VERSION 5.8 ;
BUSBITCHARS "[]" ;
DIVIDERCHAR "/" ;
UNITS
    DATABASE MICRONS 1000 ;
END UNITS

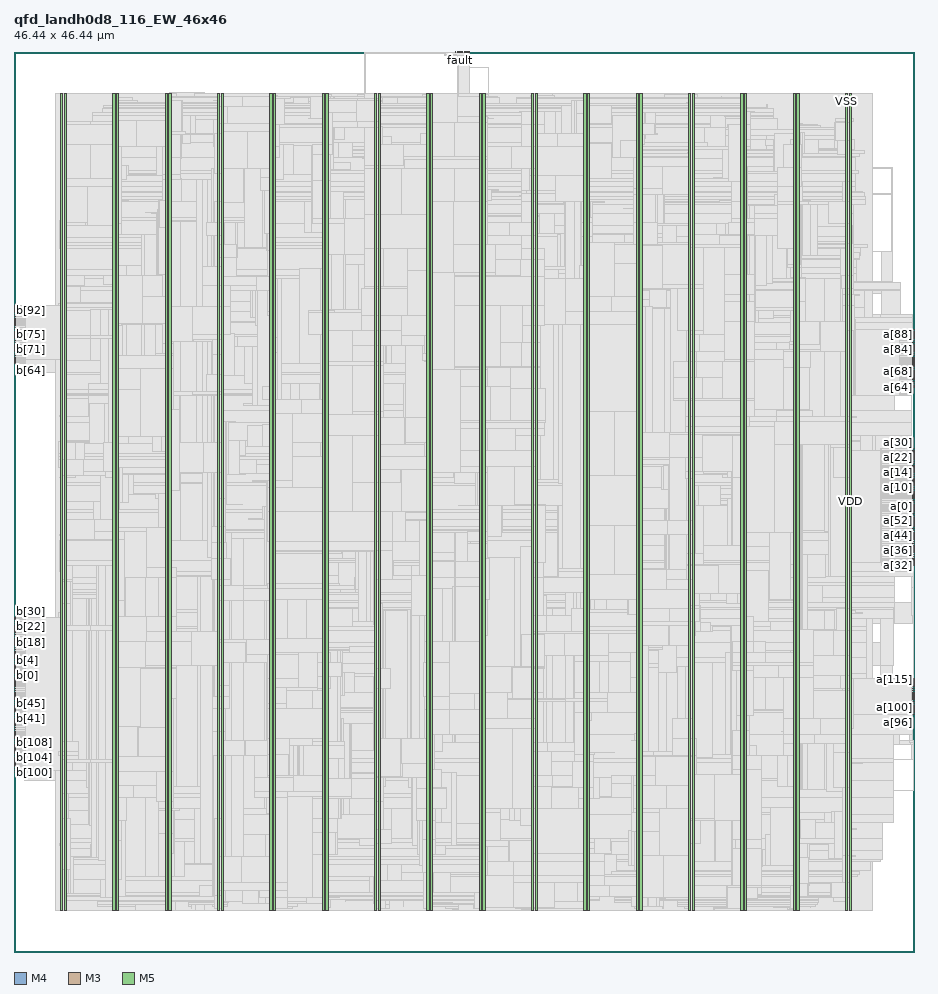
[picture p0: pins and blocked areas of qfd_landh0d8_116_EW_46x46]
MACRO qfd_landh0d8_116_EW_46x46
  FOREIGN qfd_landh0d8_116_EW_46x46 0 0 ;
  CLASS BLOCK ;
  SIZE 46.44 BY 46.44 ;
  PIN a[0]
    DIRECTION INPUT ;
    USE SIGNAL ;
    PORT
      LAYER M4 ;
        RECT  46.356 22.992 46.44 23.016 ;
    END
  END a[0]
  PIN a[100]
    DIRECTION INPUT ;
    USE SIGNAL ;
    PORT
      LAYER M4 ;
        RECT  46.356 12.624 46.44 12.648 ;
    END
  END a[100]
  PIN a[101]
    DIRECTION INPUT ;
    USE SIGNAL ;
    PORT
      LAYER M4 ;
        RECT  46.356 12.72 46.44 12.744 ;
    END
  END a[101]
  PIN a[102]
    DIRECTION INPUT ;
    USE SIGNAL ;
    PORT
      LAYER M4 ;
        RECT  46.356 12.816 46.44 12.84 ;
    END
  END a[102]
  PIN a[103]
    DIRECTION INPUT ;
    USE SIGNAL ;
    PORT
      LAYER M4 ;
        RECT  46.356 12.912 46.44 12.936 ;
    END
  END a[103]
  PIN a[104]
    DIRECTION INPUT ;
    USE SIGNAL ;
    PORT
      LAYER M4 ;
        RECT  46.356 13.008 46.44 13.032 ;
    END
  END a[104]
  PIN a[105]
    DIRECTION INPUT ;
    USE SIGNAL ;
    PORT
      LAYER M4 ;
        RECT  46.356 13.104 46.44 13.128 ;
    END
  END a[105]
  PIN a[106]
    DIRECTION INPUT ;
    USE SIGNAL ;
    PORT
      LAYER M4 ;
        RECT  46.356 13.2 46.44 13.224 ;
    END
  END a[106]
  PIN a[107]
    DIRECTION INPUT ;
    USE SIGNAL ;
    PORT
      LAYER M4 ;
        RECT  46.356 13.296 46.44 13.32 ;
    END
  END a[107]
  PIN a[108]
    DIRECTION INPUT ;
    USE SIGNAL ;
    PORT
      LAYER M4 ;
        RECT  46.356 13.392 46.44 13.416 ;
    END
  END a[108]
  PIN a[109]
    DIRECTION INPUT ;
    USE SIGNAL ;
    PORT
      LAYER M4 ;
        RECT  46.356 13.488 46.44 13.512 ;
    END
  END a[109]
  PIN a[10]
    DIRECTION INPUT ;
    USE SIGNAL ;
    PORT
      LAYER M4 ;
        RECT  46.356 23.952 46.44 23.976 ;
    END
  END a[10]
  PIN a[110]
    DIRECTION INPUT ;
    USE SIGNAL ;
    PORT
      LAYER M4 ;
        RECT  46.356 13.584 46.44 13.608 ;
    END
  END a[110]
  PIN a[111]
    DIRECTION INPUT ;
    USE SIGNAL ;
    PORT
      LAYER M4 ;
        RECT  46.356 13.68 46.44 13.704 ;
    END
  END a[111]
  PIN a[112]
    DIRECTION INPUT ;
    USE SIGNAL ;
    PORT
      LAYER M4 ;
        RECT  46.356 13.776 46.44 13.8 ;
    END
  END a[112]
  PIN a[113]
    DIRECTION INPUT ;
    USE SIGNAL ;
    PORT
      LAYER M4 ;
        RECT  46.356 13.872 46.44 13.896 ;
    END
  END a[113]
  PIN a[114]
    DIRECTION INPUT ;
    USE SIGNAL ;
    PORT
      LAYER M4 ;
        RECT  46.356 13.968 46.44 13.992 ;
    END
  END a[114]
  PIN a[115]
    DIRECTION INPUT ;
    USE SIGNAL ;
    PORT
      LAYER M4 ;
        RECT  46.356 14.064 46.44 14.088 ;
    END
  END a[115]
  PIN a[11]
    DIRECTION INPUT ;
    USE SIGNAL ;
    PORT
      LAYER M4 ;
        RECT  46.356 24.048 46.44 24.072 ;
    END
  END a[11]
  PIN a[12]
    DIRECTION INPUT ;
    USE SIGNAL ;
    PORT
      LAYER M4 ;
        RECT  46.356 24.144 46.44 24.168 ;
    END
  END a[12]
  PIN a[13]
    DIRECTION INPUT ;
    USE SIGNAL ;
    PORT
      LAYER M4 ;
        RECT  46.356 24.24 46.44 24.264 ;
    END
  END a[13]
  PIN a[14]
    DIRECTION INPUT ;
    USE SIGNAL ;
    PORT
      LAYER M4 ;
        RECT  46.356 24.336 46.44 24.36 ;
    END
  END a[14]
  PIN a[15]
    DIRECTION INPUT ;
    USE SIGNAL ;
    PORT
      LAYER M4 ;
        RECT  46.356 24.432 46.44 24.456 ;
    END
  END a[15]
  PIN a[16]
    DIRECTION INPUT ;
    USE SIGNAL ;
    PORT
      LAYER M4 ;
        RECT  46.356 24.528 46.44 24.552 ;
    END
  END a[16]
  PIN a[17]
    DIRECTION INPUT ;
    USE SIGNAL ;
    PORT
      LAYER M4 ;
        RECT  46.356 24.624 46.44 24.648 ;
    END
  END a[17]
  PIN a[18]
    DIRECTION INPUT ;
    USE SIGNAL ;
    PORT
      LAYER M4 ;
        RECT  46.356 24.72 46.44 24.744 ;
    END
  END a[18]
  PIN a[19]
    DIRECTION INPUT ;
    USE SIGNAL ;
    PORT
      LAYER M4 ;
        RECT  46.356 24.816 46.44 24.84 ;
    END
  END a[19]
  PIN a[1]
    DIRECTION INPUT ;
    USE SIGNAL ;
    PORT
      LAYER M4 ;
        RECT  46.356 23.088 46.44 23.112 ;
    END
  END a[1]
  PIN a[20]
    DIRECTION INPUT ;
    USE SIGNAL ;
    PORT
      LAYER M4 ;
        RECT  46.356 24.912 46.44 24.936 ;
    END
  END a[20]
  PIN a[21]
    DIRECTION INPUT ;
    USE SIGNAL ;
    PORT
      LAYER M4 ;
        RECT  46.356 25.008 46.44 25.032 ;
    END
  END a[21]
  PIN a[22]
    DIRECTION INPUT ;
    USE SIGNAL ;
    PORT
      LAYER M4 ;
        RECT  46.356 25.104 46.44 25.128 ;
    END
  END a[22]
  PIN a[23]
    DIRECTION INPUT ;
    USE SIGNAL ;
    PORT
      LAYER M4 ;
        RECT  46.356 25.2 46.44 25.224 ;
    END
  END a[23]
  PIN a[24]
    DIRECTION INPUT ;
    USE SIGNAL ;
    PORT
      LAYER M4 ;
        RECT  46.356 25.296 46.44 25.32 ;
    END
  END a[24]
  PIN a[25]
    DIRECTION INPUT ;
    USE SIGNAL ;
    PORT
      LAYER M4 ;
        RECT  46.356 25.392 46.44 25.416 ;
    END
  END a[25]
  PIN a[26]
    DIRECTION INPUT ;
    USE SIGNAL ;
    PORT
      LAYER M4 ;
        RECT  46.356 25.488 46.44 25.512 ;
    END
  END a[26]
  PIN a[27]
    DIRECTION INPUT ;
    USE SIGNAL ;
    PORT
      LAYER M4 ;
        RECT  46.356 25.584 46.44 25.608 ;
    END
  END a[27]
  PIN a[28]
    DIRECTION INPUT ;
    USE SIGNAL ;
    PORT
      LAYER M4 ;
        RECT  46.356 25.68 46.44 25.704 ;
    END
  END a[28]
  PIN a[29]
    DIRECTION INPUT ;
    USE SIGNAL ;
    PORT
      LAYER M4 ;
        RECT  46.356 25.776 46.44 25.8 ;
    END
  END a[29]
  PIN a[2]
    DIRECTION INPUT ;
    USE SIGNAL ;
    PORT
      LAYER M4 ;
        RECT  46.356 23.184 46.44 23.208 ;
    END
  END a[2]
  PIN a[30]
    DIRECTION INPUT ;
    USE SIGNAL ;
    PORT
      LAYER M4 ;
        RECT  46.356 25.872 46.44 25.896 ;
    END
  END a[30]
  PIN a[31]
    DIRECTION INPUT ;
    USE SIGNAL ;
    PORT
      LAYER M4 ;
        RECT  46.356 25.968 46.44 25.992 ;
    END
  END a[31]
  PIN a[32]
    DIRECTION INPUT ;
    USE SIGNAL ;
    PORT
      LAYER M4 ;
        RECT  46.356 19.92 46.44 19.944 ;
    END
  END a[32]
  PIN a[33]
    DIRECTION INPUT ;
    USE SIGNAL ;
    PORT
      LAYER M4 ;
        RECT  46.356 20.016 46.44 20.04 ;
    END
  END a[33]
  PIN a[34]
    DIRECTION INPUT ;
    USE SIGNAL ;
    PORT
      LAYER M4 ;
        RECT  46.356 20.112 46.44 20.136 ;
    END
  END a[34]
  PIN a[35]
    DIRECTION INPUT ;
    USE SIGNAL ;
    PORT
      LAYER M4 ;
        RECT  46.356 20.208 46.44 20.232 ;
    END
  END a[35]
  PIN a[36]
    DIRECTION INPUT ;
    USE SIGNAL ;
    PORT
      LAYER M4 ;
        RECT  46.356 20.304 46.44 20.328 ;
    END
  END a[36]
  PIN a[37]
    DIRECTION INPUT ;
    USE SIGNAL ;
    PORT
      LAYER M4 ;
        RECT  46.356 20.4 46.44 20.424 ;
    END
  END a[37]
  PIN a[38]
    DIRECTION INPUT ;
    USE SIGNAL ;
    PORT
      LAYER M4 ;
        RECT  46.356 20.496 46.44 20.52 ;
    END
  END a[38]
  PIN a[39]
    DIRECTION INPUT ;
    USE SIGNAL ;
    PORT
      LAYER M4 ;
        RECT  46.356 20.592 46.44 20.616 ;
    END
  END a[39]
  PIN a[3]
    DIRECTION INPUT ;
    USE SIGNAL ;
    PORT
      LAYER M4 ;
        RECT  46.356 23.28 46.44 23.304 ;
    END
  END a[3]
  PIN a[40]
    DIRECTION INPUT ;
    USE SIGNAL ;
    PORT
      LAYER M4 ;
        RECT  46.356 20.688 46.44 20.712 ;
    END
  END a[40]
  PIN a[41]
    DIRECTION INPUT ;
    USE SIGNAL ;
    PORT
      LAYER M4 ;
        RECT  46.356 20.784 46.44 20.808 ;
    END
  END a[41]
  PIN a[42]
    DIRECTION INPUT ;
    USE SIGNAL ;
    PORT
      LAYER M4 ;
        RECT  46.356 20.88 46.44 20.904 ;
    END
  END a[42]
  PIN a[43]
    DIRECTION INPUT ;
    USE SIGNAL ;
    PORT
      LAYER M4 ;
        RECT  46.356 20.976 46.44 21 ;
    END
  END a[43]
  PIN a[44]
    DIRECTION INPUT ;
    USE SIGNAL ;
    PORT
      LAYER M4 ;
        RECT  46.356 21.072 46.44 21.096 ;
    END
  END a[44]
  PIN a[45]
    DIRECTION INPUT ;
    USE SIGNAL ;
    PORT
      LAYER M4 ;
        RECT  46.356 21.168 46.44 21.192 ;
    END
  END a[45]
  PIN a[46]
    DIRECTION INPUT ;
    USE SIGNAL ;
    PORT
      LAYER M4 ;
        RECT  46.356 21.264 46.44 21.288 ;
    END
  END a[46]
  PIN a[47]
    DIRECTION INPUT ;
    USE SIGNAL ;
    PORT
      LAYER M4 ;
        RECT  46.356 21.36 46.44 21.384 ;
    END
  END a[47]
  PIN a[48]
    DIRECTION INPUT ;
    USE SIGNAL ;
    PORT
      LAYER M4 ;
        RECT  46.356 21.456 46.44 21.48 ;
    END
  END a[48]
  PIN a[49]
    DIRECTION INPUT ;
    USE SIGNAL ;
    PORT
      LAYER M4 ;
        RECT  46.356 21.552 46.44 21.576 ;
    END
  END a[49]
  PIN a[4]
    DIRECTION INPUT ;
    USE SIGNAL ;
    PORT
      LAYER M4 ;
        RECT  46.356 23.376 46.44 23.4 ;
    END
  END a[4]
  PIN a[50]
    DIRECTION INPUT ;
    USE SIGNAL ;
    PORT
      LAYER M4 ;
        RECT  46.356 21.648 46.44 21.672 ;
    END
  END a[50]
  PIN a[51]
    DIRECTION INPUT ;
    USE SIGNAL ;
    PORT
      LAYER M4 ;
        RECT  46.356 21.744 46.44 21.768 ;
    END
  END a[51]
  PIN a[52]
    DIRECTION INPUT ;
    USE SIGNAL ;
    PORT
      LAYER M4 ;
        RECT  46.356 21.84 46.44 21.864 ;
    END
  END a[52]
  PIN a[53]
    DIRECTION INPUT ;
    USE SIGNAL ;
    PORT
      LAYER M4 ;
        RECT  46.356 21.936 46.44 21.96 ;
    END
  END a[53]
  PIN a[54]
    DIRECTION INPUT ;
    USE SIGNAL ;
    PORT
      LAYER M4 ;
        RECT  46.356 22.032 46.44 22.056 ;
    END
  END a[54]
  PIN a[55]
    DIRECTION INPUT ;
    USE SIGNAL ;
    PORT
      LAYER M4 ;
        RECT  46.356 22.128 46.44 22.152 ;
    END
  END a[55]
  PIN a[56]
    DIRECTION INPUT ;
    USE SIGNAL ;
    PORT
      LAYER M4 ;
        RECT  46.356 22.224 46.44 22.248 ;
    END
  END a[56]
  PIN a[57]
    DIRECTION INPUT ;
    USE SIGNAL ;
    PORT
      LAYER M4 ;
        RECT  46.356 22.32 46.44 22.344 ;
    END
  END a[57]
  PIN a[58]
    DIRECTION INPUT ;
    USE SIGNAL ;
    PORT
      LAYER M4 ;
        RECT  46.356 22.416 46.44 22.44 ;
    END
  END a[58]
  PIN a[59]
    DIRECTION INPUT ;
    USE SIGNAL ;
    PORT
      LAYER M4 ;
        RECT  46.356 22.512 46.44 22.536 ;
    END
  END a[59]
  PIN a[5]
    DIRECTION INPUT ;
    USE SIGNAL ;
    PORT
      LAYER M4 ;
        RECT  46.356 23.472 46.44 23.496 ;
    END
  END a[5]
  PIN a[60]
    DIRECTION INPUT ;
    USE SIGNAL ;
    PORT
      LAYER M4 ;
        RECT  46.356 22.608 46.44 22.632 ;
    END
  END a[60]
  PIN a[61]
    DIRECTION INPUT ;
    USE SIGNAL ;
    PORT
      LAYER M4 ;
        RECT  46.356 22.704 46.44 22.728 ;
    END
  END a[61]
  PIN a[62]
    DIRECTION INPUT ;
    USE SIGNAL ;
    PORT
      LAYER M4 ;
        RECT  46.356 22.8 46.44 22.824 ;
    END
  END a[62]
  PIN a[63]
    DIRECTION INPUT ;
    USE SIGNAL ;
    PORT
      LAYER M4 ;
        RECT  46.356 22.896 46.44 22.92 ;
    END
  END a[63]
  PIN a[64]
    DIRECTION INPUT ;
    USE SIGNAL ;
    PORT
      LAYER M4 ;
        RECT  46.356 29.136 46.44 29.16 ;
    END
  END a[64]
  PIN a[65]
    DIRECTION INPUT ;
    USE SIGNAL ;
    PORT
      LAYER M4 ;
        RECT  46.356 29.232 46.44 29.256 ;
    END
  END a[65]
  PIN a[66]
    DIRECTION INPUT ;
    USE SIGNAL ;
    PORT
      LAYER M4 ;
        RECT  46.356 29.328 46.44 29.352 ;
    END
  END a[66]
  PIN a[67]
    DIRECTION INPUT ;
    USE SIGNAL ;
    PORT
      LAYER M4 ;
        RECT  46.356 29.424 46.44 29.448 ;
    END
  END a[67]
  PIN a[68]
    DIRECTION INPUT ;
    USE SIGNAL ;
    PORT
      LAYER M4 ;
        RECT  46.356 29.52 46.44 29.544 ;
    END
  END a[68]
  PIN a[69]
    DIRECTION INPUT ;
    USE SIGNAL ;
    PORT
      LAYER M4 ;
        RECT  46.356 29.616 46.44 29.64 ;
    END
  END a[69]
  PIN a[6]
    DIRECTION INPUT ;
    USE SIGNAL ;
    PORT
      LAYER M4 ;
        RECT  46.356 23.568 46.44 23.592 ;
    END
  END a[6]
  PIN a[70]
    DIRECTION INPUT ;
    USE SIGNAL ;
    PORT
      LAYER M4 ;
        RECT  46.356 29.712 46.44 29.736 ;
    END
  END a[70]
  PIN a[71]
    DIRECTION INPUT ;
    USE SIGNAL ;
    PORT
      LAYER M4 ;
        RECT  46.356 29.808 46.44 29.832 ;
    END
  END a[71]
  PIN a[72]
    DIRECTION INPUT ;
    USE SIGNAL ;
    PORT
      LAYER M4 ;
        RECT  46.356 29.904 46.44 29.928 ;
    END
  END a[72]
  PIN a[73]
    DIRECTION INPUT ;
    USE SIGNAL ;
    PORT
      LAYER M4 ;
        RECT  46.356 30 46.44 30.024 ;
    END
  END a[73]
  PIN a[74]
    DIRECTION INPUT ;
    USE SIGNAL ;
    PORT
      LAYER M4 ;
        RECT  46.356 30.096 46.44 30.12 ;
    END
  END a[74]
  PIN a[75]
    DIRECTION INPUT ;
    USE SIGNAL ;
    PORT
      LAYER M4 ;
        RECT  46.356 30.192 46.44 30.216 ;
    END
  END a[75]
  PIN a[76]
    DIRECTION INPUT ;
    USE SIGNAL ;
    PORT
      LAYER M4 ;
        RECT  46.356 30.288 46.44 30.312 ;
    END
  END a[76]
  PIN a[77]
    DIRECTION INPUT ;
    USE SIGNAL ;
    PORT
      LAYER M4 ;
        RECT  46.356 30.384 46.44 30.408 ;
    END
  END a[77]
  PIN a[78]
    DIRECTION INPUT ;
    USE SIGNAL ;
    PORT
      LAYER M4 ;
        RECT  46.356 30.48 46.44 30.504 ;
    END
  END a[78]
  PIN a[79]
    DIRECTION INPUT ;
    USE SIGNAL ;
    PORT
      LAYER M4 ;
        RECT  46.356 30.576 46.44 30.6 ;
    END
  END a[79]
  PIN a[7]
    DIRECTION INPUT ;
    USE SIGNAL ;
    PORT
      LAYER M4 ;
        RECT  46.356 23.664 46.44 23.688 ;
    END
  END a[7]
  PIN a[80]
    DIRECTION INPUT ;
    USE SIGNAL ;
    PORT
      LAYER M4 ;
        RECT  46.356 30.672 46.44 30.696 ;
    END
  END a[80]
  PIN a[81]
    DIRECTION INPUT ;
    USE SIGNAL ;
    PORT
      LAYER M4 ;
        RECT  46.356 30.768 46.44 30.792 ;
    END
  END a[81]
  PIN a[82]
    DIRECTION INPUT ;
    USE SIGNAL ;
    PORT
      LAYER M4 ;
        RECT  46.356 30.864 46.44 30.888 ;
    END
  END a[82]
  PIN a[83]
    DIRECTION INPUT ;
    USE SIGNAL ;
    PORT
      LAYER M4 ;
        RECT  46.356 30.96 46.44 30.984 ;
    END
  END a[83]
  PIN a[84]
    DIRECTION INPUT ;
    USE SIGNAL ;
    PORT
      LAYER M4 ;
        RECT  46.356 31.056 46.44 31.08 ;
    END
  END a[84]
  PIN a[85]
    DIRECTION INPUT ;
    USE SIGNAL ;
    PORT
      LAYER M4 ;
        RECT  46.356 31.152 46.44 31.176 ;
    END
  END a[85]
  PIN a[86]
    DIRECTION INPUT ;
    USE SIGNAL ;
    PORT
      LAYER M4 ;
        RECT  46.356 31.248 46.44 31.272 ;
    END
  END a[86]
  PIN a[87]
    DIRECTION INPUT ;
    USE SIGNAL ;
    PORT
      LAYER M4 ;
        RECT  46.356 31.344 46.44 31.368 ;
    END
  END a[87]
  PIN a[88]
    DIRECTION INPUT ;
    USE SIGNAL ;
    PORT
      LAYER M4 ;
        RECT  46.356 31.44 46.44 31.464 ;
    END
  END a[88]
  PIN a[89]
    DIRECTION INPUT ;
    USE SIGNAL ;
    PORT
      LAYER M4 ;
        RECT  46.356 31.536 46.44 31.56 ;
    END
  END a[89]
  PIN a[8]
    DIRECTION INPUT ;
    USE SIGNAL ;
    PORT
      LAYER M4 ;
        RECT  46.356 23.76 46.44 23.784 ;
    END
  END a[8]
  PIN a[90]
    DIRECTION INPUT ;
    USE SIGNAL ;
    PORT
      LAYER M4 ;
        RECT  46.356 31.632 46.44 31.656 ;
    END
  END a[90]
  PIN a[91]
    DIRECTION INPUT ;
    USE SIGNAL ;
    PORT
      LAYER M4 ;
        RECT  46.356 31.728 46.44 31.752 ;
    END
  END a[91]
  PIN a[92]
    DIRECTION INPUT ;
    USE SIGNAL ;
    PORT
      LAYER M4 ;
        RECT  46.356 31.824 46.44 31.848 ;
    END
  END a[92]
  PIN a[93]
    DIRECTION INPUT ;
    USE SIGNAL ;
    PORT
      LAYER M4 ;
        RECT  46.356 31.92 46.44 31.944 ;
    END
  END a[93]
  PIN a[94]
    DIRECTION INPUT ;
    USE SIGNAL ;
    PORT
      LAYER M4 ;
        RECT  46.356 32.016 46.44 32.04 ;
    END
  END a[94]
  PIN a[95]
    DIRECTION INPUT ;
    USE SIGNAL ;
    PORT
      LAYER M4 ;
        RECT  46.356 32.112 46.44 32.136 ;
    END
  END a[95]
  PIN a[96]
    DIRECTION INPUT ;
    USE SIGNAL ;
    PORT
      LAYER M4 ;
        RECT  46.356 12.24 46.44 12.264 ;
    END
  END a[96]
  PIN a[97]
    DIRECTION INPUT ;
    USE SIGNAL ;
    PORT
      LAYER M4 ;
        RECT  46.356 12.336 46.44 12.36 ;
    END
  END a[97]
  PIN a[98]
    DIRECTION INPUT ;
    USE SIGNAL ;
    PORT
      LAYER M4 ;
        RECT  46.356 12.432 46.44 12.456 ;
    END
  END a[98]
  PIN a[99]
    DIRECTION INPUT ;
    USE SIGNAL ;
    PORT
      LAYER M4 ;
        RECT  46.356 12.528 46.44 12.552 ;
    END
  END a[99]
  PIN a[9]
    DIRECTION INPUT ;
    USE SIGNAL ;
    PORT
      LAYER M4 ;
        RECT  46.356 23.856 46.44 23.88 ;
    END
  END a[9]
  PIN b[0]
    DIRECTION OUTPUT ;
    USE SIGNAL ;
    PORT
      LAYER M4 ;
        RECT  0 14.256 0.084 14.28 ;
    END
  END b[0]
  PIN b[100]
    DIRECTION OUTPUT ;
    USE SIGNAL ;
    PORT
      LAYER M4 ;
        RECT  0 9.648 0.084 9.672 ;
    END
  END b[100]
  PIN b[101]
    DIRECTION OUTPUT ;
    USE SIGNAL ;
    PORT
      LAYER M4 ;
        RECT  0 9.744 0.084 9.768 ;
    END
  END b[101]
  PIN b[102]
    DIRECTION OUTPUT ;
    USE SIGNAL ;
    PORT
      LAYER M4 ;
        RECT  0 9.84 0.084 9.864 ;
    END
  END b[102]
  PIN b[103]
    DIRECTION OUTPUT ;
    USE SIGNAL ;
    PORT
      LAYER M4 ;
        RECT  0 9.936 0.084 9.96 ;
    END
  END b[103]
  PIN b[104]
    DIRECTION OUTPUT ;
    USE SIGNAL ;
    PORT
      LAYER M4 ;
        RECT  0 10.032 0.084 10.056 ;
    END
  END b[104]
  PIN b[105]
    DIRECTION OUTPUT ;
    USE SIGNAL ;
    PORT
      LAYER M4 ;
        RECT  0 10.128 0.084 10.152 ;
    END
  END b[105]
  PIN b[106]
    DIRECTION OUTPUT ;
    USE SIGNAL ;
    PORT
      LAYER M4 ;
        RECT  0 10.224 0.084 10.248 ;
    END
  END b[106]
  PIN b[107]
    DIRECTION OUTPUT ;
    USE SIGNAL ;
    PORT
      LAYER M4 ;
        RECT  0 10.32 0.084 10.344 ;
    END
  END b[107]
  PIN b[108]
    DIRECTION OUTPUT ;
    USE SIGNAL ;
    PORT
      LAYER M4 ;
        RECT  0 10.416 0.084 10.44 ;
    END
  END b[108]
  PIN b[109]
    DIRECTION OUTPUT ;
    USE SIGNAL ;
    PORT
      LAYER M4 ;
        RECT  0 10.512 0.084 10.536 ;
    END
  END b[109]
  PIN b[10]
    DIRECTION OUTPUT ;
    USE SIGNAL ;
    PORT
      LAYER M4 ;
        RECT  0 15.216 0.084 15.24 ;
    END
  END b[10]
  PIN b[110]
    DIRECTION OUTPUT ;
    USE SIGNAL ;
    PORT
      LAYER M4 ;
        RECT  0 10.608 0.084 10.632 ;
    END
  END b[110]
  PIN b[111]
    DIRECTION OUTPUT ;
    USE SIGNAL ;
    PORT
      LAYER M4 ;
        RECT  0 10.704 0.084 10.728 ;
    END
  END b[111]
  PIN b[112]
    DIRECTION OUTPUT ;
    USE SIGNAL ;
    PORT
      LAYER M4 ;
        RECT  0 10.8 0.084 10.824 ;
    END
  END b[112]
  PIN b[113]
    DIRECTION OUTPUT ;
    USE SIGNAL ;
    PORT
      LAYER M4 ;
        RECT  0 10.896 0.084 10.92 ;
    END
  END b[113]
  PIN b[114]
    DIRECTION OUTPUT ;
    USE SIGNAL ;
    PORT
      LAYER M4 ;
        RECT  0 10.992 0.084 11.016 ;
    END
  END b[114]
  PIN b[115]
    DIRECTION OUTPUT ;
    USE SIGNAL ;
    PORT
      LAYER M4 ;
        RECT  0 11.088 0.084 11.112 ;
    END
  END b[115]
  PIN b[11]
    DIRECTION OUTPUT ;
    USE SIGNAL ;
    PORT
      LAYER M4 ;
        RECT  0 15.312 0.084 15.336 ;
    END
  END b[11]
  PIN b[12]
    DIRECTION OUTPUT ;
    USE SIGNAL ;
    PORT
      LAYER M4 ;
        RECT  0 15.408 0.084 15.432 ;
    END
  END b[12]
  PIN b[13]
    DIRECTION OUTPUT ;
    USE SIGNAL ;
    PORT
      LAYER M4 ;
        RECT  0 15.504 0.084 15.528 ;
    END
  END b[13]
  PIN b[14]
    DIRECTION OUTPUT ;
    USE SIGNAL ;
    PORT
      LAYER M4 ;
        RECT  0 15.6 0.084 15.624 ;
    END
  END b[14]
  PIN b[15]
    DIRECTION OUTPUT ;
    USE SIGNAL ;
    PORT
      LAYER M4 ;
        RECT  0 15.696 0.084 15.72 ;
    END
  END b[15]
  PIN b[16]
    DIRECTION OUTPUT ;
    USE SIGNAL ;
    PORT
      LAYER M4 ;
        RECT  0 15.792 0.084 15.816 ;
    END
  END b[16]
  PIN b[17]
    DIRECTION OUTPUT ;
    USE SIGNAL ;
    PORT
      LAYER M4 ;
        RECT  0 15.888 0.084 15.912 ;
    END
  END b[17]
  PIN b[18]
    DIRECTION OUTPUT ;
    USE SIGNAL ;
    PORT
      LAYER M4 ;
        RECT  0 15.984 0.084 16.008 ;
    END
  END b[18]
  PIN b[19]
    DIRECTION OUTPUT ;
    USE SIGNAL ;
    PORT
      LAYER M4 ;
        RECT  0 16.08 0.084 16.104 ;
    END
  END b[19]
  PIN b[1]
    DIRECTION OUTPUT ;
    USE SIGNAL ;
    PORT
      LAYER M4 ;
        RECT  0 14.352 0.084 14.376 ;
    END
  END b[1]
  PIN b[20]
    DIRECTION OUTPUT ;
    USE SIGNAL ;
    PORT
      LAYER M4 ;
        RECT  0 16.176 0.084 16.2 ;
    END
  END b[20]
  PIN b[21]
    DIRECTION OUTPUT ;
    USE SIGNAL ;
    PORT
      LAYER M4 ;
        RECT  0 16.272 0.084 16.296 ;
    END
  END b[21]
  PIN b[22]
    DIRECTION OUTPUT ;
    USE SIGNAL ;
    PORT
      LAYER M4 ;
        RECT  0 16.368 0.084 16.392 ;
    END
  END b[22]
  PIN b[23]
    DIRECTION OUTPUT ;
    USE SIGNAL ;
    PORT
      LAYER M4 ;
        RECT  0 16.464 0.084 16.488 ;
    END
  END b[23]
  PIN b[24]
    DIRECTION OUTPUT ;
    USE SIGNAL ;
    PORT
      LAYER M4 ;
        RECT  0 16.56 0.084 16.584 ;
    END
  END b[24]
  PIN b[25]
    DIRECTION OUTPUT ;
    USE SIGNAL ;
    PORT
      LAYER M4 ;
        RECT  0 16.656 0.084 16.68 ;
    END
  END b[25]
  PIN b[26]
    DIRECTION OUTPUT ;
    USE SIGNAL ;
    PORT
      LAYER M4 ;
        RECT  0 16.752 0.084 16.776 ;
    END
  END b[26]
  PIN b[27]
    DIRECTION OUTPUT ;
    USE SIGNAL ;
    PORT
      LAYER M4 ;
        RECT  0 16.848 0.084 16.872 ;
    END
  END b[27]
  PIN b[28]
    DIRECTION OUTPUT ;
    USE SIGNAL ;
    PORT
      LAYER M4 ;
        RECT  0 16.944 0.084 16.968 ;
    END
  END b[28]
  PIN b[29]
    DIRECTION OUTPUT ;
    USE SIGNAL ;
    PORT
      LAYER M4 ;
        RECT  0 17.04 0.084 17.064 ;
    END
  END b[29]
  PIN b[2]
    DIRECTION OUTPUT ;
    USE SIGNAL ;
    PORT
      LAYER M4 ;
        RECT  0 14.448 0.084 14.472 ;
    END
  END b[2]
  PIN b[30]
    DIRECTION OUTPUT ;
    USE SIGNAL ;
    PORT
      LAYER M4 ;
        RECT  0 17.136 0.084 17.16 ;
    END
  END b[30]
  PIN b[31]
    DIRECTION OUTPUT ;
    USE SIGNAL ;
    PORT
      LAYER M4 ;
        RECT  0 17.232 0.084 17.256 ;
    END
  END b[31]
  PIN b[32]
    DIRECTION OUTPUT ;
    USE SIGNAL ;
    PORT
      LAYER M4 ;
        RECT  0 11.184 0.084 11.208 ;
    END
  END b[32]
  PIN b[33]
    DIRECTION OUTPUT ;
    USE SIGNAL ;
    PORT
      LAYER M4 ;
        RECT  0 11.28 0.084 11.304 ;
    END
  END b[33]
  PIN b[34]
    DIRECTION OUTPUT ;
    USE SIGNAL ;
    PORT
      LAYER M4 ;
        RECT  0 11.376 0.084 11.4 ;
    END
  END b[34]
  PIN b[35]
    DIRECTION OUTPUT ;
    USE SIGNAL ;
    PORT
      LAYER M4 ;
        RECT  0 11.472 0.084 11.496 ;
    END
  END b[35]
  PIN b[36]
    DIRECTION OUTPUT ;
    USE SIGNAL ;
    PORT
      LAYER M4 ;
        RECT  0 11.568 0.084 11.592 ;
    END
  END b[36]
  PIN b[37]
    DIRECTION OUTPUT ;
    USE SIGNAL ;
    PORT
      LAYER M4 ;
        RECT  0 11.664 0.084 11.688 ;
    END
  END b[37]
  PIN b[38]
    DIRECTION OUTPUT ;
    USE SIGNAL ;
    PORT
      LAYER M4 ;
        RECT  0 11.76 0.084 11.784 ;
    END
  END b[38]
  PIN b[39]
    DIRECTION OUTPUT ;
    USE SIGNAL ;
    PORT
      LAYER M4 ;
        RECT  0 11.856 0.084 11.88 ;
    END
  END b[39]
  PIN b[3]
    DIRECTION OUTPUT ;
    USE SIGNAL ;
    PORT
      LAYER M4 ;
        RECT  0 14.544 0.084 14.568 ;
    END
  END b[3]
  PIN b[40]
    DIRECTION OUTPUT ;
    USE SIGNAL ;
    PORT
      LAYER M4 ;
        RECT  0 11.952 0.084 11.976 ;
    END
  END b[40]
  PIN b[41]
    DIRECTION OUTPUT ;
    USE SIGNAL ;
    PORT
      LAYER M4 ;
        RECT  0 12.048 0.084 12.072 ;
    END
  END b[41]
  PIN b[42]
    DIRECTION OUTPUT ;
    USE SIGNAL ;
    PORT
      LAYER M4 ;
        RECT  0 12.144 0.084 12.168 ;
    END
  END b[42]
  PIN b[43]
    DIRECTION OUTPUT ;
    USE SIGNAL ;
    PORT
      LAYER M4 ;
        RECT  0 12.24 0.084 12.264 ;
    END
  END b[43]
  PIN b[44]
    DIRECTION OUTPUT ;
    USE SIGNAL ;
    PORT
      LAYER M4 ;
        RECT  0 12.336 0.084 12.36 ;
    END
  END b[44]
  PIN b[45]
    DIRECTION OUTPUT ;
    USE SIGNAL ;
    PORT
      LAYER M4 ;
        RECT  0 12.432 0.084 12.456 ;
    END
  END b[45]
  PIN b[46]
    DIRECTION OUTPUT ;
    USE SIGNAL ;
    PORT
      LAYER M4 ;
        RECT  0 12.528 0.084 12.552 ;
    END
  END b[46]
  PIN b[47]
    DIRECTION OUTPUT ;
    USE SIGNAL ;
    PORT
      LAYER M4 ;
        RECT  0 12.624 0.084 12.648 ;
    END
  END b[47]
  PIN b[48]
    DIRECTION OUTPUT ;
    USE SIGNAL ;
    PORT
      LAYER M4 ;
        RECT  0 12.72 0.084 12.744 ;
    END
  END b[48]
  PIN b[49]
    DIRECTION OUTPUT ;
    USE SIGNAL ;
    PORT
      LAYER M4 ;
        RECT  0 12.816 0.084 12.84 ;
    END
  END b[49]
  PIN b[4]
    DIRECTION OUTPUT ;
    USE SIGNAL ;
    PORT
      LAYER M4 ;
        RECT  0 14.64 0.084 14.664 ;
    END
  END b[4]
  PIN b[50]
    DIRECTION OUTPUT ;
    USE SIGNAL ;
    PORT
      LAYER M4 ;
        RECT  0 12.912 0.084 12.936 ;
    END
  END b[50]
  PIN b[51]
    DIRECTION OUTPUT ;
    USE SIGNAL ;
    PORT
      LAYER M4 ;
        RECT  0 13.008 0.084 13.032 ;
    END
  END b[51]
  PIN b[52]
    DIRECTION OUTPUT ;
    USE SIGNAL ;
    PORT
      LAYER M4 ;
        RECT  0 13.104 0.084 13.128 ;
    END
  END b[52]
  PIN b[53]
    DIRECTION OUTPUT ;
    USE SIGNAL ;
    PORT
      LAYER M4 ;
        RECT  0 13.2 0.084 13.224 ;
    END
  END b[53]
  PIN b[54]
    DIRECTION OUTPUT ;
    USE SIGNAL ;
    PORT
      LAYER M4 ;
        RECT  0 13.296 0.084 13.32 ;
    END
  END b[54]
  PIN b[55]
    DIRECTION OUTPUT ;
    USE SIGNAL ;
    PORT
      LAYER M4 ;
        RECT  0 13.392 0.084 13.416 ;
    END
  END b[55]
  PIN b[56]
    DIRECTION OUTPUT ;
    USE SIGNAL ;
    PORT
      LAYER M4 ;
        RECT  0 13.488 0.084 13.512 ;
    END
  END b[56]
  PIN b[57]
    DIRECTION OUTPUT ;
    USE SIGNAL ;
    PORT
      LAYER M4 ;
        RECT  0 13.584 0.084 13.608 ;
    END
  END b[57]
  PIN b[58]
    DIRECTION OUTPUT ;
    USE SIGNAL ;
    PORT
      LAYER M4 ;
        RECT  0 13.68 0.084 13.704 ;
    END
  END b[58]
  PIN b[59]
    DIRECTION OUTPUT ;
    USE SIGNAL ;
    PORT
      LAYER M4 ;
        RECT  0 13.776 0.084 13.8 ;
    END
  END b[59]
  PIN b[5]
    DIRECTION OUTPUT ;
    USE SIGNAL ;
    PORT
      LAYER M4 ;
        RECT  0 14.736 0.084 14.76 ;
    END
  END b[5]
  PIN b[60]
    DIRECTION OUTPUT ;
    USE SIGNAL ;
    PORT
      LAYER M4 ;
        RECT  0 13.872 0.084 13.896 ;
    END
  END b[60]
  PIN b[61]
    DIRECTION OUTPUT ;
    USE SIGNAL ;
    PORT
      LAYER M4 ;
        RECT  0 13.968 0.084 13.992 ;
    END
  END b[61]
  PIN b[62]
    DIRECTION OUTPUT ;
    USE SIGNAL ;
    PORT
      LAYER M4 ;
        RECT  0 14.064 0.084 14.088 ;
    END
  END b[62]
  PIN b[63]
    DIRECTION OUTPUT ;
    USE SIGNAL ;
    PORT
      LAYER M4 ;
        RECT  0 14.16 0.084 14.184 ;
    END
  END b[63]
  PIN b[64]
    DIRECTION OUTPUT ;
    USE SIGNAL ;
    PORT
      LAYER M4 ;
        RECT  0 30.384 0.084 30.408 ;
    END
  END b[64]
  PIN b[65]
    DIRECTION OUTPUT ;
    USE SIGNAL ;
    PORT
      LAYER M4 ;
        RECT  0 30.48 0.084 30.504 ;
    END
  END b[65]
  PIN b[66]
    DIRECTION OUTPUT ;
    USE SIGNAL ;
    PORT
      LAYER M4 ;
        RECT  0 30.576 0.084 30.6 ;
    END
  END b[66]
  PIN b[67]
    DIRECTION OUTPUT ;
    USE SIGNAL ;
    PORT
      LAYER M4 ;
        RECT  0 30.672 0.084 30.696 ;
    END
  END b[67]
  PIN b[68]
    DIRECTION OUTPUT ;
    USE SIGNAL ;
    PORT
      LAYER M4 ;
        RECT  0 30.768 0.084 30.792 ;
    END
  END b[68]
  PIN b[69]
    DIRECTION OUTPUT ;
    USE SIGNAL ;
    PORT
      LAYER M4 ;
        RECT  0 30.864 0.084 30.888 ;
    END
  END b[69]
  PIN b[6]
    DIRECTION OUTPUT ;
    USE SIGNAL ;
    PORT
      LAYER M4 ;
        RECT  0 14.832 0.084 14.856 ;
    END
  END b[6]
  PIN b[70]
    DIRECTION OUTPUT ;
    USE SIGNAL ;
    PORT
      LAYER M4 ;
        RECT  0 30.96 0.084 30.984 ;
    END
  END b[70]
  PIN b[71]
    DIRECTION OUTPUT ;
    USE SIGNAL ;
    PORT
      LAYER M4 ;
        RECT  0 31.056 0.084 31.08 ;
    END
  END b[71]
  PIN b[72]
    DIRECTION OUTPUT ;
    USE SIGNAL ;
    PORT
      LAYER M4 ;
        RECT  0 31.152 0.084 31.176 ;
    END
  END b[72]
  PIN b[73]
    DIRECTION OUTPUT ;
    USE SIGNAL ;
    PORT
      LAYER M4 ;
        RECT  0 31.248 0.084 31.272 ;
    END
  END b[73]
  PIN b[74]
    DIRECTION OUTPUT ;
    USE SIGNAL ;
    PORT
      LAYER M4 ;
        RECT  0 31.344 0.084 31.368 ;
    END
  END b[74]
  PIN b[75]
    DIRECTION OUTPUT ;
    USE SIGNAL ;
    PORT
      LAYER M4 ;
        RECT  0 31.44 0.084 31.464 ;
    END
  END b[75]
  PIN b[76]
    DIRECTION OUTPUT ;
    USE SIGNAL ;
    PORT
      LAYER M4 ;
        RECT  0 31.536 0.084 31.56 ;
    END
  END b[76]
  PIN b[77]
    DIRECTION OUTPUT ;
    USE SIGNAL ;
    PORT
      LAYER M4 ;
        RECT  0 31.632 0.084 31.656 ;
    END
  END b[77]
  PIN b[78]
    DIRECTION OUTPUT ;
    USE SIGNAL ;
    PORT
      LAYER M4 ;
        RECT  0 31.728 0.084 31.752 ;
    END
  END b[78]
  PIN b[79]
    DIRECTION OUTPUT ;
    USE SIGNAL ;
    PORT
      LAYER M4 ;
        RECT  0 31.824 0.084 31.848 ;
    END
  END b[79]
  PIN b[7]
    DIRECTION OUTPUT ;
    USE SIGNAL ;
    PORT
      LAYER M4 ;
        RECT  0 14.928 0.084 14.952 ;
    END
  END b[7]
  PIN b[80]
    DIRECTION OUTPUT ;
    USE SIGNAL ;
    PORT
      LAYER M4 ;
        RECT  0 31.92 0.084 31.944 ;
    END
  END b[80]
  PIN b[81]
    DIRECTION OUTPUT ;
    USE SIGNAL ;
    PORT
      LAYER M4 ;
        RECT  0 32.016 0.084 32.04 ;
    END
  END b[81]
  PIN b[82]
    DIRECTION OUTPUT ;
    USE SIGNAL ;
    PORT
      LAYER M4 ;
        RECT  0 32.112 0.084 32.136 ;
    END
  END b[82]
  PIN b[83]
    DIRECTION OUTPUT ;
    USE SIGNAL ;
    PORT
      LAYER M4 ;
        RECT  0 32.208 0.084 32.232 ;
    END
  END b[83]
  PIN b[84]
    DIRECTION OUTPUT ;
    USE SIGNAL ;
    PORT
      LAYER M4 ;
        RECT  0 32.304 0.084 32.328 ;
    END
  END b[84]
  PIN b[85]
    DIRECTION OUTPUT ;
    USE SIGNAL ;
    PORT
      LAYER M4 ;
        RECT  0 32.4 0.084 32.424 ;
    END
  END b[85]
  PIN b[86]
    DIRECTION OUTPUT ;
    USE SIGNAL ;
    PORT
      LAYER M4 ;
        RECT  0 32.496 0.084 32.52 ;
    END
  END b[86]
  PIN b[87]
    DIRECTION OUTPUT ;
    USE SIGNAL ;
    PORT
      LAYER M4 ;
        RECT  0 32.592 0.084 32.616 ;
    END
  END b[87]
  PIN b[88]
    DIRECTION OUTPUT ;
    USE SIGNAL ;
    PORT
      LAYER M4 ;
        RECT  0 32.688 0.084 32.712 ;
    END
  END b[88]
  PIN b[89]
    DIRECTION OUTPUT ;
    USE SIGNAL ;
    PORT
      LAYER M4 ;
        RECT  0 32.784 0.084 32.808 ;
    END
  END b[89]
  PIN b[8]
    DIRECTION OUTPUT ;
    USE SIGNAL ;
    PORT
      LAYER M4 ;
        RECT  0 15.024 0.084 15.048 ;
    END
  END b[8]
  PIN b[90]
    DIRECTION OUTPUT ;
    USE SIGNAL ;
    PORT
      LAYER M4 ;
        RECT  0 32.88 0.084 32.904 ;
    END
  END b[90]
  PIN b[91]
    DIRECTION OUTPUT ;
    USE SIGNAL ;
    PORT
      LAYER M4 ;
        RECT  0 32.976 0.084 33 ;
    END
  END b[91]
  PIN b[92]
    DIRECTION OUTPUT ;
    USE SIGNAL ;
    PORT
      LAYER M4 ;
        RECT  0 33.072 0.084 33.096 ;
    END
  END b[92]
  PIN b[93]
    DIRECTION OUTPUT ;
    USE SIGNAL ;
    PORT
      LAYER M4 ;
        RECT  0 33.168 0.084 33.192 ;
    END
  END b[93]
  PIN b[94]
    DIRECTION OUTPUT ;
    USE SIGNAL ;
    PORT
      LAYER M4 ;
        RECT  0 33.264 0.084 33.288 ;
    END
  END b[94]
  PIN b[95]
    DIRECTION OUTPUT ;
    USE SIGNAL ;
    PORT
      LAYER M4 ;
        RECT  0 33.36 0.084 33.384 ;
    END
  END b[95]
  PIN b[96]
    DIRECTION OUTPUT ;
    USE SIGNAL ;
    PORT
      LAYER M4 ;
        RECT  0 9.264 0.084 9.288 ;
    END
  END b[96]
  PIN b[97]
    DIRECTION OUTPUT ;
    USE SIGNAL ;
    PORT
      LAYER M4 ;
        RECT  0 9.36 0.084 9.384 ;
    END
  END b[97]
  PIN b[98]
    DIRECTION OUTPUT ;
    USE SIGNAL ;
    PORT
      LAYER M4 ;
        RECT  0 9.456 0.084 9.48 ;
    END
  END b[98]
  PIN b[99]
    DIRECTION OUTPUT ;
    USE SIGNAL ;
    PORT
      LAYER M4 ;
        RECT  0 9.552 0.084 9.576 ;
    END
  END b[99]
  PIN b[9]
    DIRECTION OUTPUT ;
    USE SIGNAL ;
    PORT
      LAYER M4 ;
        RECT  0 15.12 0.084 15.144 ;
    END
  END b[9]
  PIN ck
    DIRECTION INPUT ;
    USE SIGNAL ;
    PORT
      LAYER M3 ;
        RECT  22.788 46.403 22.806 46.44 ;
    END
  END ck
  PIN ck_s
    DIRECTION INPUT ;
    USE SIGNAL ;
    PORT
      LAYER M3 ;
        RECT  22.86 46.403 22.878 46.44 ;
    END
  END ck_s
  PIN en
    DIRECTION INPUT ;
    USE SIGNAL ;
    PORT
      LAYER M3 ;
        RECT  22.932 46.403 22.95 46.44 ;
    END
  END en
  PIN fault
    DIRECTION OUTPUT ;
    USE SIGNAL ;
    PORT
      LAYER M3 ;
        RECT  23.004 46.403 23.022 46.44 ;
    END
  END fault
  PIN k0
    DIRECTION INPUT ;
    USE SIGNAL ;
    PORT
      LAYER M3 ;
        RECT  23.076 46.403 23.094 46.44 ;
    END
  END k0
  PIN k1
    DIRECTION INPUT ;
    USE SIGNAL ;
    PORT
      LAYER M3 ;
        RECT  23.148 46.403 23.166 46.44 ;
    END
  END k1
  PIN k2
    DIRECTION INPUT ;
    USE SIGNAL ;
    PORT
      LAYER M3 ;
        RECT  23.22 46.403 23.238 46.44 ;
    END
  END k2
  PIN k3
    DIRECTION INPUT ;
    USE SIGNAL ;
    PORT
      LAYER M3 ;
        RECT  23.292 46.403 23.31 46.44 ;
    END
  END k3
  PIN rs
    DIRECTION INPUT ;
    USE SIGNAL ;
    PORT
      LAYER M3 ;
        RECT  23.364 46.403 23.382 46.44 ;
    END
  END rs
  PIN tie_hi
    DIRECTION OUTPUT ;
    USE SIGNAL ;
    PORT
      LAYER M3 ;
        RECT  23.436 46.403 23.454 46.44 ;
    END
  END tie_hi
  PIN tie_lo
    DIRECTION OUTPUT ;
    USE SIGNAL ;
    PORT
      LAYER M3 ;
        RECT  23.508 46.403 23.526 46.44 ;
    END
  END tie_lo
  PIN VSS
    DIRECTION INOUT ;
    USE GROUND ;
    PORT
      LAYER M5 ;
        RECT  42.9 2.137 43.02 44.303 ;
        RECT  40.2 2.137 40.32 44.303 ;
        RECT  37.5 2.137 37.62 44.303 ;
        RECT  34.8 2.137 34.92 44.303 ;
        RECT  32.1 2.137 32.22 44.303 ;
        RECT  29.4 2.137 29.52 44.303 ;
        RECT  26.7 2.137 26.82 44.303 ;
        RECT  24 2.137 24.12 44.303 ;
        RECT  21.3 2.137 21.42 44.303 ;
        RECT  18.6 2.137 18.72 44.303 ;
        RECT  15.9 2.137 16.02 44.303 ;
        RECT  13.2 2.137 13.32 44.303 ;
        RECT  10.5 2.137 10.62 44.303 ;
        RECT  7.8 2.137 7.92 44.303 ;
        RECT  5.1 2.137 5.22 44.303 ;
        RECT  2.4 2.137 2.52 44.303 ;
    END
  END VSS
  PIN VDD
    DIRECTION INOUT ;
    USE POWER ;
    PORT
      LAYER M5 ;
        RECT  43.092 2.151 43.212 44.289 ;
        RECT  40.392 2.151 40.512 44.289 ;
        RECT  37.692 2.151 37.812 44.289 ;
        RECT  34.992 2.151 35.112 44.289 ;
        RECT  32.292 2.151 32.412 44.289 ;
        RECT  29.592 2.151 29.712 44.289 ;
        RECT  26.892 2.151 27.012 44.289 ;
        RECT  24.192 2.151 24.312 44.289 ;
        RECT  21.492 2.151 21.612 44.289 ;
        RECT  18.792 2.151 18.912 44.289 ;
        RECT  16.092 2.151 16.212 44.289 ;
        RECT  13.392 2.151 13.512 44.289 ;
        RECT  10.692 2.151 10.812 44.289 ;
        RECT  7.992 2.151 8.112 44.289 ;
        RECT  5.292 2.151 5.412 44.289 ;
        RECT  2.592 2.151 2.712 44.289 ;
    END
  END VDD
  # OT_OBS_CLOSED layer=M5 d_um=1.536 added=271
  OBS
    LAYER RVTN ;
     RECT  2.16 2.16 44.28 2.295 ;
     RECT  2.16 2.565 44.28 2.835 ;
     RECT  2.16 3.105 44.28 3.375 ;
     RECT  2.16 3.645 44.28 3.915 ;
     RECT  2.16 4.185 44.28 4.455 ;
     RECT  2.16 4.725 44.28 4.995 ;
     RECT  2.16 5.265 44.28 5.535 ;
     RECT  2.16 5.805 44.28 6.075 ;
     RECT  2.16 6.345 44.28 6.615 ;
     RECT  2.16 6.885 44.28 7.155 ;
     RECT  2.16 7.425 44.28 7.695 ;
     RECT  2.16 7.965 44.28 8.235 ;
     RECT  2.16 8.505 44.28 8.775 ;
     RECT  2.16 9.045 44.28 9.315 ;
     RECT  2.16 9.585 44.28 9.855 ;
     RECT  2.16 10.125 44.28 10.395 ;
     RECT  2.16 10.665 44.28 10.935 ;
     RECT  2.16 11.205 44.28 11.475 ;
     RECT  2.16 11.745 44.28 12.015 ;
     RECT  2.16 12.285 44.28 12.555 ;
     RECT  2.16 12.825 44.28 13.095 ;
     RECT  2.16 13.365 44.28 13.635 ;
     RECT  2.16 13.905 44.28 14.175 ;
     RECT  2.16 14.445 44.28 14.715 ;
     RECT  2.16 14.985 44.28 15.255 ;
     RECT  2.16 15.525 44.28 15.795 ;
     RECT  2.16 16.065 44.28 16.335 ;
     RECT  2.16 16.605 44.28 16.875 ;
     RECT  2.16 17.145 44.28 17.415 ;
     RECT  2.16 17.685 44.28 17.955 ;
     RECT  2.16 18.225 44.28 18.495 ;
     RECT  2.16 18.765 44.28 19.035 ;
     RECT  2.16 19.305 44.28 19.575 ;
     RECT  2.16 19.845 44.28 20.115 ;
     RECT  2.16 20.385 44.28 20.655 ;
     RECT  2.16 20.925 44.28 21.195 ;
     RECT  2.16 21.465 44.28 21.735 ;
     RECT  2.16 22.005 44.28 22.275 ;
     RECT  2.16 22.545 44.28 22.815 ;
     RECT  2.16 23.085 44.28 23.355 ;
     RECT  2.16 23.625 44.28 23.895 ;
     RECT  2.16 24.165 44.28 24.435 ;
     RECT  2.16 24.705 44.28 24.975 ;
     RECT  2.16 25.245 44.28 25.515 ;
     RECT  2.16 25.785 44.28 26.055 ;
     RECT  2.16 26.325 44.28 26.595 ;
     RECT  2.16 26.865 44.28 27.135 ;
     RECT  2.16 27.405 44.28 27.675 ;
     RECT  2.16 27.945 44.28 28.215 ;
     RECT  2.16 28.485 44.28 28.755 ;
     RECT  2.16 29.025 44.28 29.295 ;
     RECT  2.16 29.565 44.28 29.835 ;
     RECT  2.16 30.105 44.28 30.375 ;
     RECT  2.16 30.645 44.28 30.915 ;
     RECT  2.16 31.185 44.28 31.455 ;
     RECT  2.16 31.725 44.28 31.995 ;
     RECT  2.16 32.265 44.28 32.535 ;
     RECT  2.16 32.805 44.28 33.075 ;
     RECT  2.16 33.345 44.28 33.615 ;
     RECT  2.16 33.885 44.28 34.155 ;
     RECT  2.16 34.425 44.28 34.695 ;
     RECT  2.16 34.965 44.28 35.235 ;
     RECT  2.16 35.505 44.28 35.775 ;
     RECT  2.16 36.045 44.28 36.315 ;
     RECT  2.16 36.585 44.28 36.855 ;
     RECT  2.16 37.125 44.28 37.395 ;
     RECT  2.16 37.665 44.28 37.935 ;
     RECT  2.16 38.205 44.28 38.475 ;
     RECT  2.16 38.745 44.28 39.015 ;
     RECT  2.16 39.285 44.28 39.555 ;
     RECT  2.16 39.825 44.28 40.095 ;
     RECT  2.16 40.365 44.28 40.635 ;
     RECT  2.16 40.905 44.28 41.175 ;
     RECT  2.16 41.445 44.28 41.715 ;
     RECT  2.16 41.985 44.28 42.255 ;
     RECT  2.16 42.525 44.28 42.795 ;
     RECT  2.16 43.065 44.28 43.335 ;
     RECT  2.16 43.605 44.28 43.875 ;
     RECT  2.16 44.145 44.28 44.28 ;
    LAYER RVTP ;
     RECT  2.16 2.295 44.28 2.565 ;
     RECT  2.16 2.835 44.28 3.105 ;
     RECT  2.16 3.375 44.28 3.645 ;
     RECT  2.16 3.915 44.28 4.185 ;
     RECT  2.16 4.455 44.28 4.725 ;
     RECT  2.16 4.995 44.28 5.265 ;
     RECT  2.16 5.535 44.28 5.805 ;
     RECT  2.16 6.075 44.28 6.345 ;
     RECT  2.16 6.615 44.28 6.885 ;
     RECT  2.16 7.155 44.28 7.425 ;
     RECT  2.16 7.695 44.28 7.965 ;
     RECT  2.16 8.235 44.28 8.505 ;
     RECT  2.16 8.775 44.28 9.045 ;
     RECT  2.16 9.315 44.28 9.585 ;
     RECT  2.16 9.855 44.28 10.125 ;
     RECT  2.16 10.395 44.28 10.665 ;
     RECT  2.16 10.935 44.28 11.205 ;
     RECT  2.16 11.475 44.28 11.745 ;
     RECT  2.16 12.015 44.28 12.285 ;
     RECT  2.16 12.555 44.28 12.825 ;
     RECT  2.16 13.095 44.28 13.365 ;
     RECT  2.16 13.635 44.28 13.905 ;
     RECT  2.16 14.175 44.28 14.445 ;
     RECT  2.16 14.715 44.28 14.985 ;
     RECT  2.16 15.255 44.28 15.525 ;
     RECT  2.16 15.795 44.28 16.065 ;
     RECT  2.16 16.335 44.28 16.605 ;
     RECT  2.16 16.875 44.28 17.145 ;
     RECT  2.16 17.415 44.28 17.685 ;
     RECT  2.16 17.955 44.28 18.225 ;
     RECT  2.16 18.495 44.28 18.765 ;
     RECT  2.16 19.035 44.28 19.305 ;
     RECT  2.16 19.575 44.28 19.845 ;
     RECT  2.16 20.115 44.28 20.385 ;
     RECT  2.16 20.655 44.28 20.925 ;
     RECT  2.16 21.195 44.28 21.465 ;
     RECT  2.16 21.735 44.28 22.005 ;
     RECT  2.16 22.275 44.28 22.545 ;
     RECT  2.16 22.815 44.28 23.085 ;
     RECT  2.16 23.355 44.28 23.625 ;
     RECT  2.16 23.895 44.28 24.165 ;
     RECT  2.16 24.435 44.28 24.705 ;
     RECT  2.16 24.975 44.28 25.245 ;
     RECT  2.16 25.515 44.28 25.785 ;
     RECT  2.16 26.055 44.28 26.325 ;
     RECT  2.16 26.595 44.28 26.865 ;
     RECT  2.16 27.135 44.28 27.405 ;
     RECT  2.16 27.675 44.28 27.945 ;
     RECT  2.16 28.215 44.28 28.485 ;
     RECT  2.16 28.755 44.28 29.025 ;
     RECT  2.16 29.295 44.28 29.565 ;
     RECT  2.16 29.835 44.28 30.105 ;
     RECT  2.16 30.375 44.28 30.645 ;
     RECT  2.16 30.915 44.28 31.185 ;
     RECT  2.16 31.455 44.28 31.725 ;
     RECT  2.16 31.995 44.28 32.265 ;
     RECT  2.16 32.535 44.28 32.805 ;
     RECT  2.16 33.075 44.28 33.345 ;
     RECT  2.16 33.615 44.28 33.885 ;
     RECT  2.16 34.155 44.28 34.425 ;
     RECT  2.16 34.695 44.28 34.965 ;
     RECT  2.16 35.235 44.28 35.505 ;
     RECT  2.16 35.775 44.28 36.045 ;
     RECT  2.16 36.315 44.28 36.585 ;
     RECT  2.16 36.855 44.28 37.125 ;
     RECT  2.16 37.395 44.28 37.665 ;
     RECT  2.16 37.935 44.28 38.205 ;
     RECT  2.16 38.475 44.28 38.745 ;
     RECT  2.16 39.015 44.28 39.285 ;
     RECT  2.16 39.555 44.28 39.825 ;
     RECT  2.16 40.095 44.28 40.365 ;
     RECT  2.16 40.635 44.28 40.905 ;
     RECT  2.16 41.175 44.28 41.445 ;
     RECT  2.16 41.715 44.28 41.985 ;
     RECT  2.16 42.255 44.28 42.525 ;
     RECT  2.16 42.795 44.28 43.065 ;
     RECT  2.16 43.335 44.28 43.605 ;
     RECT  2.16 43.875 44.28 44.145 ;
    LAYER M1 ;
     RECT  2.16 2.151 44.28 44.289 ;
    LAYER M2 ;
     RECT  0.103 13.95 0.203 13.968 ;
     RECT  0.103 14.796 0.203 14.814 ;
     RECT  0.103 15.804 0.203 15.822 ;
     RECT  0.103 30.726 0.463 30.744 ;
     RECT  0.463 30.726 0.499 31.212 ;
     RECT  0.103 9.09 0.535 9.108 ;
     RECT  0.103 12.906 0.535 12.924 ;
     RECT  0.499 30.186 0.535 31.212 ;
     RECT  0.535 12.456 0.635 13.194 ;
     RECT  0.571 15.228 0.671 15.624 ;
     RECT  0.535 14.148 1.723 14.166 ;
     RECT  0.535 8.856 2.16 9.684 ;
     RECT  0.535 11.376 2.16 11.394 ;
     RECT  0.635 12.456 2.16 13.086 ;
     RECT  1.723 14.148 2.16 14.472 ;
     RECT  0.671 15.606 2.16 15.624 ;
     RECT  0.103 17.19 2.16 17.208 ;
     RECT  0.535 29.916 2.16 31.212 ;
     RECT  0.535 32.346 2.16 32.364 ;
     RECT  0.103 33.156 2.16 33.174 ;
     RECT  2.16 2.151 8.023 44.289 ;
     RECT  8.023 2.151 8.347 44.334 ;
     RECT  8.347 2.151 9.347 44.37 ;
     RECT  9.347 2.151 9.851 44.334 ;
     RECT  22.855 45.891 22.999 45.909 ;
     RECT  22.999 45.891 23.071 46.332 ;
     RECT  23.071 45.891 23.099 46.404 ;
     RECT  23.099 46.386 23.207 46.404 ;
     RECT  23.215 45.621 24.503 45.639 ;
     RECT  9.851 2.151 44.28 44.289 ;
     RECT  44.28 4.698 44.735 4.788 ;
     RECT  44.28 36.126 44.771 36.144 ;
     RECT  44.735 4.77 44.807 4.788 ;
     RECT  44.28 8.316 44.843 8.874 ;
     RECT  44.28 14.796 44.879 15.984 ;
     RECT  44.879 14.796 45.059 15.354 ;
     RECT  44.28 22.626 45.059 27.126 ;
     RECT  45.059 23.436 45.095 25.074 ;
     RECT  44.28 6.696 45.311 7.218 ;
     RECT  44.28 40.446 45.311 40.464 ;
     RECT  44.28 9.936 45.347 11.304 ;
     RECT  44.28 39.096 45.347 39.114 ;
     RECT  45.311 6.696 45.383 6.714 ;
     RECT  45.059 14.796 45.383 14.814 ;
     RECT  44.28 32.346 45.383 32.904 ;
     RECT  44.28 27.918 45.419 29.394 ;
     RECT  44.28 16.956 45.455 18.324 ;
     RECT  45.059 25.83 45.563 27.126 ;
     RECT  45.095 25.02 45.599 25.074 ;
     RECT  45.563 25.83 45.599 26.586 ;
     RECT  44.28 12.906 45.635 13.428 ;
     RECT  45.319 19.386 45.635 19.404 ;
     RECT  44.28 21.816 45.635 21.834 ;
     RECT  45.059 22.626 45.635 22.644 ;
     RECT  45.095 23.436 45.635 24.228 ;
     RECT  45.599 25.83 45.635 25.848 ;
     RECT  45.419 28.8 45.635 29.394 ;
     RECT  44.28 30.456 45.635 30.744 ;
     RECT  44.28 20.196 45.671 20.214 ;
     RECT  45.635 23.436 45.671 23.454 ;
     RECT  45.635 24.21 45.671 24.228 ;
     RECT  45.419 27.918 45.671 27.936 ;
     RECT  45.635 30.456 45.671 30.708 ;
     RECT  44.28 33.966 45.671 34.524 ;
     RECT  45.347 10.71 45.707 11.304 ;
     RECT  45.599 25.02 45.707 25.038 ;
     RECT  45.635 28.8 45.707 29.124 ;
     RECT  45.671 30.69 45.707 30.708 ;
     RECT  45.383 32.508 45.707 32.904 ;
     RECT  45.707 28.8 45.743 28.944 ;
     RECT  45.671 34.506 45.743 34.524 ;
     RECT  45.707 10.71 46.283 10.926 ;
     RECT  45.743 28.8 46.319 28.818 ;
     RECT  45.707 32.85 46.319 32.904 ;
     RECT  45.347 9.936 46.355 9.954 ;
     RECT  46.283 10.836 46.355 10.926 ;
     RECT  45.455 16.956 46.355 18.018 ;
     RECT  46.319 32.85 46.355 32.868 ;
     RECT  46.291 13.914 46.391 13.932 ;
     RECT  46.355 18 46.391 18.018 ;
     RECT  46.291 18.81 46.391 18.828 ;
     RECT  44.843 8.316 46.427 8.334 ;
     RECT  46.355 10.908 46.427 10.926 ;
     RECT  46.355 16.956 46.427 17.244 ;
     RECT  46.327 21.744 46.427 21.762 ;
    LAYER M3 ;
     RECT  21.315 2.143 21.405 2.191 ;
     RECT  26.715 2.143 26.805 2.191 ;
     RECT  40.215 2.143 40.305 2.191 ;
     RECT  5.115 2.143 5.205 2.227 ;
     RECT  10.515 2.143 10.605 2.227 ;
     RECT  13.215 2.143 13.305 2.227 ;
     RECT  18.615 2.143 18.705 2.227 ;
     RECT  34.815 2.143 34.905 2.227 ;
     RECT  21.276 2.191 21.405 2.251 ;
     RECT  24.015 2.143 24.105 2.251 ;
     RECT  36.108 2.191 36.126 2.251 ;
     RECT  37.515 2.143 37.605 2.251 ;
     RECT  18.615 2.227 19.17 2.263 ;
     RECT  22.608 2.191 22.914 2.263 ;
     RECT  26.172 2.191 26.805 2.263 ;
     RECT  32.115 2.143 32.205 2.263 ;
     RECT  15.915 2.143 16.005 2.299 ;
     RECT  23.724 2.251 24.105 2.299 ;
     RECT  36.108 2.251 37.605 2.299 ;
     RECT  39.924 2.191 40.305 2.299 ;
     RECT  9.144 2.263 9.162 2.335 ;
     RECT  10.404 2.227 10.605 2.335 ;
     RECT  33.48 2.263 33.498 2.335 ;
     RECT  36.108 2.299 37.674 2.335 ;
     RECT  39.204 2.299 40.305 2.335 ;
     RECT  41.076 2.299 41.094 2.335 ;
     RECT  32.04 2.263 32.205 2.347 ;
     RECT  4.284 2.335 4.302 2.371 ;
     RECT  5.115 2.227 5.274 2.371 ;
     RECT  6.264 2.191 6.282 2.371 ;
     RECT  10.26 2.335 10.605 2.371 ;
     RECT  13.215 2.227 14.382 2.371 ;
     RECT  21.132 2.251 21.405 2.371 ;
     RECT  22.284 2.263 22.914 2.371 ;
     RECT  23.724 2.299 24.678 2.371 ;
     RECT  27.9 2.227 27.918 2.371 ;
     RECT  29.415 2.143 29.505 2.371 ;
     RECT  34.596 2.227 34.905 2.371 ;
     RECT  36.108 2.335 38.214 2.371 ;
     RECT  39.06 2.335 41.094 2.371 ;
     RECT  2.415 2.143 2.505 2.413 ;
     RECT  7.815 2.143 7.905 2.413 ;
     RECT  27.9 2.371 29.505 2.413 ;
     RECT  31.86 2.347 32.205 2.413 ;
     RECT  42.915 2.143 43.005 2.413 ;
     RECT  4.284 2.371 6.282 2.461 ;
     RECT  7.815 2.413 8.097 2.461 ;
     RECT  9 2.335 9.162 2.461 ;
     RECT  10.26 2.371 10.998 2.461 ;
     RECT  18.615 2.263 19.35 2.461 ;
     RECT  21.132 2.371 22.914 2.461 ;
     RECT  23.724 2.371 24.714 2.461 ;
     RECT  34.236 2.371 41.346 2.461 ;
     RECT  13.215 2.371 14.634 2.491 ;
     RECT  13.215 2.491 15.102 2.497 ;
     RECT  31.86 2.413 32.397 2.533 ;
     RECT  34.236 2.461 41.454 2.533 ;
     RECT  25.884 2.263 27.054 2.539 ;
     RECT  27.9 2.413 29.697 2.539 ;
     RECT  9 2.461 10.998 2.569 ;
     RECT  31.428 2.533 32.397 2.569 ;
     RECT  9 2.569 11.07 2.587 ;
     RECT  11.808 2.488 11.826 2.587 ;
     RECT  4.284 2.461 8.097 2.605 ;
     RECT  9 2.587 11.826 2.605 ;
     RECT  12.564 2.497 15.102 2.605 ;
     RECT  42.915 2.413 43.197 2.605 ;
     RECT  18.576 2.461 19.35 2.635 ;
     RECT  20.088 2.371 20.106 2.635 ;
     RECT  2.415 2.413 2.697 2.641 ;
     RECT  4.284 2.605 11.826 2.641 ;
     RECT  17.1 2.605 17.118 2.641 ;
     RECT  18.576 2.635 20.106 2.641 ;
     RECT  21.132 2.461 24.714 2.641 ;
     RECT  25.884 2.539 29.697 2.641 ;
     RECT  30.996 2.569 32.397 2.641 ;
     RECT  33.3 2.335 33.498 2.641 ;
     RECT  34.236 2.533 41.49 2.641 ;
     RECT  15.915 2.299 16.326 2.731 ;
     RECT  17.1 2.641 30.222 2.731 ;
     RECT  30.96 2.641 32.454 2.731 ;
     RECT  33.3 2.641 41.49 2.731 ;
     RECT  30.96 2.731 41.49 2.803 ;
     RECT  42.3 2.605 43.197 2.803 ;
     RECT  2.415 2.641 11.826 2.839 ;
     RECT  12.564 2.605 15.138 2.839 ;
     RECT  15.915 2.731 30.222 2.875 ;
     RECT  30.96 2.803 43.197 2.875 ;
     RECT  2.415 2.839 15.138 2.911 ;
     RECT  15.915 2.875 43.197 2.911 ;
     RECT  2.415 2.911 43.197 3.065 ;
     RECT  2.415 3.065 21.654 3.677 ;
     RECT  22.5 3.065 43.197 3.919 ;
     RECT  22.5 3.919 43.542 3.983 ;
     RECT  30.816 3.983 43.542 3.991 ;
     RECT  20.016 3.677 21.654 4.081 ;
     RECT  22.5 3.983 29.826 4.081 ;
     RECT  30.816 3.991 43.614 4.145 ;
     RECT  31.068 4.145 43.614 4.225 ;
     RECT  2.415 3.677 19.278 4.495 ;
     RECT  20.016 4.081 29.826 4.495 ;
     RECT  31.068 4.225 44.19 4.693 ;
     RECT  2.415 4.495 29.826 4.765 ;
     RECT  31.068 4.693 44.73 4.765 ;
     RECT  2.415 4.765 29.97 4.919 ;
     RECT  31.068 4.765 44.802 5.233 ;
     RECT  2.415 4.919 29.934 5.341 ;
     RECT  2.376 5.341 29.934 5.639 ;
     RECT  30.78 5.233 44.802 5.873 ;
     RECT  2.415 5.639 29.934 5.881 ;
     RECT  30.78 5.873 40.59 5.881 ;
     RECT  41.364 5.873 44.802 6.691 ;
     RECT  2.415 5.881 40.59 7.087 ;
     RECT  41.364 6.691 45.378 7.087 ;
     RECT  2.415 7.087 45.378 7.997 ;
     RECT  2.415 7.997 27.09 8.155 ;
     RECT  2.412 8.155 27.09 8.195 ;
     RECT  2.415 8.195 27.09 8.851 ;
     RECT  27.828 7.997 45.378 8.851 ;
     RECT  0.54 8.851 0.558 9.085 ;
     RECT  0.108 9.085 0.558 9.389 ;
     RECT  0.324 9.389 0.558 9.485 ;
     RECT  0.54 9.485 0.558 9.773 ;
     RECT  2.415 8.851 45.378 9.787 ;
     RECT  46.404 8.311 46.422 9.931 ;
     RECT  1.98 9.787 45.378 9.965 ;
     RECT  0.324 10.315 0.342 10.637 ;
     RECT  46.332 9.931 46.422 10.705 ;
     RECT  46.26 10.705 46.422 10.831 ;
     RECT  46.224 10.831 46.422 10.931 ;
     RECT  0.144 10.939 0.162 11.117 ;
     RECT  2.304 9.965 45.378 11.245 ;
     RECT  46.224 10.931 46.35 11.245 ;
     RECT  0.54 11.371 0.558 11.597 ;
     RECT  0.144 11.995 0.162 12.173 ;
     RECT  2.304 11.245 46.35 12.361 ;
     RECT  2.268 12.361 46.35 12.461 ;
     RECT  2.304 12.461 43.974 12.551 ;
     RECT  2.34 12.551 43.974 12.623 ;
     RECT  44.712 12.461 46.35 12.749 ;
     RECT  0.18 12.451 0.558 12.901 ;
     RECT  0.108 12.901 0.558 12.941 ;
     RECT  44.712 12.749 46.278 12.941 ;
     RECT  0.18 12.941 0.558 13.037 ;
     RECT  0.54 13.037 0.558 13.147 ;
     RECT  0.54 13.147 0.63 13.199 ;
     RECT  0.54 13.199 0.558 13.229 ;
     RECT  2.415 12.623 43.974 13.441 ;
     RECT  2.34 13.441 43.974 13.483 ;
     RECT  44.712 12.941 45.702 13.517 ;
     RECT  2.304 13.483 43.974 13.675 ;
     RECT  46.296 13.771 46.35 13.909 ;
     RECT  46.296 13.909 46.386 13.937 ;
     RECT  0.144 13.771 0.198 13.945 ;
     RECT  1.728 13.675 43.974 14.135 ;
     RECT  0.108 13.945 0.198 14.143 ;
     RECT  46.332 13.937 46.386 14.203 ;
     RECT  46.332 14.203 46.422 14.237 ;
     RECT  0.108 14.143 0.558 14.285 ;
     RECT  15.3 14.135 43.974 14.369 ;
     RECT  1.728 14.135 14.562 14.477 ;
     RECT  44.712 13.517 45.342 14.791 ;
     RECT  0.108 14.285 0.198 14.828 ;
     RECT  2.304 14.477 14.562 14.875 ;
     RECT  15.3 14.369 33.246 14.875 ;
     RECT  0.144 14.828 0.198 15.005 ;
     RECT  34.164 14.369 43.974 15.215 ;
     RECT  0.576 15.211 0.594 15.223 ;
     RECT  0.576 15.223 0.666 15.293 ;
     RECT  2.304 14.875 33.246 15.547 ;
     RECT  1.98 15.547 33.246 15.601 ;
     RECT  0.576 15.293 0.594 15.629 ;
     RECT  1.98 15.601 33.462 15.725 ;
     RECT  2.304 15.725 33.462 15.979 ;
     RECT  34.2 15.215 43.974 15.979 ;
     RECT  0.108 15.799 0.198 16.363 ;
     RECT  0.108 16.363 0.342 16.493 ;
     RECT  2.304 15.979 43.974 16.603 ;
     RECT  1.98 16.603 43.974 16.781 ;
     RECT  2.304 16.781 43.974 16.799 ;
     RECT  0.108 16.493 0.162 17.069 ;
     RECT  1.116 16.939 1.134 17.117 ;
     RECT  34.74 16.799 43.974 17.185 ;
     RECT  44.712 14.791 45.378 17.185 ;
     RECT  0.108 17.069 0.126 17.213 ;
     RECT  46.404 14.237 46.422 17.383 ;
     RECT  2.304 16.799 33.966 17.519 ;
     RECT  2.415 17.519 33.966 17.659 ;
     RECT  34.74 17.185 45.378 17.659 ;
     RECT  2.415 17.659 45.378 17.761 ;
     RECT  2.415 17.761 45.414 18.023 ;
     RECT  2.415 18.023 40.95 18.149 ;
     RECT  41.724 18.023 45.414 18.301 ;
     RECT  2.415 18.149 35.19 18.455 ;
     RECT  2.415 18.455 32.634 18.563 ;
     RECT  2.415 18.563 16.83 18.725 ;
     RECT  46.332 17.383 46.422 18.805 ;
     RECT  35.928 18.149 40.95 18.931 ;
     RECT  41.724 18.301 45.45 18.931 ;
     RECT  2.415 18.725 16.794 19.031 ;
     RECT  33.372 18.455 35.19 19.075 ;
     RECT  35.928 18.931 45.45 19.075 ;
     RECT  17.604 18.563 32.634 19.325 ;
     RECT  33.372 19.075 45.45 19.381 ;
     RECT  46.296 18.805 46.422 19.381 ;
     RECT  2.415 19.031 16.758 19.409 ;
     RECT  2.415 19.409 12.474 19.651 ;
     RECT  17.676 19.325 32.634 19.651 ;
     RECT  33.372 19.381 46.422 19.651 ;
     RECT  13.215 19.409 16.758 20.083 ;
     RECT  17.676 19.651 46.422 20.083 ;
     RECT  2.34 19.651 12.474 20.191 ;
     RECT  13.215 20.083 46.422 20.191 ;
     RECT  2.34 20.191 46.422 21.227 ;
     RECT  2.376 21.227 46.422 21.659 ;
     RECT  2.415 21.659 46.422 21.767 ;
     RECT  2.415 21.767 46.35 21.773 ;
     RECT  2.415 21.773 44.838 21.803 ;
     RECT  17.136 21.803 44.838 21.965 ;
     RECT  17.136 21.965 44.19 22.307 ;
     RECT  45.612 21.773 46.35 22.349 ;
     RECT  45.612 22.349 45.666 22.445 ;
     RECT  2.415 21.803 16.362 22.699 ;
     RECT  17.136 22.307 35.37 22.699 ;
     RECT  2.415 22.699 35.37 22.829 ;
     RECT  36.432 22.307 44.19 22.987 ;
     RECT  36.432 22.987 44.37 23.053 ;
     RECT  45.612 22.445 45.63 23.053 ;
     RECT  36.432 23.053 45.63 23.069 ;
     RECT  36.468 23.069 45.63 23.309 ;
     RECT  36.468 23.309 44.514 23.405 ;
     RECT  45.612 23.309 45.63 23.431 ;
     RECT  36.468 23.405 43.902 23.597 ;
     RECT  36.468 23.597 43.866 23.927 ;
     RECT  2.415 22.829 35.334 24.061 ;
     RECT  36.468 23.927 43.47 24.061 ;
     RECT  45.612 23.431 45.666 24.235 ;
     RECT  2.415 24.061 43.47 24.241 ;
     RECT  45.396 24.235 45.666 24.241 ;
     RECT  45.036 24.241 45.666 24.619 ;
     RECT  2.376 24.241 43.47 24.665 ;
     RECT  44.892 24.619 45.666 24.701 ;
     RECT  12.528 24.665 43.47 24.715 ;
     RECT  45.036 24.701 45.666 24.907 ;
     RECT  2.376 24.665 11.61 24.979 ;
     RECT  12.528 24.715 43.902 25.141 ;
     RECT  45.036 24.907 45.702 25.195 ;
     RECT  2.304 24.979 11.61 25.411 ;
     RECT  12.528 25.141 44.01 25.411 ;
     RECT  2.304 25.411 44.01 25.579 ;
     RECT  45.036 25.195 46.314 25.579 ;
     RECT  2.304 25.579 46.314 25.709 ;
     RECT  2.304 25.709 43.686 26.357 ;
     RECT  2.376 26.357 43.686 26.393 ;
     RECT  36.108 26.393 43.686 26.671 ;
     RECT  44.46 25.709 46.314 26.671 ;
     RECT  2.376 26.393 35.298 27.301 ;
     RECT  36.108 26.671 46.314 27.301 ;
     RECT  2.376 27.301 46.314 27.941 ;
     RECT  2.376 27.941 45.414 28.699 ;
     RECT  46.296 27.941 46.314 28.699 ;
     RECT  2.376 28.699 46.314 28.751 ;
     RECT  2.415 28.751 46.314 28.823 ;
     RECT  2.415 28.823 45.738 29.021 ;
     RECT  28.152 29.021 45.738 29.093 ;
     RECT  2.415 29.021 27.342 29.803 ;
     RECT  28.224 29.093 45.738 29.803 ;
     RECT  2.415 29.803 27.378 29.911 ;
     RECT  28.224 29.803 46.35 29.911 ;
     RECT  0.54 29.911 0.558 30.181 ;
     RECT  2.415 29.911 46.35 30.557 ;
     RECT  0.504 30.181 0.558 30.721 ;
     RECT  3.42 30.557 46.35 30.839 ;
     RECT  0.108 30.721 0.558 30.893 ;
     RECT  0.468 30.893 0.558 30.955 ;
     RECT  0.468 30.955 0.666 31.085 ;
     RECT  2.415 30.557 2.697 31.147 ;
     RECT  0.468 31.085 0.558 31.373 ;
     RECT  0.468 31.373 0.486 31.469 ;
     RECT  2.304 31.147 2.697 31.579 ;
     RECT  3.42 30.839 10.818 31.579 ;
     RECT  2.304 31.579 10.818 31.675 ;
     RECT  1.98 31.675 10.818 31.765 ;
     RECT  11.556 30.839 46.35 31.765 ;
     RECT  1.98 31.765 46.35 31.853 ;
     RECT  2.304 31.853 46.35 32.459 ;
     RECT  2.304 32.459 27.234 32.531 ;
     RECT  0.54 32.341 0.558 32.539 ;
     RECT  28.152 32.459 46.35 32.729 ;
     RECT  44.712 32.729 46.35 32.873 ;
     RECT  0.144 32.539 0.558 32.909 ;
     RECT  44.712 32.873 46.314 32.909 ;
     RECT  0.144 32.909 0.162 33.005 ;
     RECT  0.108 33.151 0.126 33.197 ;
     RECT  2.376 32.531 27.234 33.259 ;
     RECT  28.152 32.729 43.866 33.269 ;
     RECT  28.152 33.269 32.922 33.305 ;
     RECT  2.304 33.259 27.234 33.449 ;
     RECT  2.415 33.449 27.234 33.539 ;
     RECT  28.152 33.305 32.814 33.691 ;
     RECT  3.42 33.539 27.234 34.117 ;
     RECT  28.008 33.691 32.814 34.117 ;
     RECT  3.42 34.117 32.814 34.157 ;
     RECT  33.66 33.269 43.866 34.159 ;
     RECT  44.748 32.909 45.738 34.159 ;
     RECT  28.08 34.157 32.814 34.195 ;
     RECT  33.66 34.159 45.738 34.195 ;
     RECT  2.415 33.539 2.697 34.321 ;
     RECT  3.42 34.157 27.234 34.321 ;
     RECT  28.08 34.195 45.738 34.529 ;
     RECT  28.08 34.529 45.342 34.619 ;
     RECT  2.415 34.321 27.234 34.771 ;
     RECT  2.376 34.771 27.234 34.889 ;
     RECT  28.08 34.619 43.47 35.033 ;
     RECT  2.415 34.889 27.234 35.239 ;
     RECT  28.08 35.033 35.154 35.239 ;
     RECT  36 35.033 43.47 35.339 ;
     RECT  36.144 35.339 43.47 35.743 ;
     RECT  36.144 35.743 43.614 35.807 ;
     RECT  36.216 35.807 43.614 35.941 ;
     RECT  44.748 34.619 45.342 36.149 ;
     RECT  2.415 35.239 35.154 36.283 ;
     RECT  36.216 35.941 43.686 36.355 ;
     RECT  2.34 36.283 35.154 36.481 ;
     RECT  36.216 36.355 44.046 36.509 ;
     RECT  36.216 36.509 43.326 36.553 ;
     RECT  2.34 36.481 35.19 36.617 ;
     RECT  36.072 36.553 43.326 36.661 ;
     RECT  2.34 36.617 33.462 36.887 ;
     RECT  34.2 36.617 35.19 36.895 ;
     RECT  35.928 36.661 43.326 36.895 ;
     RECT  23.472 36.887 33.462 37.049 ;
     RECT  23.472 37.049 27.09 37.085 ;
     RECT  27.864 37.049 33.462 37.471 ;
     RECT  34.2 36.895 43.326 37.471 ;
     RECT  2.34 36.887 22.482 37.733 ;
     RECT  2.415 37.733 22.482 37.741 ;
     RECT  2.415 37.741 22.554 37.895 ;
     RECT  23.976 37.085 27.09 37.975 ;
     RECT  23.94 37.975 27.09 38.011 ;
     RECT  23.76 38.011 27.09 38.101 ;
     RECT  27.864 37.471 43.326 38.101 ;
     RECT  23.76 38.101 43.326 38.551 ;
     RECT  2.415 37.895 22.518 38.713 ;
     RECT  2.415 38.713 22.806 38.821 ;
     RECT  23.616 38.551 43.938 38.821 ;
     RECT  2.415 38.821 43.938 38.975 ;
     RECT  45.288 36.149 45.342 39.119 ;
     RECT  2.415 38.975 43.866 39.209 ;
     RECT  2.415 39.209 43.794 39.245 ;
     RECT  2.415 39.245 43.434 39.487 ;
     RECT  2.376 39.487 43.434 39.749 ;
     RECT  2.415 39.749 43.434 40.171 ;
     RECT  2.415 40.171 43.578 40.325 ;
     RECT  45.288 39.119 45.306 40.469 ;
     RECT  2.415 40.325 43.434 41.009 ;
     RECT  17.46 41.009 43.434 41.071 ;
     RECT  17.46 41.071 43.614 41.215 ;
     RECT  17.46 41.215 43.902 41.369 ;
     RECT  17.46 41.369 43.362 41.405 ;
     RECT  17.46 41.405 37.998 41.549 ;
     RECT  2.415 41.009 16.722 41.755 ;
     RECT  17.46 41.549 35.802 41.755 ;
     RECT  2.415 41.755 35.802 41.783 ;
     RECT  38.808 41.405 43.362 41.909 ;
     RECT  36.72 41.549 37.998 42.151 ;
     RECT  38.808 41.909 43.197 42.151 ;
     RECT  36.72 42.151 43.197 42.449 ;
     RECT  2.415 41.783 35.622 42.523 ;
     RECT  40.215 42.449 43.197 42.557 ;
     RECT  40.215 42.557 41.634 42.629 ;
     RECT  2.415 42.523 35.946 42.719 ;
     RECT  40.215 42.629 41.454 42.719 ;
     RECT  3.6 42.719 35.946 42.755 ;
     RECT  40.215 42.719 40.698 42.755 ;
     RECT  42.372 42.557 43.197 42.835 ;
     RECT  36.72 42.449 39.402 42.989 ;
     RECT  42.372 42.835 43.326 42.989 ;
     RECT  42.372 42.989 43.197 43.025 ;
     RECT  36.72 42.989 39.186 43.105 ;
     RECT  4.068 42.755 35.946 43.141 ;
     RECT  36.684 43.105 39.186 43.141 ;
     RECT  4.068 43.141 39.186 43.295 ;
     RECT  4.572 43.295 39.186 43.529 ;
     RECT  4.608 43.529 38.862 43.565 ;
     RECT  4.608 43.565 37.797 43.673 ;
     RECT  38.844 43.565 38.862 43.709 ;
     RECT  5.115 43.673 37.797 43.799 ;
     RECT  5.115 43.799 14.418 43.835 ;
     RECT  15.192 43.799 18.99 43.871 ;
     RECT  5.115 43.835 6.354 43.949 ;
     RECT  17.208 43.871 18.99 43.949 ;
     RECT  2.415 42.719 2.697 44.027 ;
     RECT  25.92 43.799 37.797 44.027 ;
     RECT  40.215 42.755 40.497 44.027 ;
     RECT  42.915 43.025 43.197 44.027 ;
     RECT  5.115 43.949 6.138 44.069 ;
     RECT  7.815 43.835 14.418 44.069 ;
     RECT  15.192 43.871 16.398 44.069 ;
     RECT  17.676 43.949 18.99 44.069 ;
     RECT  19.8 43.799 25.074 44.069 ;
     RECT  25.92 44.027 37.605 44.069 ;
     RECT  7.815 44.069 11.034 44.105 ;
     RECT  17.676 44.069 18.705 44.105 ;
     RECT  22.212 44.069 25.074 44.105 ;
     RECT  26.1 44.069 27.882 44.105 ;
     RECT  28.764 44.069 29.79 44.105 ;
     RECT  31.212 44.069 35.262 44.105 ;
     RECT  36.504 44.069 37.605 44.105 ;
     RECT  7.815 44.105 10.605 44.141 ;
     RECT  12.024 44.069 13.59 44.141 ;
     RECT  19.8 44.069 21.474 44.141 ;
     RECT  22.428 44.105 24.966 44.141 ;
     RECT  36.504 44.105 36.522 44.141 ;
     RECT  21.096 44.141 21.474 44.147 ;
     RECT  13.215 44.141 13.59 44.177 ;
     RECT  26.64 44.105 27.882 44.177 ;
     RECT  27.792 44.177 27.882 44.213 ;
     RECT  15.915 44.069 16.398 44.249 ;
     RECT  17.748 44.105 18.705 44.249 ;
     RECT  21.096 44.147 21.405 44.249 ;
     RECT  22.716 44.141 24.498 44.249 ;
     RECT  27.792 44.213 27.81 44.249 ;
     RECT  33.588 44.105 35.262 44.249 ;
     RECT  2.415 44.027 2.505 44.297 ;
     RECT  5.115 44.069 5.205 44.297 ;
     RECT  7.815 44.141 8.37 44.297 ;
     RECT  9.324 44.141 10.605 44.297 ;
     RECT  13.215 44.177 13.305 44.297 ;
     RECT  15.915 44.249 16.005 44.297 ;
     RECT  18.615 44.249 18.705 44.297 ;
     RECT  21.315 44.249 21.405 44.297 ;
     RECT  22.932 44.249 24.498 44.297 ;
     RECT  26.715 44.177 26.805 44.297 ;
     RECT  29.415 44.105 29.505 44.297 ;
     RECT  32.115 44.105 32.205 44.297 ;
     RECT  34.815 44.249 34.905 44.297 ;
     RECT  37.515 44.105 37.605 44.297 ;
     RECT  40.215 44.027 40.305 44.297 ;
     RECT  42.915 44.027 43.005 44.297 ;
     RECT  8.028 44.297 8.37 44.339 ;
     RECT  9.324 44.297 9.846 44.339 ;
     RECT  8.352 44.339 8.37 44.375 ;
     RECT  9.324 44.339 9.342 44.375 ;
     RECT  24.48 44.297 24.498 45.644 ;
     RECT  22.932 44.297 23.526 45.886 ;
     RECT  22.86 45.886 23.526 46.267 ;
     RECT  22.248 46.267 23.526 46.397 ;
     RECT  22.788 46.397 23.526 46.403 ;
     RECT  22.806 46.403 22.86 46.428 ;
     RECT  22.878 46.403 22.932 46.428 ;
     RECT  22.95 46.403 23.004 46.428 ;
     RECT  23.022 46.403 23.076 46.428 ;
     RECT  23.094 46.403 23.148 46.428 ;
     RECT  23.166 46.403 23.22 46.428 ;
     RECT  23.238 46.403 23.292 46.428 ;
     RECT  23.31 46.403 23.364 46.428 ;
     RECT  23.382 46.403 23.436 46.428 ;
     RECT  23.454 46.403 23.508 46.428 ;
    LAYER M4 ;
     RECT  0.084 9.264 0.569 9.288 ;
     RECT  0.06 9.288 0.569 9.36 ;
     RECT  0.084 9.36 0.569 9.384 ;
     RECT  0.06 9.384 0.569 9.456 ;
     RECT  0.084 9.456 0.569 9.48 ;
     RECT  0.06 9.48 0.569 9.552 ;
     RECT  0.084 9.552 0.569 9.576 ;
     RECT  0.06 9.576 0.569 9.648 ;
     RECT  0.084 9.648 0.569 9.672 ;
     RECT  0.06 9.672 0.569 9.744 ;
     RECT  0.084 9.744 0.569 9.768 ;
     RECT  0.06 9.768 0.569 9.84 ;
     RECT  0.084 9.84 0.569 9.864 ;
     RECT  0.06 9.864 0.569 9.936 ;
     RECT  0.084 9.936 0.569 9.96 ;
     RECT  0.06 9.96 0.569 10.032 ;
     RECT  0.084 10.032 0.569 10.056 ;
     RECT  0.06 10.056 0.569 10.128 ;
     RECT  0.084 10.128 0.569 10.152 ;
     RECT  0.06 10.152 0.569 10.224 ;
     RECT  0.084 10.224 0.569 10.248 ;
     RECT  0.06 10.248 0.569 10.32 ;
     RECT  0.084 10.32 0.569 10.344 ;
     RECT  0.06 10.344 0.569 10.416 ;
     RECT  0.084 10.416 0.569 10.44 ;
     RECT  0.06 10.44 0.569 10.512 ;
     RECT  0.084 10.512 0.569 10.536 ;
     RECT  0.06 10.536 0.569 10.608 ;
     RECT  0.084 10.608 0.569 10.632 ;
     RECT  0.06 10.632 0.569 10.704 ;
     RECT  0.084 10.704 0.569 10.728 ;
     RECT  0.06 10.728 0.569 10.8 ;
     RECT  0.084 10.8 0.569 10.824 ;
     RECT  0.06 10.824 0.569 10.896 ;
     RECT  0.084 10.896 0.569 10.92 ;
     RECT  0.06 10.92 0.569 10.992 ;
     RECT  0.084 10.992 0.569 11.016 ;
     RECT  0.06 11.016 0.569 11.088 ;
     RECT  0.084 11.088 0.569 11.112 ;
     RECT  0.06 11.112 0.569 11.184 ;
     RECT  0.084 11.184 0.569 11.208 ;
     RECT  0.06 11.208 0.569 11.28 ;
     RECT  0.084 11.28 0.569 11.304 ;
     RECT  0.06 11.304 0.569 11.376 ;
     RECT  0.084 11.376 0.569 11.4 ;
     RECT  0.06 11.4 0.569 11.472 ;
     RECT  0.084 11.472 0.569 11.496 ;
     RECT  0.06 11.496 0.569 11.568 ;
     RECT  0.084 11.568 0.569 11.592 ;
     RECT  0.06 11.592 0.569 11.664 ;
     RECT  0.084 11.664 0.569 11.688 ;
     RECT  0.06 11.688 0.569 11.76 ;
     RECT  0.084 11.76 0.569 11.784 ;
     RECT  0.06 11.784 0.569 11.856 ;
     RECT  0.084 11.856 0.569 11.88 ;
     RECT  0.06 11.88 0.569 11.952 ;
     RECT  0.084 11.952 0.569 11.976 ;
     RECT  0.06 11.976 0.569 12.048 ;
     RECT  0.084 12.048 0.569 12.072 ;
     RECT  0.06 12.072 0.569 12.144 ;
     RECT  0.084 12.144 0.569 12.168 ;
     RECT  0.06 12.168 0.569 12.24 ;
     RECT  0.084 12.24 0.569 12.264 ;
     RECT  0.06 12.264 0.569 12.336 ;
     RECT  0.084 12.336 0.569 12.36 ;
     RECT  0.06 12.36 0.569 12.432 ;
     RECT  0.084 12.432 0.569 12.456 ;
     RECT  0.06 12.456 0.569 12.528 ;
     RECT  0.084 12.528 0.569 12.552 ;
     RECT  0.06 12.552 0.569 12.624 ;
     RECT  0.084 12.624 0.569 12.648 ;
     RECT  0.06 12.648 0.569 12.72 ;
     RECT  0.084 12.72 0.569 12.744 ;
     RECT  0.06 12.744 0.569 12.816 ;
     RECT  0.084 12.816 0.569 12.84 ;
     RECT  0.06 12.84 0.569 12.912 ;
     RECT  0.084 12.912 0.569 12.936 ;
     RECT  0.06 12.936 0.569 13.008 ;
     RECT  0.084 13.008 0.569 13.032 ;
     RECT  0.06 13.032 0.569 13.104 ;
     RECT  0.084 13.104 0.569 13.128 ;
     RECT  0.06 13.128 0.569 13.2 ;
     RECT  0.084 13.2 0.569 13.224 ;
     RECT  0.06 13.224 0.569 13.296 ;
     RECT  0.084 13.296 0.569 13.32 ;
     RECT  0.06 13.32 0.569 13.392 ;
     RECT  0.084 13.392 0.569 13.416 ;
     RECT  0.06 13.416 0.569 13.488 ;
     RECT  0.084 13.488 0.569 13.512 ;
     RECT  0.06 13.512 0.569 13.584 ;
     RECT  0.084 13.584 0.569 13.608 ;
     RECT  0.06 13.608 0.569 13.68 ;
     RECT  0.084 13.68 0.569 13.704 ;
     RECT  0.06 13.704 0.569 13.776 ;
     RECT  0.084 13.776 0.569 13.8 ;
     RECT  0.06 13.8 0.569 13.872 ;
     RECT  0.084 13.872 0.569 13.896 ;
     RECT  0.06 13.896 0.569 13.968 ;
     RECT  0.084 13.968 0.569 13.992 ;
     RECT  0.06 13.992 0.569 14.064 ;
     RECT  0.084 14.064 0.569 14.088 ;
     RECT  0.06 14.088 0.569 14.16 ;
     RECT  0.084 14.16 0.569 14.184 ;
     RECT  0.06 14.184 0.569 14.256 ;
     RECT  0.084 14.256 0.569 14.28 ;
     RECT  0.06 14.28 0.569 14.352 ;
     RECT  0.084 14.352 0.569 14.376 ;
     RECT  0.06 14.376 0.569 14.448 ;
     RECT  0.084 14.448 0.569 14.472 ;
     RECT  0.06 14.472 0.569 14.544 ;
     RECT  0.084 14.544 0.569 14.568 ;
     RECT  0.06 14.568 0.569 14.64 ;
     RECT  0.084 14.64 0.569 14.664 ;
     RECT  0.06 14.664 0.569 14.736 ;
     RECT  0.084 14.736 0.569 14.76 ;
     RECT  0.06 14.76 0.569 14.832 ;
     RECT  0.084 14.832 0.569 14.856 ;
     RECT  0.06 14.856 0.569 14.928 ;
     RECT  0.084 14.928 0.569 14.952 ;
     RECT  0.06 14.952 0.569 15.024 ;
     RECT  0.084 15.024 0.569 15.048 ;
     RECT  0.06 15.048 0.569 15.12 ;
     RECT  0.084 15.12 0.569 15.144 ;
     RECT  0.06 15.144 0.569 15.216 ;
     RECT  0.084 15.216 0.569 15.24 ;
     RECT  0.06 15.24 0.569 15.312 ;
     RECT  0.084 15.312 0.569 15.336 ;
     RECT  0.06 15.336 0.569 15.408 ;
     RECT  0.084 15.408 0.569 15.432 ;
     RECT  0.06 15.432 0.569 15.504 ;
     RECT  0.084 15.504 0.569 15.528 ;
     RECT  0.06 15.528 0.569 15.6 ;
     RECT  0.084 15.6 0.569 15.624 ;
     RECT  0.06 15.624 0.569 15.696 ;
     RECT  0.084 15.696 0.569 15.72 ;
     RECT  0.06 15.72 0.569 15.792 ;
     RECT  0.084 15.792 0.569 15.816 ;
     RECT  0.06 15.816 0.569 15.888 ;
     RECT  0.084 15.888 0.569 15.912 ;
     RECT  0.06 15.912 0.569 15.984 ;
     RECT  0.084 15.984 0.569 16.008 ;
     RECT  0.06 16.008 0.569 16.08 ;
     RECT  0.084 16.08 0.569 16.104 ;
     RECT  0.06 16.104 0.569 16.176 ;
     RECT  0.084 16.176 0.569 16.2 ;
     RECT  0.06 16.2 0.569 16.272 ;
     RECT  0.084 16.272 0.569 16.296 ;
     RECT  0.06 16.296 0.569 16.368 ;
     RECT  0.084 16.368 0.569 16.392 ;
     RECT  0.06 16.392 0.569 16.464 ;
     RECT  0.084 16.464 0.569 16.488 ;
     RECT  0.06 16.488 0.569 16.56 ;
     RECT  0.084 16.56 0.569 16.584 ;
     RECT  0.06 16.584 0.569 16.656 ;
     RECT  0.084 16.656 0.569 16.68 ;
     RECT  0.06 16.68 0.569 16.752 ;
     RECT  0.084 16.752 0.569 16.776 ;
     RECT  0.06 16.776 0.569 16.848 ;
     RECT  0.084 16.848 0.569 16.872 ;
     RECT  0.06 16.872 0.569 16.944 ;
     RECT  0.084 16.944 0.569 16.968 ;
     RECT  0.06 16.968 0.569 17.04 ;
     RECT  0.084 17.04 0.569 17.064 ;
     RECT  0.06 17.064 0.569 17.136 ;
     RECT  0.084 17.136 0.569 17.16 ;
     RECT  0.06 17.16 0.569 17.232 ;
     RECT  0.084 17.232 0.569 17.256 ;
     RECT  0.084 30.384 0.569 30.408 ;
     RECT  0.06 30.408 0.569 30.48 ;
     RECT  0.084 30.48 0.569 30.504 ;
     RECT  0.06 30.504 0.569 30.576 ;
     RECT  0.084 30.576 0.569 30.6 ;
     RECT  0.06 30.6 0.569 30.672 ;
     RECT  0.084 30.672 0.569 30.696 ;
     RECT  0.06 30.696 0.569 30.768 ;
     RECT  0.084 30.768 0.569 30.792 ;
     RECT  0.06 30.792 0.569 30.864 ;
     RECT  0.084 30.864 0.569 30.888 ;
     RECT  0.06 30.888 0.569 30.96 ;
     RECT  0.084 30.96 0.569 30.984 ;
     RECT  0.06 30.984 0.569 31.056 ;
     RECT  0.084 31.056 0.569 31.08 ;
     RECT  0.06 31.08 0.569 31.152 ;
     RECT  0.084 31.152 0.569 31.176 ;
     RECT  0.06 31.176 0.569 31.248 ;
     RECT  0.084 31.248 0.569 31.272 ;
     RECT  0.06 31.272 0.569 31.344 ;
     RECT  0.084 31.344 0.569 31.368 ;
     RECT  0.06 31.368 0.569 31.44 ;
     RECT  0.084 31.44 0.569 31.464 ;
     RECT  0.06 31.464 0.569 31.536 ;
     RECT  0.084 31.536 0.569 31.56 ;
     RECT  0.06 31.56 0.569 31.632 ;
     RECT  0.084 31.632 0.569 31.656 ;
     RECT  0.06 31.656 0.569 31.728 ;
     RECT  0.084 31.728 0.569 31.752 ;
     RECT  0.06 31.752 0.569 31.824 ;
     RECT  0.084 31.824 0.569 31.848 ;
     RECT  0.06 31.848 0.569 31.92 ;
     RECT  0.084 31.92 0.569 31.944 ;
     RECT  0.06 31.944 0.569 32.016 ;
     RECT  0.084 32.016 0.569 32.04 ;
     RECT  0.06 32.04 0.569 32.112 ;
     RECT  0.084 32.112 0.569 32.136 ;
     RECT  0.06 32.136 0.569 32.208 ;
     RECT  0.084 32.208 0.569 32.232 ;
     RECT  0.06 32.232 0.569 32.304 ;
     RECT  0.084 32.304 0.569 32.328 ;
     RECT  0.06 32.328 0.569 32.4 ;
     RECT  0.084 32.4 0.569 32.424 ;
     RECT  0.06 32.424 0.569 32.496 ;
     RECT  0.084 32.496 0.569 32.52 ;
     RECT  0.06 32.52 0.569 32.592 ;
     RECT  0.084 32.592 0.569 32.616 ;
     RECT  0.06 32.616 0.569 32.688 ;
     RECT  0.084 32.688 0.569 32.712 ;
     RECT  0.06 32.712 0.569 32.784 ;
     RECT  0.084 32.784 0.569 32.808 ;
     RECT  0.06 32.808 0.569 32.88 ;
     RECT  0.084 32.88 0.569 32.904 ;
     RECT  0.06 32.904 0.569 32.976 ;
     RECT  0.084 32.976 0.569 33 ;
     RECT  0.06 33 0.569 33.072 ;
     RECT  0.084 33.072 0.569 33.096 ;
     RECT  0.06 33.096 0.569 33.168 ;
     RECT  0.084 33.168 0.569 33.192 ;
     RECT  0.06 33.192 0.569 33.264 ;
     RECT  0.084 33.264 0.569 33.288 ;
     RECT  0.06 33.288 0.569 33.36 ;
     RECT  0.084 33.36 0.569 33.384 ;
     RECT  2.365 5.472 2.408 5.592 ;
     RECT  2.401 8.16 2.408 8.184 ;
     RECT  0.569 9.36 2.408 17.256 ;
     RECT  2.365 21.504 2.408 21.528 ;
     RECT  2.365 24.48 2.408 24.504 ;
     RECT  2.365 27.648 2.408 27.672 ;
     RECT  0.569 30.576 2.408 33.384 ;
     RECT  2.365 37.584 2.408 37.608 ;
     RECT  2.408 2.148 2.512 44.292 ;
     RECT  2.512 2.418 2.704 44.022 ;
     RECT  2.704 3.024 2.819 5.592 ;
     RECT  2.704 6.576 2.819 8.184 ;
     RECT  2.704 21.216 2.873 21.672 ;
     RECT  2.819 3.024 2.915 5.496 ;
     RECT  2.704 9.36 3.011 19.944 ;
     RECT  2.704 36.288 3.017 36.312 ;
     RECT  2.915 3.024 3.053 4.92 ;
     RECT  2.704 24.48 3.197 26.28 ;
     RECT  3.197 24.624 3.628 26.28 ;
     RECT  2.704 34.368 3.629 34.92 ;
     RECT  2.704 37.584 3.685 41.16 ;
     RECT  3.011 9.36 3.733 18.264 ;
     RECT  2.819 6.576 3.841 7.32 ;
     RECT  3.733 8.496 3.841 18.264 ;
     RECT  2.704 27.648 3.841 28.536 ;
     RECT  3.841 27.648 3.845 29.352 ;
     RECT  3.841 6.576 3.877 18.264 ;
     RECT  3.685 37.488 3.884 41.16 ;
     RECT  2.704 42.192 3.884 42.744 ;
     RECT  3.628 26.256 3.913 26.28 ;
     RECT  3.845 27.648 3.913 28.296 ;
     RECT  3.884 37.488 3.925 42.744 ;
     RECT  3.053 4.896 3.949 4.92 ;
     RECT  2.704 30.528 3.949 33.096 ;
     RECT  3.949 4.896 4.021 5.544 ;
     RECT  3.877 6.528 4.021 18.264 ;
     RECT  3.925 37.488 4.025 42.84 ;
     RECT  2.873 21.36 4.079 21.672 ;
     RECT  4.025 37.584 4.097 42.84 ;
     RECT  4.079 21.312 4.117 21.672 ;
     RECT  2.704 23.232 4.117 23.256 ;
     RECT  4.021 4.896 4.237 18.264 ;
     RECT  3.011 19.344 4.237 19.944 ;
     RECT  4.237 4.896 4.345 19.944 ;
     RECT  4.345 4.8 4.381 19.944 ;
     RECT  4.117 21.312 4.453 23.256 ;
     RECT  3.628 24.624 4.453 24.888 ;
     RECT  3.053 3.024 4.489 3.72 ;
     RECT  3.845 29.328 4.489 29.352 ;
     RECT  3.949 30.528 4.489 33.144 ;
     RECT  3.629 34.896 4.633 34.92 ;
     RECT  3.913 26.256 4.693 28.296 ;
     RECT  4.489 2.832 4.705 3.72 ;
     RECT  4.381 4.704 4.705 19.944 ;
     RECT  4.693 25.968 4.885 28.296 ;
     RECT  4.489 29.328 4.885 33.144 ;
     RECT  4.705 2.832 5.108 19.944 ;
     RECT  4.453 21.312 5.108 24.888 ;
     RECT  4.885 25.968 5.108 33.144 ;
     RECT  4.633 34.464 5.108 34.92 ;
     RECT  4.097 37.584 5.108 42.552 ;
     RECT  5.108 2.148 5.212 44.292 ;
     RECT  5.212 2.418 5.404 44.022 ;
     RECT  5.404 22.848 5.465 24.984 ;
     RECT  5.404 37.008 5.555 37.608 ;
     RECT  5.404 38.784 5.555 40.584 ;
     RECT  5.465 23.184 5.609 24.984 ;
     RECT  5.404 2.88 5.753 21.672 ;
     RECT  5.404 28.8 5.789 35.448 ;
     RECT  5.555 39.84 5.789 40.584 ;
     RECT  5.404 26.256 5.897 27.72 ;
     RECT  5.789 40.08 5.897 40.584 ;
     RECT  5.609 23.184 5.933 24.648 ;
     RECT  5.555 38.784 5.933 38.808 ;
     RECT  5.933 23.616 6.149 24.648 ;
     RECT  5.404 41.568 6.365 42.888 ;
     RECT  5.404 43.92 6.365 43.944 ;
     RECT  5.789 28.8 6.563 28.824 ;
     RECT  5.789 30.288 6.577 35.448 ;
     RECT  5.555 37.008 6.577 37.032 ;
     RECT  6.577 30.288 6.757 37.032 ;
     RECT  5.753 3.888 6.764 21.672 ;
     RECT  6.793 38.16 7.117 38.184 ;
     RECT  5.897 26.256 7.153 27.336 ;
     RECT  6.149 24.624 7.225 24.648 ;
     RECT  6.149 23.616 7.297 23.64 ;
     RECT  6.757 28.944 7.369 37.032 ;
     RECT  7.117 38.112 7.369 38.184 ;
     RECT  5.897 40.08 7.369 40.104 ;
     RECT  6.365 41.568 7.369 42.504 ;
     RECT  7.369 28.944 7.405 38.184 ;
     RECT  7.405 28.944 7.436 38.328 ;
     RECT  6.764 3.888 7.477 21.912 ;
     RECT  7.297 23.376 7.477 23.64 ;
     RECT  7.153 25.824 7.621 27.336 ;
     RECT  7.436 28.944 7.729 38.76 ;
     RECT  5.753 2.88 7.808 2.904 ;
     RECT  7.477 3.888 7.808 23.64 ;
     RECT  7.225 24.624 7.808 24.696 ;
     RECT  7.621 25.824 7.808 27.72 ;
     RECT  7.729 28.944 7.808 38.808 ;
     RECT  7.369 40.08 7.808 42.504 ;
     RECT  7.808 2.148 7.912 44.292 ;
     RECT  7.912 2.418 8.104 44.022 ;
     RECT  8.104 3.888 8.273 7.416 ;
     RECT  8.104 8.544 8.381 19.848 ;
     RECT  8.381 17.664 8.387 19.848 ;
     RECT  8.104 21.216 8.572 37.704 ;
     RECT  8.104 40.944 8.627 43.944 ;
     RECT  8.104 38.736 8.668 39.912 ;
     RECT  8.627 41.712 8.716 43.944 ;
     RECT  8.273 3.888 8.777 5.688 ;
     RECT  8.716 41.712 9.101 43.176 ;
     RECT  8.777 4.56 9.313 5.688 ;
     RECT  8.273 6.816 9.313 7.416 ;
     RECT  9.101 42.192 9.389 43.176 ;
     RECT  8.572 25.44 9.421 37.704 ;
     RECT  8.668 38.736 9.421 39.864 ;
     RECT  8.381 8.544 9.493 16.68 ;
     RECT  8.387 17.664 9.493 19.368 ;
     RECT  8.104 2.88 9.565 2.904 ;
     RECT  9.313 4.56 9.601 7.416 ;
     RECT  9.493 8.544 9.601 19.368 ;
     RECT  8.572 21.216 9.74 24.168 ;
     RECT  9.421 25.44 9.74 39.864 ;
     RECT  9.74 21.216 9.997 39.864 ;
     RECT  9.997 20.352 10.213 39.864 ;
     RECT  9.565 2.88 10.249 3.432 ;
     RECT  9.601 4.56 10.249 19.368 ;
     RECT  10.249 2.88 10.285 19.368 ;
     RECT  10.213 20.352 10.285 40.44 ;
     RECT  9.389 42.192 10.309 42.936 ;
     RECT  10.285 2.88 10.349 40.44 ;
     RECT  10.349 2.256 10.508 40.44 ;
     RECT  10.309 41.568 10.508 42.936 ;
     RECT  10.285 43.92 10.508 43.944 ;
     RECT  10.508 2.148 10.612 44.292 ;
     RECT  10.612 2.418 10.804 44.022 ;
     RECT  10.804 32.976 10.865 37.656 ;
     RECT  10.804 2.592 10.931 27.384 ;
     RECT  10.931 2.592 10.937 21.672 ;
     RECT  10.931 23.088 10.973 27.384 ;
     RECT  10.973 24.624 11.045 27.384 ;
     RECT  10.804 42 11.117 44.022 ;
     RECT  10.865 32.976 11.171 34.392 ;
     RECT  11.171 32.976 11.197 33.576 ;
     RECT  10.937 4.752 11.225 21.672 ;
     RECT  10.804 29.76 11.369 31.896 ;
     RECT  11.045 27.36 11.441 27.384 ;
     RECT  10.865 35.808 11.441 37.656 ;
     RECT  11.441 35.856 11.507 37.656 ;
     RECT  11.045 24.624 11.621 26.376 ;
     RECT  11.117 42.288 11.749 44.022 ;
     RECT  10.973 23.088 11.765 23.112 ;
     RECT  11.749 42.288 11.795 44.136 ;
     RECT  10.937 2.592 11.797 3.192 ;
     RECT  11.225 4.752 11.837 21.336 ;
     RECT  10.804 38.688 11.837 40.968 ;
     RECT  11.795 42.288 11.873 42.792 ;
     RECT  11.369 29.76 11.905 31.224 ;
     RECT  11.507 36.336 11.905 37.656 ;
     RECT  11.837 38.688 11.905 40.92 ;
     RECT  11.621 24.624 11.945 24.648 ;
     RECT  11.621 25.632 11.945 26.376 ;
     RECT  11.945 26.064 12.049 26.376 ;
     RECT  11.197 33.024 12.193 33.576 ;
     RECT  12.193 33.024 12.229 34.2 ;
     RECT  11.833 28.224 12.301 28.296 ;
     RECT  11.905 29.328 12.301 31.224 ;
     RECT  12.229 32.736 12.301 34.2 ;
     RECT  12.301 32.736 12.481 34.824 ;
     RECT  12.301 28.224 12.589 31.224 ;
     RECT  12.481 32.304 12.589 34.824 ;
     RECT  11.797 2.496 12.62 3.192 ;
     RECT  12.049 26.064 12.805 27.192 ;
     RECT  12.121 22.32 12.841 22.344 ;
     RECT  11.905 36.336 12.841 40.92 ;
     RECT  11.873 42.288 12.841 42.744 ;
     RECT  11.837 7.392 12.913 21.336 ;
     RECT  12.841 22.32 12.913 22.968 ;
     RECT  12.62 2.496 12.985 3.576 ;
     RECT  11.837 4.752 12.985 6.072 ;
     RECT  12.913 7.392 13.021 22.968 ;
     RECT  12.841 36.336 13.021 42.744 ;
     RECT  13.021 7.152 13.045 22.968 ;
     RECT  12.301 24.288 13.045 24.312 ;
     RECT  13.045 7.152 13.201 24.312 ;
     RECT  12.985 2.496 13.208 6.072 ;
     RECT  13.201 7.104 13.208 24.312 ;
     RECT  12.805 26.064 13.208 27.24 ;
     RECT  12.589 28.224 13.208 34.824 ;
     RECT  13.021 36.192 13.208 42.744 ;
     RECT  11.795 44.112 13.208 44.136 ;
     RECT  13.208 2.148 13.312 44.292 ;
     RECT  13.312 2.256 13.504 44.136 ;
     RECT  13.504 22.224 13.601 34.776 ;
     RECT  13.504 4.128 13.619 21.24 ;
     RECT  13.619 4.128 13.667 18.984 ;
     RECT  13.601 23.808 13.781 34.776 ;
     RECT  13.619 20.4 13.817 21.24 ;
     RECT  13.504 39.84 13.889 41.688 ;
     RECT  13.504 2.256 14.099 2.52 ;
     RECT  13.667 4.176 14.099 18.984 ;
     RECT  14.099 4.176 14.105 4.68 ;
     RECT  14.099 5.712 14.113 18.984 ;
     RECT  13.781 23.808 14.285 29.352 ;
     RECT  13.504 42.72 14.285 42.744 ;
     RECT  13.504 44.016 14.285 44.136 ;
     RECT  13.601 22.224 14.428 22.728 ;
     RECT  14.113 6.624 14.429 18.984 ;
     RECT  13.889 40.128 14.429 41.688 ;
     RECT  14.429 7.2 14.605 18.984 ;
     RECT  14.605 7.2 14.677 19.08 ;
     RECT  13.817 20.4 14.677 21.192 ;
     RECT  13.781 30.384 14.713 34.776 ;
     RECT  14.285 23.904 14.717 29.352 ;
     RECT  14.677 7.2 14.723 21.192 ;
     RECT  14.723 19.968 14.857 21.192 ;
     RECT  14.428 22.224 14.857 22.344 ;
     RECT  14.723 7.2 14.933 18.888 ;
     RECT  13.504 37.584 15.001 38.712 ;
     RECT  14.099 2.496 15.073 2.52 ;
     RECT  14.105 4.416 15.217 4.68 ;
     RECT  14.717 23.904 15.253 25.752 ;
     RECT  15.217 4.416 15.325 5.112 ;
     RECT  15.217 43.008 15.325 43.032 ;
     RECT  14.285 44.112 15.325 44.136 ;
     RECT  15.325 4.416 15.356 5.592 ;
     RECT  15.001 37.104 15.356 38.712 ;
     RECT  14.429 40.128 15.356 41.64 ;
     RECT  14.857 19.968 15.397 22.344 ;
     RECT  15.253 23.52 15.397 25.752 ;
     RECT  14.933 16.704 15.781 18.888 ;
     RECT  15.397 19.968 15.781 25.752 ;
     RECT  14.717 26.88 15.781 29.352 ;
     RECT  15.781 16.704 15.829 29.352 ;
     RECT  14.713 30.384 15.829 35.256 ;
     RECT  15.073 2.496 15.908 2.856 ;
     RECT  15.356 4.416 15.908 5.832 ;
     RECT  14.933 7.2 15.908 15.624 ;
     RECT  15.829 16.704 15.908 35.256 ;
     RECT  15.356 37.104 15.908 41.64 ;
     RECT  15.325 43.008 15.908 44.136 ;
     RECT  15.908 2.148 16.012 44.292 ;
     RECT  16.012 2.418 16.204 44.136 ;
     RECT  16.204 24.912 16.355 44.136 ;
     RECT  16.355 40.368 16.492 44.136 ;
     RECT  16.492 41.904 16.517 44.136 ;
     RECT  16.204 5.04 16.691 15.576 ;
     RECT  16.691 5.04 16.697 5.832 ;
     RECT  16.204 2.832 16.805 2.856 ;
     RECT  16.691 6.912 16.841 15.576 ;
     RECT  16.841 6.912 16.877 12.024 ;
     RECT  16.841 13.248 16.931 15.576 ;
     RECT  16.204 20.304 16.931 22.728 ;
     RECT  16.877 7.104 16.985 12.024 ;
     RECT  16.355 24.912 17.021 39.24 ;
     RECT  16.931 13.248 17.057 14.424 ;
     RECT  16.517 41.904 17.057 42.888 ;
     RECT  17.021 24.912 17.129 38.808 ;
     RECT  16.931 15.456 17.305 15.576 ;
     RECT  16.985 7.104 17.309 11.784 ;
     RECT  17.309 7.92 17.345 11.784 ;
     RECT  16.492 40.368 17.345 40.728 ;
     RECT  17.345 40.704 17.381 40.728 ;
     RECT  17.345 8.928 17.411 11.784 ;
     RECT  17.411 9.216 17.417 11.784 ;
     RECT  16.204 16.8 17.453 17.736 ;
     RECT  17.057 13.392 17.561 14.424 ;
     RECT  16.204 18.72 17.593 18.888 ;
     RECT  17.593 18.72 17.629 19.32 ;
     RECT  16.931 20.304 17.629 22.488 ;
     RECT  17.453 17.04 17.773 17.736 ;
     RECT  17.629 18.72 17.773 22.488 ;
     RECT  17.129 24.912 17.773 35.496 ;
     RECT  16.697 5.808 17.845 5.832 ;
     RECT  17.773 17.04 18.205 22.488 ;
     RECT  17.989 40.944 18.241 40.968 ;
     RECT  17.773 24.096 18.325 35.496 ;
     RECT  17.129 36.576 18.325 38.808 ;
     RECT  16.204 3.888 18.349 3.912 ;
     RECT  18.205 17.04 18.421 22.872 ;
     RECT  18.325 24.096 18.421 38.808 ;
     RECT  18.349 3.072 18.565 3.912 ;
     RECT  17.417 10.416 18.565 11.784 ;
     RECT  17.561 13.392 18.565 14.232 ;
     RECT  18.421 17.04 18.565 38.808 ;
     RECT  18.565 2.496 18.608 3.912 ;
     RECT  17.845 5.472 18.608 5.832 ;
     RECT  17.345 7.92 18.608 7.944 ;
     RECT  17.417 9.216 18.608 9.24 ;
     RECT  18.565 10.416 18.608 14.232 ;
     RECT  17.305 15.456 18.608 15.768 ;
     RECT  18.565 16.896 18.608 38.808 ;
     RECT  18.241 40.944 18.608 41.4 ;
     RECT  17.057 42.576 18.608 42.888 ;
     RECT  16.517 43.92 18.608 44.136 ;
     RECT  18.608 2.148 18.712 44.292 ;
     RECT  18.712 2.256 18.904 44.136 ;
     RECT  18.904 38.688 19.001 42.6 ;
     RECT  18.904 5.616 19.037 17.976 ;
     RECT  19.037 5.616 19.091 17.64 ;
     RECT  18.904 19.248 19.091 29.352 ;
     RECT  18.904 30.384 19.145 34.728 ;
     RECT  19.091 8.544 19.181 17.64 ;
     RECT  19.091 19.248 19.181 27.192 ;
     RECT  18.904 2.256 19.187 2.664 ;
     RECT  19.145 30.384 19.217 34.68 ;
     RECT  19.181 21.168 19.253 27.192 ;
     RECT  19.217 30.384 19.468 34.344 ;
     RECT  19.001 38.688 19.469 42.072 ;
     RECT  19.091 5.616 19.475 7.416 ;
     RECT  19.181 19.248 19.564 20.184 ;
     RECT  19.469 38.688 19.909 41.64 ;
     RECT  19.909 38.16 19.957 41.64 ;
     RECT  19.957 38.016 20.044 41.64 ;
     RECT  19.181 9.024 20.045 9.96 ;
     RECT  19.253 24.72 20.108 27.192 ;
     RECT  19.091 28.272 20.108 29.352 ;
     RECT  20.108 24.72 20.185 29.352 ;
     RECT  19.468 30.384 20.185 34.2 ;
     RECT  19.253 21.168 20.189 23.16 ;
     RECT  20.044 39.696 20.225 41.64 ;
     RECT  18.904 36 20.257 37.032 ;
     RECT  20.044 38.016 20.257 38.712 ;
     RECT  19.181 10.992 20.293 17.64 ;
     RECT  20.257 36 20.293 38.712 ;
     RECT  20.045 9.024 20.365 9.912 ;
     RECT  20.293 10.992 20.473 17.688 ;
     RECT  19.475 5.856 20.509 7.416 ;
     RECT  20.365 8.496 20.509 9.912 ;
     RECT  20.473 10.896 20.509 17.688 ;
     RECT  19.564 19.248 20.509 19.944 ;
     RECT  20.509 5.856 20.581 9.912 ;
     RECT  20.581 5.472 20.797 9.912 ;
     RECT  20.509 10.896 20.905 19.944 ;
     RECT  20.189 21.168 20.905 22.248 ;
     RECT  20.797 5.04 20.941 9.912 ;
     RECT  20.941 4.464 21.068 9.912 ;
     RECT  19.187 2.64 21.109 2.664 ;
     RECT  21.109 2.256 21.308 2.664 ;
     RECT  21.068 4.08 21.308 9.912 ;
     RECT  20.905 10.896 21.308 22.248 ;
     RECT  20.401 23.616 21.308 23.64 ;
     RECT  20.185 24.72 21.308 34.2 ;
     RECT  20.293 35.184 21.308 38.712 ;
     RECT  20.225 39.696 21.308 40.968 ;
     RECT  20.965 42.192 21.308 42.216 ;
     RECT  18.904 44.112 21.308 44.136 ;
     RECT  21.308 2.148 21.412 44.292 ;
     RECT  21.412 2.418 21.604 44.136 ;
     RECT  21.604 28.272 21.809 37.032 ;
     RECT  21.604 26.016 21.881 27.144 ;
     RECT  21.604 38.496 22.061 38.712 ;
     RECT  21.604 6.672 22.067 9.384 ;
     RECT  21.604 10.368 22.097 18.744 ;
     RECT  21.809 29.328 22.169 37.032 ;
     RECT  18.085 46.368 22.237 46.392 ;
     RECT  21.881 26.304 22.241 27.144 ;
     RECT  21.604 5.04 22.277 5.496 ;
     RECT  22.237 46.272 22.277 46.392 ;
     RECT  22.169 33.6 22.349 37.032 ;
     RECT  21.604 40.416 22.355 44.136 ;
     RECT  22.349 33.6 22.385 33.72 ;
     RECT  22.277 5.472 22.597 5.496 ;
     RECT  22.067 6.672 22.597 9.288 ;
     RECT  21.604 2.496 22.601 2.568 ;
     RECT  22.349 34.752 22.601 37.032 ;
     RECT  22.097 10.8 22.633 18.744 ;
     RECT  21.604 24.48 22.669 24.744 ;
     RECT  22.061 38.688 22.691 38.712 ;
     RECT  22.601 36.528 22.693 37.032 ;
     RECT  22.633 10.8 22.705 18.84 ;
     RECT  22.601 34.752 22.709 35.448 ;
     RECT  22.705 10.8 22.741 19.368 ;
     RECT  21.604 20.64 22.741 21.672 ;
     RECT  22.669 24.48 22.741 25.272 ;
     RECT  22.741 10.8 22.789 21.672 ;
     RECT  22.277 46.272 22.817 46.296 ;
     RECT  22.597 5.472 22.853 9.288 ;
     RECT  22.355 40.992 22.925 44.136 ;
     RECT  22.885 45.888 23.033 45.912 ;
     RECT  22.241 26.304 23.101 26.328 ;
     RECT  22.169 29.328 23.245 32.52 ;
     RECT  22.385 33.6 23.245 33.624 ;
     RECT  23.101 26.256 23.317 26.328 ;
     RECT  23.317 26.256 23.497 26.904 ;
     RECT  22.601 2.496 23.713 2.52 ;
     RECT  23.713 2.256 23.749 2.52 ;
     RECT  22.957 23.04 23.821 23.064 ;
     RECT  22.741 24.192 23.821 25.272 ;
     RECT  23.821 23.04 23.893 25.272 ;
     RECT  23.497 26.256 23.893 27.144 ;
     RECT  21.809 28.272 23.893 28.296 ;
     RECT  23.245 29.328 23.893 33.624 ;
     RECT  23.749 2.256 24.008 3.048 ;
     RECT  22.853 5.52 24.008 5.544 ;
     RECT  22.853 6.624 24.008 9.096 ;
     RECT  22.789 10.8 24.008 18.84 ;
     RECT  22.789 20.112 24.008 21.672 ;
     RECT  23.893 23.04 24.008 27.144 ;
     RECT  23.893 28.272 24.008 33.624 ;
     RECT  22.709 34.752 24.008 35.256 ;
     RECT  22.693 36.528 24.008 37.368 ;
     RECT  22.925 41.232 24.008 44.136 ;
     RECT  24.008 2.148 24.112 44.292 ;
     RECT  24.112 2.304 24.304 44.136 ;
     RECT  24.304 44.112 24.365 44.136 ;
     RECT  24.304 42.768 24.419 43.08 ;
     RECT  24.304 36.48 24.467 37.272 ;
     RECT  24.419 43.008 24.467 43.08 ;
     RECT  24.304 2.304 24.473 9.24 ;
     RECT  24.473 2.304 24.509 5.736 ;
     RECT  24.509 3.936 24.581 5.736 ;
     RECT  24.304 38.784 24.617 39.336 ;
     RECT  24.467 43.008 24.761 43.032 ;
     RECT  24.617 39.312 24.977 39.336 ;
     RECT  24.304 21.456 25.157 33.624 ;
     RECT  25.157 21.648 25.229 33.624 ;
     RECT  25.229 23.04 25.301 33.624 ;
     RECT  25.301 24.192 25.405 33.624 ;
     RECT  24.304 34.752 25.405 35.256 ;
     RECT  24.467 36.48 25.573 37.08 ;
     RECT  24.473 6.816 25.585 9.24 ;
     RECT  24.509 2.304 25.621 2.904 ;
     RECT  24.581 3.936 25.621 4.68 ;
     RECT  24.581 5.712 25.621 5.736 ;
     RECT  25.621 2.304 25.625 5.736 ;
     RECT  25.405 24.192 25.729 35.256 ;
     RECT  25.573 36.48 25.729 37.656 ;
     RECT  25.229 21.648 25.733 21.672 ;
     RECT  25.585 6.768 25.801 9.24 ;
     RECT  24.304 10.32 25.801 20.376 ;
     RECT  25.801 6.768 26.125 20.376 ;
     RECT  26.125 6.768 26.161 20.904 ;
     RECT  26.089 39.024 26.197 39.048 ;
     RECT  25.621 41.52 26.197 41.544 ;
     RECT  26.197 39.024 26.405 39.144 ;
     RECT  25.669 40.416 26.581 40.44 ;
     RECT  26.197 41.52 26.581 42.12 ;
     RECT  25.625 2.304 26.708 5.064 ;
     RECT  26.161 6.528 26.708 20.904 ;
     RECT  25.301 23.04 26.708 23.064 ;
     RECT  25.729 24.192 26.708 37.656 ;
     RECT  26.405 39.024 26.708 39.288 ;
     RECT  26.581 40.416 26.708 42.12 ;
     RECT  26.089 43.344 26.708 43.368 ;
     RECT  26.708 2.148 26.812 44.292 ;
     RECT  26.812 2.418 27.004 44.022 ;
     RECT  27.004 24.384 27.155 34.392 ;
     RECT  27.004 2.418 27.347 21.672 ;
     RECT  27.347 2.418 27.497 18.408 ;
     RECT  27.497 2.418 27.777 17.736 ;
     RECT  27.777 2.418 27.845 9.816 ;
     RECT  27.155 24.384 27.857 34.152 ;
     RECT  27.845 2.256 27.929 9.816 ;
     RECT  27.004 41.376 27.929 43.368 ;
     RECT  27.929 2.544 28.001 9.816 ;
     RECT  27.347 19.392 28.033 21.672 ;
     RECT  27.004 22.8 28.033 23.064 ;
     RECT  28.001 2.592 28.037 9.816 ;
     RECT  27.004 35.376 28.069 36.936 ;
     RECT  28.037 2.592 28.073 7.464 ;
     RECT  28.033 19.392 28.073 23.064 ;
     RECT  27.857 24.384 28.105 33.672 ;
     RECT  27.004 39.792 28.141 40.104 ;
     RECT  28.069 35.376 28.213 37.032 ;
     RECT  27.929 41.424 28.249 43.368 ;
     RECT  28.073 19.776 28.285 23.064 ;
     RECT  28.105 24.192 28.285 33.672 ;
     RECT  27.004 38.64 28.357 38.76 ;
     RECT  28.141 39.792 28.357 40.392 ;
     RECT  28.213 35.376 28.393 37.08 ;
     RECT  28.357 38.64 28.393 40.392 ;
     RECT  28.393 35.376 28.453 40.392 ;
     RECT  27.777 10.8 28.465 17.736 ;
     RECT  28.249 41.424 28.753 43.656 ;
     RECT  28.037 8.496 28.885 9.816 ;
     RECT  28.465 10.8 28.885 18.552 ;
     RECT  28.453 34.704 28.897 40.392 ;
     RECT  28.753 41.424 28.897 43.944 ;
     RECT  28.073 3.6 29.041 7.464 ;
     RECT  28.885 8.496 29.041 18.552 ;
     RECT  28.285 19.776 29.249 33.672 ;
     RECT  28.897 34.704 29.249 43.944 ;
     RECT  28.073 2.592 29.257 2.616 ;
     RECT  29.041 3.6 29.257 18.552 ;
     RECT  29.257 2.592 29.408 18.552 ;
     RECT  29.249 19.776 29.408 43.944 ;
     RECT  29.408 2.148 29.512 44.292 ;
     RECT  29.512 2.418 29.704 44.022 ;
     RECT  29.704 17.664 29.765 38.712 ;
     RECT  29.704 11.952 29.801 16.44 ;
     RECT  29.765 24.24 29.843 38.712 ;
     RECT  29.704 10.176 29.945 10.296 ;
     RECT  29.765 17.664 29.945 23.064 ;
     RECT  29.704 7.92 30.233 9 ;
     RECT  29.704 2.88 30.467 3.96 ;
     RECT  29.843 38.688 30.485 38.712 ;
     RECT  29.945 17.664 30.557 22.872 ;
     RECT  29.801 12.336 30.665 16.44 ;
     RECT  30.467 2.88 30.755 3.432 ;
     RECT  30.233 8.016 30.809 9 ;
     RECT  29.704 5.04 30.841 5.064 ;
     RECT  30.809 8.688 30.841 9 ;
     RECT  29.704 39.888 30.845 41.736 ;
     RECT  29.704 42.768 30.845 43.656 ;
     RECT  30.845 40.992 30.877 41.736 ;
     RECT  30.845 42.768 30.877 43.176 ;
     RECT  29.945 10.272 30.989 10.296 ;
     RECT  29.843 24.24 31.525 37.032 ;
     RECT  30.557 17.664 31.633 21.624 ;
     RECT  31.633 17.664 31.669 21.672 ;
     RECT  30.841 5.04 31.705 5.688 ;
     RECT  31.669 17.424 31.705 21.672 ;
     RECT  30.557 22.848 31.705 22.872 ;
     RECT  30.755 2.88 31.849 2.904 ;
     RECT  31.705 4.464 31.861 6.264 ;
     RECT  31.861 4.464 31.885 7.176 ;
     RECT  30.841 8.688 31.885 9.096 ;
     RECT  30.665 13.152 31.885 16.44 ;
     RECT  31.453 38.352 31.957 38.376 ;
     RECT  30.845 39.888 31.957 39.912 ;
     RECT  31.885 4.464 31.993 9.096 ;
     RECT  31.885 10.896 31.993 10.92 ;
     RECT  31.993 4.224 32.101 9.096 ;
     RECT  31.993 10.896 32.101 11.256 ;
     RECT  31.849 2.352 32.108 2.904 ;
     RECT  32.101 4.224 32.108 11.256 ;
     RECT  31.885 12.528 32.108 16.44 ;
     RECT  31.705 17.424 32.108 22.872 ;
     RECT  31.525 23.952 32.108 37.032 ;
     RECT  31.957 38.352 32.108 39.912 ;
     RECT  30.877 40.992 32.108 43.176 ;
     RECT  32.108 2.148 32.212 44.292 ;
     RECT  32.212 2.352 32.404 44.022 ;
     RECT  32.404 34.272 32.501 39.384 ;
     RECT  32.404 41.664 32.537 43.32 ;
     RECT  32.404 26.544 32.573 33.288 ;
     RECT  32.537 41.952 32.573 43.32 ;
     RECT  32.404 2.352 32.717 16.008 ;
     RECT  32.717 2.352 32.723 14.664 ;
     RECT  32.404 17.856 32.897 17.88 ;
     RECT  32.573 26.64 32.933 33.288 ;
     RECT  32.501 36.048 33.107 39.384 ;
     RECT  33.107 36.048 33.113 39.24 ;
     RECT  32.573 42.192 33.113 43.32 ;
     RECT  32.723 2.352 33.149 5.688 ;
     RECT  33.113 36.24 33.185 39.24 ;
     RECT  33.113 42.192 33.185 42.216 ;
     RECT  33.185 36.24 33.221 36.552 ;
     RECT  32.723 6.816 33.257 14.664 ;
     RECT  33.149 2.352 33.329 3.96 ;
     RECT  33.149 4.944 33.337 5.688 ;
     RECT  32.404 23.952 33.433 25.032 ;
     RECT  33.221 36.24 33.491 36.504 ;
     RECT  33.433 23.856 33.505 25.032 ;
     RECT  33.185 37.584 33.509 39.24 ;
     RECT  33.509 37.584 33.532 39.144 ;
     RECT  32.717 15.84 33.541 16.008 ;
     RECT  32.404 19.056 33.541 19.8 ;
     RECT  32.404 20.976 33.541 22.872 ;
     RECT  32.933 26.64 33.581 33.192 ;
     RECT  33.532 37.584 33.581 39.096 ;
     RECT  33.541 19.056 33.596 22.872 ;
     RECT  33.329 2.784 33.617 3.96 ;
     RECT  33.257 6.816 33.653 14.424 ;
     RECT  33.491 36.24 33.653 36.456 ;
     RECT  32.404 40.512 33.653 40.536 ;
     RECT  33.596 18.72 33.683 22.872 ;
     RECT  33.541 15.84 33.721 16.584 ;
     RECT  33.113 43.296 33.725 43.32 ;
     RECT  33.721 15.84 33.781 16.68 ;
     RECT  33.683 18.816 33.793 22.872 ;
     RECT  33.505 23.856 33.793 25.08 ;
     RECT  33.337 4.944 33.797 5.208 ;
     RECT  33.781 15.84 33.827 16.824 ;
     RECT  33.827 16.32 33.829 16.824 ;
     RECT  33.793 18.816 33.829 25.08 ;
     RECT  33.581 26.736 33.901 33.192 ;
     RECT  32.501 34.272 33.901 34.728 ;
     RECT  33.617 3.12 34.117 3.96 ;
     RECT  33.653 6.864 34.261 14.424 ;
     RECT  34.117 3.12 34.621 4.248 ;
     RECT  34.261 6.864 34.657 14.712 ;
     RECT  33.829 18.816 34.693 25.56 ;
     RECT  33.901 26.736 34.693 34.728 ;
     RECT  34.621 3.072 34.808 4.248 ;
     RECT  34.729 5.232 34.808 5.256 ;
     RECT  34.657 6.816 34.808 14.712 ;
     RECT  33.829 16.32 34.808 17.688 ;
     RECT  34.693 18.816 34.808 35.304 ;
     RECT  33.653 36.432 34.808 36.456 ;
     RECT  33.581 37.584 34.808 37.608 ;
     RECT  33.581 38.688 34.808 38.712 ;
     RECT  34.765 41.232 34.808 41.256 ;
     RECT  34.369 42.528 34.808 42.552 ;
     RECT  34.693 43.824 34.808 43.848 ;
     RECT  34.808 2.148 34.912 44.292 ;
     RECT  34.912 2.418 35.104 44.022 ;
     RECT  35.104 16.32 35.165 17.88 ;
     RECT  35.104 19.248 35.165 23.304 ;
     RECT  35.104 26.208 35.219 32.52 ;
     RECT  35.165 16.56 35.404 17.88 ;
     RECT  35.104 24.624 35.555 24.84 ;
     RECT  35.104 34.896 35.555 35.448 ;
     RECT  35.165 19.248 35.603 23.064 ;
     RECT  35.219 28.368 35.603 32.52 ;
     RECT  35.104 33.6 35.633 33.624 ;
     RECT  35.603 19.248 35.669 19.992 ;
     RECT  35.404 16.56 35.921 17.016 ;
     RECT  35.104 10.032 36.029 14.952 ;
     RECT  35.921 16.56 36.029 16.872 ;
     RECT  35.104 39.888 36.097 39.912 ;
     RECT  35.104 4.656 36.133 9 ;
     RECT  36.133 4.656 36.179 9.144 ;
     RECT  35.603 32.496 36.205 32.52 ;
     RECT  35.555 35.424 36.241 35.448 ;
     RECT  35.104 36.48 36.241 37.608 ;
     RECT  35.219 26.208 36.38 27.336 ;
     RECT  35.603 28.368 36.38 31.464 ;
     RECT  35.104 38.688 36.421 38.712 ;
     RECT  35.555 24.624 36.565 24.648 ;
     RECT  36.097 39.888 36.565 39.96 ;
     RECT  35.104 40.944 36.565 41.4 ;
     RECT  36.205 32.496 36.601 32.952 ;
     RECT  36.029 10.176 36.709 14.952 ;
     RECT  35.669 19.968 36.709 19.992 ;
     RECT  36.241 35.424 36.709 37.608 ;
     RECT  35.104 2.832 36.764 3.432 ;
     RECT  36.097 18.528 36.781 18.552 ;
     RECT  35.104 42.528 36.812 42.552 ;
     RECT  35.603 20.976 36.817 23.064 ;
     RECT  36.565 24.48 36.817 24.648 ;
     RECT  36.709 34.8 36.853 37.608 ;
     RECT  36.565 39.888 36.853 41.4 ;
     RECT  36.812 42.528 36.853 42.696 ;
     RECT  36.709 10.176 36.997 15.48 ;
     RECT  36.029 16.848 36.997 16.872 ;
     RECT  36.764 2.256 37.025 3.432 ;
     RECT  36.179 4.656 37.025 7.752 ;
     RECT  36.817 20.976 37.033 23.4 ;
     RECT  36.817 24.48 37.033 25.128 ;
     RECT  36.179 8.976 37.045 9.144 ;
     RECT  36.997 10.176 37.045 16.872 ;
     RECT  37.033 20.976 37.045 25.128 ;
     RECT  36.38 26.208 37.045 31.464 ;
     RECT  37.045 20.976 37.093 25.176 ;
     RECT  37.045 26.208 37.093 31.512 ;
     RECT  36.781 18 37.357 18.552 ;
     RECT  36.709 19.824 37.357 19.992 ;
     RECT  36.421 38.688 37.465 38.76 ;
     RECT  36.853 39.744 37.465 42.696 ;
     RECT  37.025 2.256 37.508 7.752 ;
     RECT  37.045 8.976 37.508 16.872 ;
     RECT  37.357 18 37.508 19.992 ;
     RECT  37.093 20.976 37.508 31.512 ;
     RECT  36.601 32.496 37.508 33.048 ;
     RECT  36.853 34.8 37.508 37.656 ;
     RECT  37.465 38.688 37.508 42.696 ;
     RECT  37.508 2.148 37.612 44.292 ;
     RECT  37.612 2.418 37.804 44.022 ;
     RECT  37.804 23.904 37.865 40.536 ;
     RECT  37.804 6.816 37.955 10.632 ;
     RECT  37.865 23.904 37.955 38.52 ;
     RECT  37.804 41.904 38.003 43.368 ;
     RECT  37.804 12.24 38.153 16.008 ;
     RECT  37.955 28.704 38.195 38.52 ;
     RECT  38.003 43.344 38.225 43.368 ;
     RECT  38.195 32.496 38.284 37.128 ;
     RECT  37.955 8.976 38.297 10.632 ;
     RECT  37.804 2.784 38.369 3.384 ;
     RECT  38.284 32.496 38.405 33.096 ;
     RECT  37.955 7.2 38.513 7.752 ;
     RECT  38.369 2.976 38.549 3.384 ;
     RECT  38.549 3.36 38.579 3.384 ;
     RECT  37.804 4.416 38.621 5.304 ;
     RECT  38.621 4.464 38.797 5.304 ;
     RECT  38.003 41.904 38.797 41.928 ;
     RECT  38.153 12.528 38.801 16.008 ;
     RECT  38.284 34.368 38.837 37.128 ;
     RECT  37.804 17.04 38.909 19.704 ;
     RECT  38.909 18.192 38.977 19.704 ;
     RECT  37.804 20.928 38.977 22.872 ;
     RECT  38.797 4.464 39.013 6.072 ;
     RECT  38.513 7.2 39.013 7.464 ;
     RECT  38.909 17.04 39.013 17.064 ;
     RECT  38.837 34.512 39.125 37.128 ;
     RECT  37.865 40.272 39.193 40.536 ;
     RECT  38.797 41.616 39.193 41.928 ;
     RECT  38.405 32.688 39.197 33.096 ;
     RECT  38.195 38.496 39.229 38.52 ;
     RECT  39.193 40.272 39.265 41.928 ;
     RECT  37.955 23.904 39.337 27.672 ;
     RECT  39.337 23.856 39.349 27.672 ;
     RECT  38.195 28.704 39.349 31.464 ;
     RECT  38.297 8.976 39.409 10.152 ;
     RECT  39.125 34.752 39.841 37.128 ;
     RECT  39.841 34.752 39.877 37.464 ;
     RECT  39.229 38.496 39.877 39.096 ;
     RECT  39.409 8.544 39.913 10.152 ;
     RECT  39.625 11.376 39.913 11.4 ;
     RECT  39.349 23.856 40.021 31.464 ;
     RECT  38.801 12.528 40.057 15.576 ;
     RECT  40.021 2.256 40.069 2.28 ;
     RECT  39.445 3.408 40.069 3.432 ;
     RECT  38.977 18.192 40.069 22.872 ;
     RECT  40.021 23.856 40.069 31.512 ;
     RECT  40.069 2.256 40.208 3.432 ;
     RECT  39.013 4.464 40.208 7.464 ;
     RECT  39.913 8.544 40.208 11.4 ;
     RECT  40.057 12.48 40.208 15.576 ;
     RECT  39.013 16.608 40.208 17.064 ;
     RECT  40.069 18.192 40.208 31.512 ;
     RECT  39.197 32.832 40.208 33.096 ;
     RECT  39.877 34.752 40.208 39.096 ;
     RECT  39.265 40.272 40.208 42.216 ;
     RECT  40.208 2.148 40.312 44.292 ;
     RECT  40.312 2.418 40.504 44.022 ;
     RECT  40.504 8.4 40.601 42.264 ;
     RECT  40.601 8.4 40.643 39.912 ;
     RECT  40.643 8.4 40.673 34.776 ;
     RECT  40.601 40.992 40.684 42.264 ;
     RECT  40.643 35.952 40.691 39.768 ;
     RECT  40.673 8.4 40.709 20.616 ;
     RECT  40.673 21.744 40.709 34.776 ;
     RECT  40.684 41.184 40.781 42.264 ;
     RECT  40.504 2.88 40.925 5.592 ;
     RECT  40.709 8.4 40.961 20.52 ;
     RECT  40.925 2.88 40.997 3.576 ;
     RECT  40.925 4.848 41.068 5.592 ;
     RECT  40.997 3.408 41.069 3.576 ;
     RECT  40.691 35.952 41.105 38.76 ;
     RECT  41.105 35.952 41.465 38.712 ;
     RECT  40.781 41.184 41.537 41.928 ;
     RECT  40.504 6.816 41.821 7.224 ;
     RECT  40.709 21.744 41.821 26.232 ;
     RECT  40.709 27.36 41.821 34.776 ;
     RECT  40.961 8.4 41.825 17.64 ;
     RECT  40.961 19.344 41.897 20.52 ;
     RECT  41.825 8.4 41.929 15.528 ;
     RECT  41.068 5.568 42.037 5.592 ;
     RECT  41.897 19.392 42.037 20.52 ;
     RECT  41.821 21.696 42.037 26.232 ;
     RECT  42.037 19.392 42.133 26.232 ;
     RECT  41.069 3.552 42.14 3.576 ;
     RECT  41.821 6.672 42.181 7.224 ;
     RECT  42.037 4.8 42.325 5.592 ;
     RECT  42.181 6.672 42.325 7.272 ;
     RECT  41.825 16.56 42.325 17.64 ;
     RECT  41.537 41.472 42.361 41.928 ;
     RECT  42.361 41.472 42.505 42.792 ;
     RECT  41.821 27.312 42.649 34.776 ;
     RECT  41.465 35.952 42.649 36.312 ;
     RECT  42.14 2.832 42.908 3.576 ;
     RECT  42.325 4.8 42.908 7.272 ;
     RECT  41.929 8.304 42.908 15.528 ;
     RECT  42.325 16.56 42.908 17.688 ;
     RECT  42.133 19.392 42.908 26.28 ;
     RECT  42.649 27.312 42.908 36.312 ;
     RECT  41.465 37.44 42.908 38.712 ;
     RECT  40.691 39.744 42.908 39.768 ;
     RECT  42.505 41.136 42.908 42.792 ;
     RECT  42.908 2.148 43.012 44.292 ;
     RECT  43.012 2.418 43.204 44.022 ;
     RECT  43.204 27.6 43.229 34.776 ;
     RECT  43.204 35.76 43.265 37.464 ;
     RECT  43.229 28.704 43.331 34.776 ;
     RECT  43.265 35.76 43.331 36.552 ;
     RECT  43.204 11.52 43.337 14.088 ;
     RECT  43.331 28.704 43.372 33.912 ;
     RECT  43.372 28.704 43.409 32.616 ;
     RECT  43.204 4.944 43.445 4.968 ;
     RECT  43.204 17.472 43.445 17.64 ;
     RECT  43.204 6.336 43.481 6.36 ;
     RECT  43.229 27.6 43.481 27.624 ;
     RECT  43.372 33.888 43.625 33.912 ;
     RECT  43.331 35.76 43.625 36.12 ;
     RECT  43.625 36.096 43.661 36.12 ;
     RECT  43.204 9.744 43.769 9.768 ;
     RECT  43.445 17.472 43.769 17.496 ;
     RECT  43.204 20.112 44.701 25.896 ;
     RECT  44.701 20.112 44.773 25.992 ;
     RECT  43.409 28.704 45.677 32.136 ;
     RECT  43.337 12.24 46.321 14.088 ;
     RECT  46.321 12.24 46.356 12.264 ;
     RECT  46.321 12.264 46.38 12.336 ;
     RECT  46.321 12.336 46.356 12.36 ;
     RECT  46.321 12.36 46.38 12.432 ;
     RECT  46.321 12.432 46.356 12.456 ;
     RECT  46.321 12.456 46.38 12.528 ;
     RECT  46.321 12.528 46.356 12.552 ;
     RECT  46.321 12.552 46.38 12.624 ;
     RECT  46.321 12.624 46.356 12.648 ;
     RECT  46.321 12.648 46.38 12.72 ;
     RECT  46.321 12.72 46.356 12.744 ;
     RECT  46.321 12.744 46.38 12.816 ;
     RECT  46.321 12.816 46.356 12.84 ;
     RECT  46.321 12.84 46.38 12.912 ;
     RECT  46.321 12.912 46.356 12.936 ;
     RECT  46.321 12.936 46.38 13.008 ;
     RECT  46.321 13.008 46.356 13.032 ;
     RECT  46.321 13.032 46.38 13.104 ;
     RECT  46.321 13.104 46.356 13.128 ;
     RECT  46.321 13.128 46.38 13.2 ;
     RECT  46.321 13.2 46.356 13.224 ;
     RECT  46.321 13.224 46.38 13.296 ;
     RECT  46.321 13.296 46.356 13.32 ;
     RECT  46.321 13.32 46.38 13.392 ;
     RECT  46.321 13.392 46.356 13.416 ;
     RECT  46.321 13.416 46.38 13.488 ;
     RECT  46.321 13.488 46.356 13.512 ;
     RECT  46.321 13.512 46.38 13.584 ;
     RECT  46.321 13.584 46.356 13.608 ;
     RECT  46.321 13.608 46.38 13.68 ;
     RECT  46.321 13.68 46.356 13.704 ;
     RECT  46.321 13.704 46.38 13.776 ;
     RECT  46.321 13.776 46.356 13.8 ;
     RECT  46.321 13.8 46.38 13.872 ;
     RECT  46.321 13.872 46.356 13.896 ;
     RECT  46.321 13.896 46.38 13.968 ;
     RECT  46.321 13.968 46.356 13.992 ;
     RECT  46.321 13.992 46.38 14.064 ;
     RECT  46.321 14.064 46.356 14.088 ;
     RECT  46.321 14.088 46.38 14.232 ;
     RECT  44.773 19.92 46.356 19.944 ;
     RECT  44.773 19.944 46.38 20.016 ;
     RECT  44.773 20.016 46.356 20.04 ;
     RECT  44.773 20.04 46.38 20.112 ;
     RECT  44.773 20.112 46.356 20.136 ;
     RECT  44.773 20.136 46.38 20.208 ;
     RECT  44.773 20.208 46.356 20.232 ;
     RECT  44.773 20.232 46.38 20.304 ;
     RECT  44.773 20.304 46.356 20.328 ;
     RECT  44.773 20.328 46.38 20.4 ;
     RECT  44.773 20.4 46.356 20.424 ;
     RECT  44.773 20.424 46.38 20.496 ;
     RECT  44.773 20.496 46.356 20.52 ;
     RECT  44.773 20.52 46.38 20.592 ;
     RECT  44.773 20.592 46.356 20.616 ;
     RECT  44.773 20.616 46.38 20.688 ;
     RECT  44.773 20.688 46.356 20.712 ;
     RECT  44.773 20.712 46.38 20.784 ;
     RECT  44.773 20.784 46.356 20.808 ;
     RECT  44.773 20.808 46.38 20.88 ;
     RECT  44.773 20.88 46.356 20.904 ;
     RECT  44.773 20.904 46.38 20.976 ;
     RECT  44.773 20.976 46.356 21 ;
     RECT  44.773 21 46.38 21.072 ;
     RECT  44.773 21.072 46.356 21.096 ;
     RECT  44.773 21.096 46.38 21.168 ;
     RECT  44.773 21.168 46.356 21.192 ;
     RECT  44.773 21.192 46.38 21.264 ;
     RECT  44.773 21.264 46.356 21.288 ;
     RECT  44.773 21.288 46.38 21.36 ;
     RECT  44.773 21.36 46.356 21.384 ;
     RECT  44.773 21.384 46.38 21.456 ;
     RECT  44.773 21.456 46.356 21.48 ;
     RECT  44.773 21.48 46.38 21.552 ;
     RECT  44.773 21.552 46.356 21.576 ;
     RECT  44.773 21.576 46.38 21.648 ;
     RECT  44.773 21.648 46.356 21.672 ;
     RECT  44.773 21.672 46.38 21.744 ;
     RECT  44.773 21.744 46.356 21.768 ;
     RECT  44.773 21.768 46.38 21.84 ;
     RECT  44.773 21.84 46.356 21.864 ;
     RECT  44.773 21.864 46.38 21.936 ;
     RECT  44.773 21.936 46.356 21.96 ;
     RECT  44.773 21.96 46.38 22.032 ;
     RECT  44.773 22.032 46.356 22.056 ;
     RECT  44.773 22.056 46.38 22.128 ;
     RECT  44.773 22.128 46.356 22.152 ;
     RECT  44.773 22.152 46.38 22.224 ;
     RECT  44.773 22.224 46.356 22.248 ;
     RECT  44.773 22.248 46.38 22.32 ;
     RECT  44.773 22.32 46.356 22.344 ;
     RECT  44.773 22.344 46.38 22.416 ;
     RECT  44.773 22.416 46.356 22.44 ;
     RECT  44.773 22.44 46.38 22.512 ;
     RECT  44.773 22.512 46.356 22.536 ;
     RECT  44.773 22.536 46.38 22.608 ;
     RECT  44.773 22.608 46.356 22.632 ;
     RECT  44.773 22.632 46.38 22.704 ;
     RECT  44.773 22.704 46.356 22.728 ;
     RECT  44.773 22.728 46.38 22.8 ;
     RECT  44.773 22.8 46.356 22.824 ;
     RECT  44.773 22.824 46.38 22.896 ;
     RECT  44.773 22.896 46.356 22.92 ;
     RECT  44.773 22.92 46.38 22.992 ;
     RECT  44.773 22.992 46.356 23.016 ;
     RECT  44.773 23.016 46.38 23.088 ;
     RECT  44.773 23.088 46.356 23.112 ;
     RECT  44.773 23.112 46.38 23.184 ;
     RECT  44.773 23.184 46.356 23.208 ;
     RECT  44.773 23.208 46.38 23.28 ;
     RECT  44.773 23.28 46.356 23.304 ;
     RECT  44.773 23.304 46.38 23.376 ;
     RECT  44.773 23.376 46.356 23.4 ;
     RECT  44.773 23.4 46.38 23.472 ;
     RECT  44.773 23.472 46.356 23.496 ;
     RECT  44.773 23.496 46.38 23.568 ;
     RECT  44.773 23.568 46.356 23.592 ;
     RECT  44.773 23.592 46.38 23.664 ;
     RECT  44.773 23.664 46.356 23.688 ;
     RECT  44.773 23.688 46.38 23.76 ;
     RECT  44.773 23.76 46.356 23.784 ;
     RECT  44.773 23.784 46.38 23.856 ;
     RECT  44.773 23.856 46.356 23.88 ;
     RECT  44.773 23.88 46.38 23.952 ;
     RECT  44.773 23.952 46.356 23.976 ;
     RECT  44.773 23.976 46.38 24.048 ;
     RECT  44.773 24.048 46.356 24.072 ;
     RECT  44.773 24.072 46.38 24.144 ;
     RECT  44.773 24.144 46.356 24.168 ;
     RECT  44.773 24.168 46.38 24.24 ;
     RECT  44.773 24.24 46.356 24.264 ;
     RECT  44.773 24.264 46.38 24.336 ;
     RECT  44.773 24.336 46.356 24.36 ;
     RECT  44.773 24.36 46.38 24.432 ;
     RECT  44.773 24.432 46.356 24.456 ;
     RECT  44.773 24.456 46.38 24.528 ;
     RECT  44.773 24.528 46.356 24.552 ;
     RECT  44.773 24.552 46.38 24.624 ;
     RECT  44.773 24.624 46.356 24.648 ;
     RECT  44.773 24.648 46.38 24.72 ;
     RECT  44.773 24.72 46.356 24.744 ;
     RECT  44.773 24.744 46.38 24.816 ;
     RECT  44.773 24.816 46.356 24.84 ;
     RECT  44.773 24.84 46.38 24.912 ;
     RECT  44.773 24.912 46.356 24.936 ;
     RECT  44.773 24.936 46.38 25.008 ;
     RECT  44.773 25.008 46.356 25.032 ;
     RECT  44.773 25.032 46.38 25.104 ;
     RECT  44.773 25.104 46.356 25.128 ;
     RECT  44.773 25.128 46.38 25.2 ;
     RECT  44.773 25.2 46.356 25.224 ;
     RECT  44.773 25.224 46.38 25.296 ;
     RECT  44.773 25.296 46.356 25.32 ;
     RECT  44.773 25.32 46.38 25.392 ;
     RECT  44.773 25.392 46.356 25.416 ;
     RECT  44.773 25.416 46.38 25.488 ;
     RECT  44.773 25.488 46.356 25.512 ;
     RECT  44.773 25.512 46.38 25.584 ;
     RECT  44.773 25.584 46.356 25.608 ;
     RECT  44.773 25.608 46.38 25.68 ;
     RECT  44.773 25.68 46.356 25.704 ;
     RECT  44.773 25.704 46.38 25.776 ;
     RECT  44.773 25.776 46.356 25.8 ;
     RECT  44.773 25.8 46.38 25.872 ;
     RECT  44.773 25.872 46.356 25.896 ;
     RECT  44.773 25.896 46.38 25.968 ;
     RECT  44.773 25.968 46.356 25.992 ;
     RECT  45.677 29.136 46.356 29.16 ;
     RECT  45.677 29.16 46.38 29.232 ;
     RECT  45.677 29.232 46.356 29.256 ;
     RECT  45.677 29.256 46.38 29.328 ;
     RECT  45.677 29.328 46.356 29.352 ;
     RECT  45.677 29.352 46.38 29.424 ;
     RECT  45.677 29.424 46.356 29.448 ;
     RECT  45.677 29.448 46.38 29.52 ;
     RECT  45.677 29.52 46.356 29.544 ;
     RECT  45.677 29.544 46.38 29.616 ;
     RECT  45.677 29.616 46.356 29.64 ;
     RECT  45.677 29.64 46.38 29.712 ;
     RECT  45.677 29.712 46.356 29.736 ;
     RECT  45.677 29.736 46.38 29.808 ;
     RECT  45.677 29.808 46.356 29.832 ;
     RECT  45.677 29.832 46.38 29.904 ;
     RECT  45.677 29.904 46.356 29.928 ;
     RECT  45.677 29.928 46.38 30 ;
     RECT  45.677 30 46.356 30.024 ;
     RECT  45.677 30.024 46.38 30.096 ;
     RECT  45.677 30.096 46.356 30.12 ;
     RECT  45.677 30.12 46.38 30.192 ;
     RECT  45.677 30.192 46.356 30.216 ;
     RECT  45.677 30.216 46.38 30.288 ;
     RECT  45.677 30.288 46.356 30.312 ;
     RECT  45.677 30.312 46.38 30.384 ;
     RECT  45.677 30.384 46.356 30.408 ;
     RECT  45.677 30.408 46.38 30.48 ;
     RECT  45.677 30.48 46.356 30.504 ;
     RECT  45.677 30.504 46.38 30.576 ;
     RECT  45.677 30.576 46.356 30.6 ;
     RECT  45.677 30.6 46.38 30.672 ;
     RECT  45.677 30.672 46.356 30.696 ;
     RECT  45.677 30.696 46.38 30.768 ;
     RECT  45.677 30.768 46.356 30.792 ;
     RECT  45.677 30.792 46.38 30.864 ;
     RECT  45.677 30.864 46.356 30.888 ;
     RECT  45.677 30.888 46.38 30.96 ;
     RECT  45.677 30.96 46.356 30.984 ;
     RECT  45.677 30.984 46.38 31.056 ;
     RECT  45.677 31.056 46.356 31.08 ;
     RECT  45.677 31.08 46.38 31.152 ;
     RECT  45.677 31.152 46.356 31.176 ;
     RECT  45.677 31.176 46.38 31.248 ;
     RECT  45.677 31.248 46.356 31.272 ;
     RECT  45.677 31.272 46.38 31.344 ;
     RECT  45.677 31.344 46.356 31.368 ;
     RECT  45.677 31.368 46.38 31.44 ;
     RECT  45.677 31.44 46.356 31.464 ;
     RECT  45.677 31.464 46.38 31.536 ;
     RECT  45.677 31.536 46.356 31.56 ;
     RECT  45.677 31.56 46.38 31.632 ;
     RECT  45.677 31.632 46.356 31.656 ;
     RECT  45.677 31.656 46.38 31.728 ;
     RECT  45.677 31.728 46.356 31.752 ;
     RECT  45.677 31.752 46.38 31.824 ;
     RECT  45.677 31.824 46.356 31.848 ;
     RECT  45.677 31.848 46.38 31.92 ;
     RECT  45.677 31.92 46.356 31.944 ;
     RECT  45.677 31.944 46.38 32.016 ;
     RECT  45.677 32.016 46.356 32.04 ;
     RECT  45.677 32.04 46.38 32.112 ;
     RECT  45.677 32.112 46.356 32.136 ;
     RECT  46.38 13.92 46.397 13.968 ;
     RECT  46.38 13.992 46.397 14.064 ;
     RECT  46.38 14.088 46.397 14.232 ;
     RECT  46.397 14.208 46.433 14.232 ;
    LAYER M5 ;
     RECT  2.4 2.137 2.52 2.151 ;
     RECT  5.1 2.137 5.22 2.151 ;
     RECT  7.8 2.137 7.92 2.151 ;
     RECT  10.5 2.137 10.62 2.151 ;
     RECT  13.2 2.137 13.32 2.151 ;
     RECT  15.9 2.137 16.02 2.151 ;
     RECT  18.6 2.137 18.72 2.151 ;
     RECT  21.3 2.137 21.42 2.151 ;
     RECT  24 2.137 24.12 2.151 ;
     RECT  26.7 2.137 26.82 2.151 ;
     RECT  29.4 2.137 29.52 2.151 ;
     RECT  32.1 2.137 32.22 2.151 ;
     RECT  34.8 2.137 34.92 2.151 ;
     RECT  37.5 2.137 37.62 2.151 ;
     RECT  40.2 2.137 40.32 2.151 ;
     RECT  42.9 2.137 43.02 2.151 ;
     RECT  10.5 2.151 10.812 2.245 ;
     RECT  13.2 2.151 13.512 2.245 ;
     RECT  18.6 2.151 18.912 2.245 ;
     RECT  21.3 2.151 21.612 2.245 ;
     RECT  24 2.151 24.312 2.245 ;
     RECT  26.7 2.151 27.012 2.245 ;
     RECT  37.5 2.151 37.812 2.245 ;
     RECT  40.2 2.151 40.512 2.245 ;
     RECT  26.7 2.245 27.912 2.293 ;
     RECT  32.1 2.151 32.412 2.341 ;
     RECT  29.4 2.151 29.712 2.581 ;
     RECT  18.6 2.245 19.176 2.675 ;
     RECT  13.2 2.245 14.088 2.821 ;
     RECT  15.9 2.151 16.212 2.821 ;
     RECT  32.1 2.341 32.712 2.821 ;
     RECT  42.9 2.151 43.212 2.821 ;
     RECT  10.368 2.245 10.812 2.915 ;
     RECT  23.76 2.245 24.312 3.059 ;
     RECT  10.5 2.915 10.812 3.157 ;
     RECT  12.672 2.821 14.088 3.157 ;
     RECT  36.816 2.245 37.812 3.349 ;
     RECT  30.72 2.869 30.744 3.443 ;
     RECT  36.816 3.349 38.568 3.443 ;
     RECT  40.08 2.245 40.512 3.443 ;
     RECT  40.2 3.443 40.512 3.541 ;
     RECT  10.5 3.157 14.088 3.587 ;
     RECT  42.192 2.821 43.212 3.587 ;
     RECT  25.776 2.293 27.912 3.589 ;
     RECT  29.088 2.581 29.712 3.589 ;
     RECT  5.1 2.151 5.412 3.733 ;
     RECT  24 3.059 24.312 3.925 ;
     RECT  25.776 3.589 29.712 3.925 ;
     RECT  21.12 2.245 21.612 4.115 ;
     RECT  2.4 2.151 2.712 4.261 ;
     RECT  25.776 3.925 30.456 4.645 ;
     RECT  25.536 4.645 30.456 4.691 ;
     RECT  40.2 3.541 41.016 4.883 ;
     RECT  10.5 3.587 11.736 4.931 ;
     RECT  32.1 2.821 33.528 4.979 ;
     RECT  42.9 3.587 43.212 4.981 ;
     RECT  15.408 2.821 16.212 5.029 ;
     RECT  21.3 4.115 21.612 5.029 ;
     RECT  26.7 4.691 30.456 5.075 ;
     RECT  7.8 2.151 8.112 5.077 ;
     RECT  37.056 3.443 38.568 5.315 ;
     RECT  24 3.925 24.408 5.459 ;
     RECT  18.6 2.675 18.912 5.605 ;
     RECT  34.8 2.151 35.112 5.605 ;
     RECT  5.1 3.733 5.544 5.747 ;
     RECT  25.536 4.691 25.56 5.747 ;
     RECT  37.248 5.315 38.568 5.795 ;
     RECT  21.3 5.029 21.768 5.797 ;
     RECT  7.8 5.077 8.232 6.133 ;
     RECT  15.408 5.029 16.584 6.181 ;
     RECT  32.1 4.979 33.288 6.229 ;
     RECT  18.6 5.605 19.464 6.323 ;
     RECT  5.1 5.747 5.412 6.805 ;
     RECT  21.072 5.797 21.768 6.805 ;
     RECT  34.8 5.605 35.4 6.805 ;
     RECT  2.4 4.261 2.904 6.899 ;
     RECT  34.8 6.805 36.168 6.899 ;
     RECT  10.5 4.931 10.812 6.901 ;
     RECT  15.408 6.181 16.68 6.901 ;
     RECT  31.872 6.229 33.288 7.187 ;
     RECT  24 5.459 24.312 7.189 ;
     RECT  7.44 6.133 8.232 7.285 ;
     RECT  20.784 6.805 21.768 7.381 ;
     RECT  24 7.189 25.128 7.381 ;
     RECT  31.968 7.187 33.288 7.381 ;
     RECT  7.44 7.285 8.52 7.427 ;
     RECT  26.7 5.075 29.712 7.427 ;
     RECT  7.44 7.427 8.232 7.765 ;
     RECT  18.6 6.323 18.912 7.765 ;
     RECT  15.408 6.901 16.728 7.909 ;
     RECT  29.136 7.427 29.712 7.909 ;
     RECT  5.1 6.805 5.784 7.957 ;
     RECT  13.2 3.587 14.088 7.957 ;
     RECT  15.408 7.909 17.4 8.003 ;
     RECT  2.4 6.899 2.808 8.195 ;
     RECT  12.384 7.957 14.088 8.293 ;
     RECT  20.784 7.381 22.296 8.435 ;
     RECT  21.3 8.435 22.296 8.483 ;
     RECT  29.136 7.909 29.88 8.485 ;
     RECT  42.768 4.981 43.212 8.485 ;
     RECT  26.7 7.427 27.72 8.533 ;
     RECT  5.1 7.957 6.168 8.579 ;
     RECT  31.968 7.381 33.672 8.579 ;
     RECT  15.9 8.003 17.4 8.963 ;
     RECT  12.384 8.293 14.424 9.011 ;
     RECT  18.6 7.765 19.08 9.013 ;
     RECT  18.6 9.013 20.04 9.059 ;
     RECT  13.056 9.011 14.424 9.107 ;
     RECT  26.7 8.533 27.768 9.107 ;
     RECT  31.968 8.579 33.096 9.107 ;
     RECT  36.144 6.899 36.168 9.155 ;
     RECT  7.344 7.765 8.232 9.299 ;
     RECT  21.3 8.483 22.056 9.395 ;
     RECT  37.5 5.795 38.568 9.397 ;
     RECT  19.968 9.059 20.04 9.731 ;
     RECT  28.8 8.485 29.88 9.827 ;
     RECT  3.936 9.781 3.96 9.923 ;
     RECT  2.4 8.195 2.712 9.925 ;
     RECT  15.9 8.963 16.728 9.973 ;
     RECT  32.1 9.107 33.096 10.069 ;
     RECT  34.8 6.899 35.112 10.069 ;
     RECT  32.1 10.069 35.112 10.115 ;
     RECT  40.2 4.883 40.512 10.117 ;
     RECT  37.056 9.397 38.568 10.163 ;
     RECT  2.4 9.925 3.336 10.165 ;
     RECT  10.272 6.901 10.812 10.165 ;
     RECT  33.984 10.115 35.112 10.165 ;
     RECT  28.896 9.827 29.88 10.211 ;
     RECT  13.056 9.107 14.184 10.213 ;
     RECT  42.288 8.485 43.212 10.307 ;
     RECT  2.304 10.165 3.336 10.355 ;
     RECT  26.7 9.107 27.72 10.355 ;
     RECT  32.1 10.115 33 10.355 ;
     RECT  0.144 10.357 0.168 10.643 ;
     RECT  15.9 9.973 17.064 10.645 ;
     RECT  39.696 10.117 40.512 10.741 ;
     RECT  26.7 10.355 27.528 10.835 ;
     RECT  2.4 10.355 3.336 10.883 ;
     RECT  15.408 10.645 17.064 10.883 ;
     RECT  11.904 10.165 11.928 10.931 ;
     RECT  13.056 10.213 14.232 11.027 ;
     RECT  19.968 9.731 19.992 11.027 ;
     RECT  33.984 10.165 35.208 11.027 ;
     RECT  13.104 11.027 14.232 11.029 ;
     RECT  15.408 10.883 16.212 11.029 ;
     RECT  21.3 9.395 21.72 11.221 ;
     RECT  39.696 10.741 41.304 11.221 ;
     RECT  10.224 10.165 10.812 11.365 ;
     RECT  37.056 10.163 37.944 11.411 ;
     RECT  24 7.381 25.704 11.509 ;
     RECT  26.7 10.835 27.012 11.509 ;
     RECT  6.384 10.069 6.408 11.605 ;
     RECT  6.384 11.605 6.552 11.651 ;
     RECT  24 11.509 27.012 12.035 ;
     RECT  33.984 11.027 35.112 12.035 ;
     RECT  39.696 11.221 41.592 12.035 ;
     RECT  37.296 11.411 37.944 12.229 ;
     RECT  28.896 10.211 29.712 12.373 ;
     RECT  21.3 11.221 22.488 12.517 ;
     RECT  24 12.035 24.312 12.517 ;
     RECT  13.104 11.029 16.212 12.563 ;
     RECT  10.224 11.365 10.92 12.565 ;
     RECT  13.104 12.563 14.04 12.803 ;
     RECT  28.896 12.373 30.6 12.949 ;
     RECT  25.488 12.035 27.012 13.045 ;
     RECT  25.488 13.045 27.336 13.091 ;
     RECT  28.464 12.949 30.6 13.091 ;
     RECT  7.8 9.299 8.232 13.093 ;
     RECT  10.224 12.565 11.112 13.187 ;
     RECT  21.168 12.517 22.488 13.189 ;
     RECT  23.76 12.517 24.312 13.331 ;
     RECT  25.488 13.091 25.704 13.379 ;
     RECT  26.7 13.091 27.336 13.379 ;
     RECT  28.944 13.091 30.6 13.379 ;
     RECT  15.408 12.563 16.212 13.475 ;
     RECT  42.9 10.307 43.212 13.477 ;
     RECT  15.648 13.475 16.212 13.573 ;
     RECT  18.6 9.059 18.912 13.573 ;
     RECT  42.768 13.477 43.212 13.573 ;
     RECT  13.2 12.803 14.04 13.669 ;
     RECT  10.5 13.187 11.112 13.763 ;
     RECT  13.2 13.669 14.664 14.101 ;
     RECT  32.1 10.355 32.412 14.149 ;
     RECT  39.696 12.035 41.256 14.149 ;
     RECT  15.648 13.573 16.344 14.197 ;
     RECT  42.624 13.573 43.212 14.291 ;
     RECT  37.296 12.229 38.136 14.533 ;
     RECT  18.6 13.573 19.416 14.627 ;
     RECT  6.528 11.651 6.552 14.629 ;
     RECT  7.8 13.093 8.376 14.629 ;
     RECT  26.7 13.379 27.012 14.629 ;
     RECT  6.528 14.629 8.376 14.675 ;
     RECT  25.68 13.379 25.704 14.677 ;
     RECT  26.7 14.629 27.384 14.677 ;
     RECT  25.68 14.677 27.384 14.723 ;
     RECT  6.768 14.675 8.376 14.773 ;
     RECT  37.056 14.533 38.136 14.773 ;
     RECT  39.456 14.149 41.256 14.773 ;
     RECT  15.648 14.197 16.92 14.915 ;
     RECT  21.12 13.189 22.488 14.915 ;
     RECT  37.056 14.773 41.256 14.915 ;
     RECT  28.944 13.379 30.216 15.013 ;
     RECT  28.944 15.013 30.696 15.301 ;
     RECT  42.9 14.291 43.212 15.301 ;
     RECT  13.104 14.101 14.664 15.347 ;
     RECT  15.648 14.915 16.344 15.443 ;
     RECT  31.824 14.149 32.412 15.443 ;
     RECT  37.056 14.915 38.76 15.443 ;
     RECT  13.2 15.347 14.664 15.445 ;
     RECT  15.648 15.443 16.212 15.445 ;
     RECT  10.5 13.763 10.812 15.973 ;
     RECT  11.952 14.917 11.976 15.973 ;
     RECT  6.768 14.773 9.144 16.019 ;
     RECT  21.168 14.915 22.488 16.019 ;
     RECT  37.056 15.443 38.136 16.019 ;
     RECT  10.5 15.973 11.976 16.115 ;
     RECT  13.2 15.445 16.212 16.163 ;
     RECT  24 13.331 24.312 16.357 ;
     RECT  26.208 14.723 27.384 16.403 ;
     RECT  28.416 15.301 30.696 16.451 ;
     RECT  26.7 16.403 27.384 16.453 ;
     RECT  28.416 16.451 29.712 16.453 ;
     RECT  6.816 16.019 9.144 16.547 ;
     RECT  26.7 16.453 29.712 16.547 ;
     RECT  42.288 15.301 43.212 16.595 ;
     RECT  40.2 14.915 41.256 16.643 ;
     RECT  3.936 16.597 3.96 16.835 ;
     RECT  33.792 15.829 33.816 16.835 ;
     RECT  34.8 12.035 35.112 17.029 ;
     RECT  6.816 16.547 8.376 17.315 ;
     RECT  37.5 16.019 38.136 17.315 ;
     RECT  26.7 16.547 27.48 17.363 ;
     RECT  21.3 16.019 21.612 17.365 ;
     RECT  28.752 16.547 29.712 17.699 ;
     RECT  33.84 17.029 35.352 17.699 ;
     RECT  42.432 16.595 43.212 17.699 ;
     RECT  34.8 17.699 35.352 17.891 ;
     RECT  2.4 10.883 2.712 17.989 ;
     RECT  5.1 8.579 5.412 18.133 ;
     RECT  10.5 16.115 11.112 18.133 ;
     RECT  13.2 16.163 14.088 18.181 ;
     RECT  15.072 16.163 16.212 18.181 ;
     RECT  24 16.357 24.456 18.181 ;
     RECT  29.4 17.699 29.712 18.181 ;
     RECT  32.1 15.443 32.412 18.181 ;
     RECT  13.2 18.181 16.212 18.757 ;
     RECT  10.5 18.133 11.832 18.899 ;
     RECT  13.104 18.757 16.212 18.995 ;
     RECT  2.4 17.989 2.904 19.093 ;
     RECT  2.4 19.093 3 19.235 ;
     RECT  10.5 18.899 11.16 19.237 ;
     RECT  18.6 14.627 18.912 19.237 ;
     RECT  34.8 17.891 35.112 19.237 ;
     RECT  7.8 17.315 8.376 19.333 ;
     RECT  26.7 17.363 27.012 19.333 ;
     RECT  40.2 16.643 40.512 19.333 ;
     RECT  20.496 17.365 21.612 19.427 ;
     RECT  29.4 18.181 32.412 19.475 ;
     RECT  33.648 18.709 33.672 19.715 ;
     RECT  6.816 19.333 8.376 19.859 ;
     RECT  34.704 19.237 35.112 19.957 ;
     RECT  36.336 18.517 36.36 19.957 ;
     RECT  34.704 19.957 36.36 20.003 ;
     RECT  40.08 19.333 40.512 20.003 ;
     RECT  26.7 19.333 27.336 20.101 ;
     RECT  22.752 19.333 22.776 20.147 ;
     RECT  10.176 19.237 11.16 20.291 ;
     RECT  24 18.181 24.552 20.291 ;
     RECT  34.704 20.003 35.592 20.579 ;
     RECT  13.2 18.995 16.212 20.581 ;
     RECT  13.2 20.581 16.92 20.677 ;
     RECT  13.2 20.677 17.496 20.725 ;
     RECT  18.6 19.237 19.512 20.725 ;
     RECT  24 20.291 24.456 21.061 ;
     RECT  10.176 20.291 10.968 21.155 ;
     RECT  13.2 20.725 19.512 21.205 ;
     RECT  23.568 21.061 24.456 21.205 ;
     RECT  5.1 18.133 5.688 21.301 ;
     RECT  34.704 20.579 35.112 21.541 ;
     RECT  40.2 20.003 40.512 21.637 ;
     RECT  4.128 21.301 5.688 21.683 ;
     RECT  23.376 21.205 24.456 21.683 ;
     RECT  6.816 19.859 8.112 21.923 ;
     RECT  10.176 21.155 10.92 21.971 ;
     RECT  29.4 19.475 29.712 22.021 ;
     RECT  30.96 19.475 32.412 22.021 ;
     RECT  33.744 21.541 35.112 22.259 ;
     RECT  4.128 21.683 5.412 22.307 ;
     RECT  13.056 21.205 19.512 22.739 ;
     RECT  17.472 22.739 19.512 22.741 ;
     RECT  26.7 20.101 27.432 23.029 ;
     RECT  25.824 23.029 27.432 23.075 ;
     RECT  10.5 21.971 10.92 23.411 ;
     RECT  7.8 21.923 8.112 23.797 ;
     RECT  13.056 22.739 16.212 23.987 ;
     RECT  17.472 22.741 19.992 24.227 ;
     RECT  13.056 23.987 14.376 24.323 ;
     RECT  34.704 22.259 35.112 24.421 ;
     RECT  5.1 22.307 5.412 24.469 ;
     RECT  37.5 17.315 37.812 24.469 ;
     RECT  42.9 17.699 43.212 24.469 ;
     RECT  29.4 22.021 32.412 24.563 ;
     RECT  2.4 19.235 2.712 24.613 ;
     RECT  10.5 23.411 10.812 24.757 ;
     RECT  24 21.683 24.456 24.757 ;
     RECT  4.704 24.469 5.412 24.805 ;
     RECT  34.656 24.421 35.112 24.805 ;
     RECT  19.968 24.227 19.992 24.899 ;
     RECT  23.04 24.757 24.456 25.045 ;
     RECT  25.824 23.075 27.012 25.045 ;
     RECT  2.4 24.613 3.576 25.427 ;
     RECT  34.656 24.805 35.544 25.525 ;
     RECT  15.9 23.987 16.212 25.573 ;
     RECT  21.3 19.427 21.612 25.573 ;
     RECT  23.04 25.045 27.012 25.859 ;
     RECT  42.288 24.469 43.212 26.053 ;
     RECT  39.264 21.637 40.512 26.197 ;
     RECT  42.144 26.053 43.212 26.197 ;
     RECT  4.608 24.805 5.412 26.291 ;
     RECT  9.792 24.757 10.812 26.291 ;
     RECT  15.792 25.573 16.212 26.291 ;
     RECT  21.168 25.573 21.612 26.291 ;
     RECT  15.9 26.291 16.212 26.629 ;
     RECT  17.472 24.227 18.912 26.629 ;
     RECT  25.872 25.859 27.012 26.629 ;
     RECT  37.056 24.469 37.812 26.677 ;
     RECT  33.84 25.525 35.544 26.725 ;
     RECT  36.576 26.677 37.812 26.725 ;
     RECT  33.84 26.725 37.812 26.819 ;
     RECT  23.04 25.859 24.456 27.013 ;
     RECT  25.872 26.629 27.384 27.013 ;
     RECT  34.656 26.819 37.812 27.109 ;
     RECT  23.04 27.013 27.384 27.301 ;
     RECT  39.264 26.197 43.212 27.395 ;
     RECT  23.04 27.301 27.432 27.443 ;
     RECT  20.16 26.197 20.184 27.587 ;
     RECT  39.36 27.395 43.212 27.635 ;
     RECT  34.656 27.109 37.944 27.637 ;
     RECT  15.9 26.629 18.912 27.731 ;
     RECT  13.2 24.323 14.376 27.781 ;
     RECT  17.472 27.731 18.912 27.877 ;
     RECT  29.4 24.563 29.712 27.877 ;
     RECT  30.96 24.563 32.412 27.877 ;
     RECT  39.36 27.635 41.208 27.923 ;
     RECT  7.8 23.797 8.52 27.971 ;
     RECT  39.36 27.923 41.064 27.971 ;
     RECT  34.656 27.637 38.232 28.453 ;
     RECT  13.2 27.781 14.856 28.499 ;
     RECT  13.2 28.499 13.512 28.501 ;
     RECT  34.032 28.453 38.232 28.547 ;
     RECT  9.216 28.693 9.24 28.789 ;
     RECT  10.5 26.291 10.812 28.789 ;
     RECT  9.216 28.789 10.812 28.931 ;
     RECT  5.1 26.291 5.412 29.029 ;
     RECT  6.528 26.581 6.552 29.029 ;
     RECT  25.632 27.443 27.432 29.075 ;
     RECT  12.816 28.501 13.512 29.171 ;
     RECT  23.04 27.443 24.6 29.171 ;
     RECT  34.032 28.547 35.544 29.651 ;
     RECT  9.936 28.931 10.812 29.795 ;
     RECT  23.04 29.171 24.456 30.037 ;
     RECT  5.1 29.029 6.552 30.085 ;
     RECT  7.8 27.971 8.232 30.085 ;
     RECT  22.752 30.037 24.456 30.181 ;
     RECT  25.632 29.075 27.144 30.181 ;
     RECT  39.696 27.971 41.064 30.181 ;
     RECT  22.752 30.181 27.144 30.227 ;
     RECT  15.9 27.731 16.212 30.277 ;
     RECT  17.472 27.877 19.08 30.277 ;
     RECT  15.9 30.277 19.08 30.467 ;
     RECT  34.032 29.651 35.208 30.467 ;
     RECT  36.576 28.547 38.232 30.467 ;
     RECT  21.3 26.291 21.612 30.469 ;
     RECT  21.168 30.469 21.612 30.517 ;
     RECT  36.672 30.467 38.232 30.563 ;
     RECT  5.1 30.085 8.232 30.803 ;
     RECT  10.5 29.795 10.812 30.853 ;
     RECT  7.296 30.803 8.232 30.899 ;
     RECT  21.072 30.517 21.612 30.899 ;
     RECT  13.2 29.171 13.512 30.949 ;
     RECT  34.8 30.467 35.208 30.997 ;
     RECT  39.696 30.181 41.112 30.997 ;
     RECT  39.696 30.997 41.592 31.091 ;
     RECT  17.472 30.467 19.08 31.285 ;
     RECT  40.032 31.091 41.592 31.331 ;
     RECT  7.68 30.899 8.232 31.379 ;
     RECT  26.208 30.227 27.144 31.427 ;
     RECT  40.032 31.331 40.512 31.523 ;
     RECT  9.216 31.477 9.24 31.621 ;
     RECT  10.224 30.853 10.812 31.621 ;
     RECT  13.2 30.949 13.608 31.715 ;
     RECT  3.936 31.669 3.96 31.811 ;
     RECT  21.168 30.899 21.612 31.811 ;
     RECT  9.216 31.621 10.812 31.861 ;
     RECT  15.9 30.467 16.212 31.861 ;
     RECT  34.8 30.997 35.352 31.861 ;
     RECT  17.472 31.285 19.992 32.051 ;
     RECT  34.8 31.861 35.592 32.053 ;
     RECT  42.9 27.635 43.212 32.053 ;
     RECT  5.1 30.803 5.592 32.339 ;
     RECT  26.256 31.427 27.144 32.341 ;
     RECT  29.4 27.877 32.412 32.389 ;
     RECT  5.1 32.339 5.544 32.435 ;
     RECT  6.624 32.389 6.648 32.437 ;
     RECT  7.68 31.379 8.112 32.437 ;
     RECT  36.672 30.563 38.184 32.531 ;
     RECT  41.568 31.331 41.592 32.531 ;
     RECT  13.2 31.715 13.512 32.821 ;
     RECT  17.952 32.051 19.992 32.821 ;
     RECT  15.216 31.861 16.212 33.013 ;
     RECT  13.104 32.821 13.512 33.059 ;
     RECT  28.464 32.389 32.412 33.059 ;
     RECT  15.216 33.013 16.536 33.107 ;
     RECT  40.08 31.523 40.512 33.107 ;
     RECT  15.9 33.107 16.536 33.155 ;
     RECT  9.216 31.861 11.16 33.299 ;
     RECT  22.752 30.227 25.128 33.349 ;
     RECT  26.256 32.341 27.384 33.349 ;
     RECT  42.9 32.053 43.368 33.349 ;
     RECT  36.672 32.531 37.812 33.589 ;
     RECT  40.2 33.107 40.512 33.589 ;
     RECT  6.624 32.437 8.112 33.827 ;
     RECT  30.816 33.059 32.412 33.827 ;
     RECT  42.768 33.349 43.368 33.923 ;
     RECT  36.672 33.589 37.944 33.925 ;
     RECT  13.2 33.059 13.512 34.117 ;
     RECT  42.768 33.923 43.32 34.213 ;
     RECT  17.952 32.821 20.328 34.259 ;
     RECT  34.224 32.053 35.592 34.261 ;
     RECT  18.096 34.259 20.328 34.355 ;
     RECT  9.744 33.299 11.16 34.403 ;
     RECT  33.456 34.261 35.592 34.451 ;
     RECT  28.464 33.059 29.712 34.739 ;
     RECT  40.2 33.589 40.824 34.741 ;
     RECT  40.08 34.741 40.824 34.787 ;
     RECT  12.528 34.117 13.512 34.835 ;
     RECT  22.752 33.349 27.384 34.835 ;
     RECT  22.752 34.835 25.128 34.883 ;
     RECT  6.624 33.827 6.648 34.931 ;
     RECT  42.72 34.213 43.32 34.931 ;
     RECT  36.672 33.925 38.232 34.979 ;
     RECT  7.68 33.827 8.112 34.981 ;
     RECT  22.752 34.883 24.84 35.077 ;
     RECT  20.304 34.355 20.328 35.173 ;
     RECT  21.3 31.811 21.612 35.173 ;
     RECT  40.08 34.787 40.632 35.317 ;
     RECT  9.744 34.403 10.812 35.363 ;
     RECT  29.184 34.739 29.712 35.411 ;
     RECT  39.888 35.317 40.632 35.459 ;
     RECT  30.96 33.827 32.412 35.507 ;
     RECT  26.112 34.835 27.384 35.747 ;
     RECT  10.5 35.363 10.812 35.845 ;
     RECT  15.9 33.155 16.392 35.989 ;
     RECT  13.2 34.835 13.512 36.181 ;
     RECT  26.208 35.747 27.384 36.275 ;
     RECT  18.096 34.355 19.08 36.325 ;
     RECT  20.304 35.173 21.612 36.325 ;
     RECT  39.888 35.459 40.512 36.325 ;
     RECT  34.8 34.451 35.592 36.373 ;
     RECT  36.672 34.979 37.812 36.373 ;
     RECT  32.1 35.507 32.412 36.469 ;
     RECT  33.456 34.451 33.48 36.469 ;
     RECT  10.5 35.845 11.496 36.515 ;
     RECT  22.656 35.077 24.84 36.515 ;
     RECT  32.1 36.469 33.48 36.515 ;
     RECT  34.8 36.373 37.812 36.515 ;
     RECT  32.1 36.515 33.192 36.517 ;
     RECT  42.9 34.931 43.32 36.563 ;
     RECT  30.96 35.507 30.984 36.611 ;
     RECT  29.28 35.411 29.712 36.901 ;
     RECT  10.5 36.515 10.812 36.949 ;
     RECT  26.208 36.275 27.012 36.949 ;
     RECT  36.384 36.515 37.812 36.997 ;
     RECT  36.384 36.997 38.184 37.043 ;
     RECT  13.056 36.181 13.512 37.093 ;
     RECT  7.44 34.981 8.112 37.379 ;
     RECT  5.1 32.435 5.412 37.573 ;
     RECT  15.9 35.989 17.064 37.573 ;
     RECT  42.9 36.563 43.212 37.573 ;
     RECT  3.696 37.477 3.816 37.619 ;
     RECT  9.936 36.949 10.812 37.619 ;
     RECT  31.968 36.517 33.192 37.619 ;
     RECT  25.584 36.949 27.012 37.667 ;
     RECT  29.28 36.901 29.832 37.667 ;
     RECT  36.864 37.043 38.184 37.667 ;
     RECT  15.408 37.573 17.064 37.859 ;
     RECT  37.008 37.667 38.184 37.859 ;
     RECT  29.4 37.667 29.832 37.907 ;
     RECT  18.096 36.325 21.612 38.051 ;
     RECT  39.408 36.325 40.512 38.581 ;
     RECT  37.008 37.859 37.812 38.723 ;
     RECT  39.408 38.581 41.016 38.723 ;
     RECT  42.048 37.573 43.212 38.723 ;
     RECT  10.368 37.619 10.812 38.725 ;
     RECT  26.208 37.667 27.012 38.725 ;
     RECT  22.656 36.515 24.456 38.749 ;
     RECT  7.488 37.379 8.112 38.771 ;
     RECT  31.968 37.619 33.096 39.109 ;
     RECT  26.208 38.725 27.96 39.155 ;
     RECT  26.448 39.155 27.96 39.299 ;
     RECT  12.912 37.093 13.512 39.301 ;
     RECT  31.968 39.109 33.48 39.395 ;
     RECT  3.792 37.619 3.816 39.491 ;
     RECT  39.408 38.723 40.68 39.491 ;
     RECT  37.5 38.723 37.812 39.733 ;
     RECT  42.768 38.723 43.212 39.779 ;
     RECT  15.408 37.859 16.212 39.829 ;
     RECT  7.68 38.771 8.112 39.877 ;
     RECT  12.72 39.301 13.512 39.971 ;
     RECT  26.592 39.299 27.96 40.067 ;
     RECT  7.68 39.877 8.616 40.115 ;
     RECT  10.272 38.725 10.812 40.163 ;
     RECT  21.3 38.051 21.612 40.405 ;
     RECT  22.704 38.749 24.456 40.405 ;
     RECT  26.592 40.067 27.012 40.405 ;
     RECT  18.096 38.051 19.992 40.453 ;
     RECT  39.408 39.491 40.632 40.499 ;
     RECT  33.456 39.395 33.48 40.547 ;
     RECT  18.096 40.453 20.136 40.595 ;
     RECT  20.112 40.595 20.136 40.885 ;
     RECT  21.3 40.405 24.456 40.885 ;
     RECT  7.8 40.115 8.616 40.979 ;
     RECT  13.2 39.971 13.512 40.981 ;
     RECT  31.968 39.395 32.412 40.981 ;
     RECT  20.112 40.885 24.456 41.027 ;
     RECT  15.408 39.829 16.344 41.173 ;
     RECT  13.2 40.981 13.704 41.555 ;
     RECT  25.68 40.405 27.012 41.555 ;
     RECT  5.1 37.573 5.544 41.557 ;
     RECT  3.936 39.925 3.96 41.651 ;
     RECT  15.408 41.173 16.44 41.651 ;
     RECT  20.112 41.027 21.612 41.651 ;
     RECT  39.696 40.499 40.632 41.651 ;
     RECT  31.296 40.981 32.412 41.891 ;
     RECT  42.9 39.779 43.212 41.893 ;
     RECT  40.08 41.651 40.512 41.939 ;
     RECT  7.8 40.979 8.112 42.181 ;
     RECT  32.1 41.891 32.412 42.181 ;
     RECT  10.32 40.163 10.812 42.227 ;
     RECT  20.976 41.651 21.612 42.227 ;
     RECT  28.032 41.557 28.056 42.227 ;
     RECT  7.8 42.181 8.856 42.323 ;
     RECT  12.048 40.405 12.072 42.323 ;
     RECT  18.096 40.595 18.912 42.565 ;
     RECT  36.864 39.733 37.812 42.707 ;
     RECT  13.2 41.555 13.512 42.709 ;
     RECT  26.208 41.555 27.012 42.709 ;
     RECT  37.5 42.707 37.812 42.709 ;
     RECT  32.1 42.181 33.048 42.755 ;
     RECT  10.5 42.227 10.812 42.757 ;
     RECT  22.704 41.027 24.456 42.803 ;
     RECT  42.384 41.893 43.212 42.803 ;
     RECT  3.936 42.709 3.96 42.851 ;
     RECT  17.712 42.565 18.912 42.853 ;
     RECT  5.1 41.557 6.312 42.899 ;
     RECT  22.896 42.803 24.456 43.091 ;
     RECT  29.4 37.907 29.712 43.285 ;
     RECT  15.9 41.651 16.44 43.331 ;
     RECT  26.208 42.709 27.384 43.379 ;
     RECT  37.5 42.709 37.992 43.379 ;
     RECT  10.5 42.757 11.016 43.621 ;
     RECT  7.8 42.323 8.664 43.955 ;
     RECT  17.664 42.853 18.912 43.955 ;
     RECT  29.04 43.285 29.712 43.955 ;
     RECT  13.2 42.709 13.944 44.051 ;
     RECT  17.712 43.955 18.912 44.051 ;
     RECT  10.5 43.621 11.784 44.147 ;
     RECT  22.896 43.091 24.312 44.147 ;
     RECT  2.4 25.427 2.712 44.289 ;
     RECT  5.1 42.899 5.412 44.289 ;
     RECT  7.8 43.955 8.112 44.289 ;
     RECT  10.5 44.147 10.812 44.289 ;
     RECT  13.2 44.051 13.512 44.289 ;
     RECT  15.9 43.331 16.212 44.289 ;
     RECT  18.096 44.051 18.912 44.289 ;
     RECT  21.3 42.227 21.612 44.289 ;
     RECT  24 44.147 24.312 44.289 ;
     RECT  26.7 43.379 27.012 44.289 ;
     RECT  29.4 43.955 29.712 44.289 ;
     RECT  32.1 42.755 32.412 44.289 ;
     RECT  34.8 36.515 35.112 44.289 ;
     RECT  37.5 43.379 37.812 44.289 ;
     RECT  40.2 41.939 40.512 44.289 ;
     RECT  42.9 42.803 43.212 44.289 ;
     RECT  2.4 44.289 2.52 44.303 ;
     RECT  5.1 44.289 5.22 44.303 ;
     RECT  7.8 44.289 7.92 44.303 ;
     RECT  10.5 44.289 10.62 44.303 ;
     RECT  13.2 44.289 13.32 44.303 ;
     RECT  15.9 44.289 16.02 44.303 ;
     RECT  18.096 44.289 18.72 44.303 ;
     RECT  21.3 44.289 21.42 44.303 ;
     RECT  24 44.289 24.12 44.303 ;
     RECT  26.7 44.289 26.82 44.303 ;
     RECT  29.4 44.289 29.52 44.303 ;
     RECT  32.1 44.289 32.22 44.303 ;
     RECT  34.8 44.289 34.92 44.303 ;
     RECT  37.5 44.289 37.62 44.303 ;
     RECT  40.2 44.289 40.32 44.303 ;
     RECT  42.9 44.289 43.02 44.303 ;
     RECT  22.896 44.147 22.92 45.923 ;
     RECT  18.096 44.303 18.12 46.403 ;
     RECT  27.912 2.245 29.4 2.581 ;
     RECT  24.312 2.293 25.776 3.925 ;
     RECT  27.912 2.581 29.088 3.589 ;
     RECT  14.088 2.821 15.408 8.003 ;
     RECT  33.528 2.821 34.8 4.979 ;
     RECT  29.712 2.869 30.72 3.443 ;
     RECT  30.744 2.869 32.1 3.443 ;
     RECT  38.568 3.349 40.08 3.443 ;
     RECT  29.712 3.443 30.456 3.925 ;
     RECT  41.016 3.541 42.192 3.587 ;
     RECT  11.736 3.587 13.2 4.931 ;
     RECT  42.768 3.587 42.9 4.981 ;
     RECT  24.408 3.925 25.776 4.645 ;
     RECT  24.408 4.645 25.536 5.459 ;
     RECT  25.56 4.691 26.7 5.747 ;
     RECT  33.288 4.979 34.8 7.381 ;
     RECT  37.056 5.315 37.248 5.795 ;
     RECT  24.312 5.459 25.536 5.747 ;
     RECT  5.412 5.747 5.544 6.805 ;
     RECT  24.312 5.747 25.128 7.189 ;
     RECT  37.056 5.795 37.5 6.805 ;
     RECT  18.912 6.323 19.08 7.765 ;
     RECT  36.168 6.805 37.5 9.155 ;
     RECT  35.112 6.899 36.144 9.155 ;
     RECT  25.704 7.381 26.7 11.509 ;
     RECT  33.672 7.381 34.8 8.579 ;
     RECT  27.72 7.427 29.136 8.485 ;
     RECT  17.4 7.909 18.6 8.963 ;
     RECT  6.168 7.957 7.344 8.579 ;
     RECT  14.088 8.003 15.9 8.293 ;
     RECT  14.424 8.293 15.9 9.107 ;
     RECT  20.784 8.435 21.3 9.013 ;
     RECT  27.72 8.485 28.8 8.533 ;
     RECT  27.768 8.533 28.8 9.107 ;
     RECT  5.412 8.579 7.344 9.299 ;
     RECT  33.096 8.579 34.8 10.069 ;
     RECT  16.728 8.963 17.064 9.973 ;
     RECT  12.384 9.011 13.056 10.165 ;
     RECT  20.04 9.013 21.3 9.731 ;
     RECT  18.912 9.059 19.968 11.027 ;
     RECT  14.184 9.107 14.232 10.213 ;
     RECT  27.72 9.107 28.8 9.827 ;
     RECT  35.112 9.155 35.208 10.165 ;
     RECT  37.056 9.155 37.5 9.397 ;
     RECT  5.412 9.299 7.8 10.069 ;
     RECT  19.992 9.731 21.3 11.027 ;
     RECT  2.712 9.781 3.936 9.923 ;
     RECT  3.96 9.781 5.1 9.923 ;
     RECT  27.72 9.827 28.896 10.355 ;
     RECT  2.712 9.923 3.336 9.925 ;
     RECT  5.412 10.069 6.384 11.651 ;
     RECT  6.408 10.069 7.8 11.605 ;
     RECT  33 10.115 33.984 10.355 ;
     RECT  38.568 10.117 39.696 10.163 ;
     RECT  10.812 10.165 11.904 10.931 ;
     RECT  11.928 10.165 13.056 10.931 ;
     RECT  42.288 10.307 42.9 10.741 ;
     RECT  27.528 10.355 28.896 10.835 ;
     RECT  14.232 10.645 15.408 11.029 ;
     RECT  41.304 10.741 42.9 11.221 ;
     RECT  10.812 10.931 10.92 11.365 ;
     RECT  21.168 11.027 21.3 12.517 ;
     RECT  22.488 11.221 24 12.517 ;
     RECT  41.592 11.221 42.9 12.035 ;
     RECT  6.552 11.605 7.8 14.629 ;
     RECT  5.412 11.651 6.528 14.675 ;
     RECT  24.312 12.035 25.488 13.379 ;
     RECT  41.256 12.035 42.9 13.477 ;
     RECT  30.6 12.373 32.1 13.379 ;
     RECT  22.488 12.517 23.76 13.331 ;
     RECT  14.04 12.563 15.408 13.475 ;
     RECT  13.104 12.803 13.2 14.101 ;
     RECT  27.012 12.949 28.464 13.045 ;
     RECT  27.336 13.045 28.464 13.091 ;
     RECT  25.704 13.091 26.7 14.677 ;
     RECT  22.488 13.331 24 16.019 ;
     RECT  24.312 13.379 25.68 14.723 ;
     RECT  27.012 13.379 27.336 14.629 ;
     RECT  31.824 13.379 32.1 14.149 ;
     RECT  14.04 13.475 15.648 13.669 ;
     RECT  41.256 13.477 42.768 13.573 ;
     RECT  41.256 13.573 42.624 14.291 ;
     RECT  14.664 13.669 15.648 15.445 ;
     RECT  10.812 13.763 11.112 14.917 ;
     RECT  38.136 14.149 39.456 14.773 ;
     RECT  41.256 14.291 42.9 15.301 ;
     RECT  5.412 14.675 6.768 16.019 ;
     RECT  9.144 14.773 10.5 16.547 ;
     RECT  38.76 14.915 40.2 15.443 ;
     RECT  10.812 14.917 11.952 15.973 ;
     RECT  11.976 14.917 13.104 15.347 ;
     RECT  30.696 15.013 31.824 15.443 ;
     RECT  27.384 15.301 28.416 16.453 ;
     RECT  41.256 15.301 42.288 16.595 ;
     RECT  11.976 15.347 13.2 16.115 ;
     RECT  30.696 15.443 32.1 16.451 ;
     RECT  32.412 15.829 33.792 16.835 ;
     RECT  33.816 15.829 34.8 16.835 ;
     RECT  5.412 16.019 6.816 17.315 ;
     RECT  21.168 16.019 21.3 17.365 ;
     RECT  14.088 16.163 15.072 18.181 ;
     RECT  27.48 16.547 28.752 17.363 ;
     RECT  41.256 16.595 42.432 16.643 ;
     RECT  2.712 16.597 3.936 16.835 ;
     RECT  3.96 16.597 5.1 16.835 ;
     RECT  2.712 16.835 2.904 17.989 ;
     RECT  32.412 16.835 34.8 17.029 ;
     RECT  32.412 17.029 33.84 17.699 ;
     RECT  5.412 17.315 5.688 18.133 ;
     RECT  32.412 17.699 34.8 18.709 ;
     RECT  35.112 17.891 35.352 18.517 ;
     RECT  11.832 18.133 13.2 18.757 ;
     RECT  35.112 18.517 36.336 19.957 ;
     RECT  36.36 18.517 37.5 20.003 ;
     RECT  32.412 18.709 33.648 19.715 ;
     RECT  33.672 18.709 34.8 19.237 ;
     RECT  11.832 18.757 13.104 18.899 ;
     RECT  19.512 19.237 20.496 19.427 ;
     RECT  33.672 19.237 34.704 19.715 ;
     RECT  5.688 19.333 6.816 21.683 ;
     RECT  21.612 19.333 22.752 20.147 ;
     RECT  22.776 19.333 24 20.147 ;
     RECT  29.712 19.475 30.96 22.021 ;
     RECT  23.376 20.147 24 21.061 ;
     RECT  17.496 20.677 18.6 20.725 ;
     RECT  23.376 21.061 23.568 21.205 ;
     RECT  2.712 21.301 4.128 22.307 ;
     RECT  32.412 21.541 33.744 22.259 ;
     RECT  37.812 21.637 39.264 27.109 ;
     RECT  5.412 21.683 6.816 21.923 ;
     RECT  16.212 22.739 17.472 26.629 ;
     RECT  19.992 22.741 21.3 24.899 ;
     RECT  24.456 23.029 25.824 25.045 ;
     RECT  14.376 23.987 15.9 25.573 ;
     RECT  18.912 24.227 19.968 24.899 ;
     RECT  29.712 24.563 30.96 27.877 ;
     RECT  3.576 24.613 4.704 24.805 ;
     RECT  8.52 24.757 9.792 26.291 ;
     RECT  21.612 24.757 23.04 30.037 ;
     RECT  3.576 24.805 4.608 25.427 ;
     RECT  35.544 24.805 37.056 26.677 ;
     RECT  18.912 24.899 21.3 25.573 ;
     RECT  32.412 25.525 33.84 26.819 ;
     RECT  14.376 25.573 15.792 26.291 ;
     RECT  18.912 25.573 21.168 26.197 ;
     RECT  24.456 25.859 25.872 27.013 ;
     RECT  18.912 26.197 20.16 27.587 ;
     RECT  20.184 26.197 21.168 26.291 ;
     RECT  14.376 26.291 15.9 27.781 ;
     RECT  20.184 26.291 21.3 27.587 ;
     RECT  5.412 26.581 6.528 29.029 ;
     RECT  6.552 26.581 7.8 30.085 ;
     RECT  35.544 26.677 36.576 26.725 ;
     RECT  37.944 27.109 39.264 27.395 ;
     RECT  37.944 27.395 39.36 27.637 ;
     RECT  24.6 27.443 25.632 29.171 ;
     RECT  18.912 27.587 19.08 27.877 ;
     RECT  38.232 27.637 39.36 27.971 ;
     RECT  16.212 27.731 17.472 30.277 ;
     RECT  14.856 27.781 15.9 28.499 ;
     RECT  8.232 27.971 8.52 28.693 ;
     RECT  38.232 27.971 39.696 30.563 ;
     RECT  35.544 28.547 36.576 29.651 ;
     RECT  8.232 28.693 9.216 28.931 ;
     RECT  9.24 28.693 10.5 28.789 ;
     RECT  24.456 29.171 25.632 30.181 ;
     RECT  35.208 29.651 36.576 30.467 ;
     RECT  10.224 29.795 10.5 30.853 ;
     RECT  21.612 30.037 22.752 35.077 ;
     RECT  25.128 30.227 26.208 31.427 ;
     RECT  16.212 30.467 17.472 32.051 ;
     RECT  35.208 30.467 36.672 30.997 ;
     RECT  38.184 30.563 39.696 31.091 ;
     RECT  7.296 30.899 7.68 32.389 ;
     RECT  21.072 30.899 21.168 31.285 ;
     RECT  35.352 30.997 36.672 31.861 ;
     RECT  41.592 30.997 42.9 32.531 ;
     RECT  19.992 31.285 21.168 31.811 ;
     RECT  40.512 31.331 41.568 32.531 ;
     RECT  8.112 31.379 8.232 31.477 ;
     RECT  25.128 31.427 26.256 33.349 ;
     RECT  8.112 31.477 9.216 33.299 ;
     RECT  9.24 31.477 10.224 31.621 ;
     RECT  2.712 31.669 3.936 31.811 ;
     RECT  3.96 31.669 5.1 31.811 ;
     RECT  19.992 31.811 21.3 32.821 ;
     RECT  35.592 31.861 36.672 36.373 ;
     RECT  16.212 32.051 17.952 33.013 ;
     RECT  5.544 32.339 5.592 32.389 ;
     RECT  5.544 32.389 6.624 32.435 ;
     RECT  6.648 32.389 7.68 32.437 ;
     RECT  27.384 32.389 28.464 34.739 ;
     RECT  5.412 32.435 6.624 34.931 ;
     RECT  37.812 32.531 38.184 33.589 ;
     RECT  40.512 32.531 40.824 33.589 ;
     RECT  42.768 32.531 42.9 33.349 ;
     RECT  20.328 32.821 21.3 35.173 ;
     RECT  16.536 33.013 17.952 33.155 ;
     RECT  13.104 33.059 13.2 34.117 ;
     RECT  29.712 33.059 30.816 33.827 ;
     RECT  37.944 33.589 38.184 33.925 ;
     RECT  6.648 33.827 7.68 34.931 ;
     RECT  29.712 33.827 30.96 36.611 ;
     RECT  11.16 34.117 12.528 34.403 ;
     RECT  32.412 34.261 33.456 36.469 ;
     RECT  19.08 34.355 20.304 36.325 ;
     RECT  10.812 34.403 12.528 34.835 ;
     RECT  33.48 34.451 34.8 36.515 ;
     RECT  10.812 34.835 11.496 35.845 ;
     RECT  13.056 34.835 13.2 36.181 ;
     RECT  25.128 34.835 26.112 34.883 ;
     RECT  24.84 34.883 26.112 35.747 ;
     RECT  7.44 34.931 7.68 34.981 ;
     RECT  21.612 35.077 22.656 38.749 ;
     RECT  30.984 35.507 32.1 36.517 ;
     RECT  24.84 35.747 26.208 36.515 ;
     RECT  17.064 35.989 18.096 37.859 ;
     RECT  24.456 36.515 26.208 36.949 ;
     RECT  35.112 36.515 36.384 37.043 ;
     RECT  30.984 36.517 31.968 36.611 ;
     RECT  29.712 36.611 29.832 36.901 ;
     RECT  24.456 36.949 25.584 37.667 ;
     RECT  38.184 36.997 39.408 37.859 ;
     RECT  2.712 37.477 3.696 37.619 ;
     RECT  3.816 37.477 5.1 39.491 ;
     RECT  2.712 37.619 3.792 39.491 ;
     RECT  10.272 37.619 10.368 38.725 ;
     RECT  33.096 37.619 33.192 39.109 ;
     RECT  29.28 37.667 29.4 38.725 ;
     RECT  19.992 38.051 21.3 40.453 ;
     RECT  41.016 38.581 42.048 38.723 ;
     RECT  37.008 38.723 37.5 39.733 ;
     RECT  27.96 38.725 29.4 40.067 ;
     RECT  21.612 38.749 22.704 40.405 ;
     RECT  33.48 39.109 34.8 40.547 ;
     RECT  26.208 39.155 26.448 39.299 ;
     RECT  26.208 39.299 26.592 40.405 ;
     RECT  32.412 39.395 33.456 40.547 ;
     RECT  2.712 39.491 5.1 39.925 ;
     RECT  2.712 39.925 3.936 41.651 ;
     RECT  3.96 39.925 5.1 41.651 ;
     RECT  12.72 39.971 13.2 40.405 ;
     RECT  27.012 40.067 29.4 41.557 ;
     RECT  7.68 40.115 7.8 41.557 ;
     RECT  10.812 40.405 12.048 42.323 ;
     RECT  12.072 40.405 13.2 42.323 ;
     RECT  24.456 40.405 25.68 41.555 ;
     RECT  20.136 40.453 21.3 40.885 ;
     RECT  18.912 40.595 20.112 41.651 ;
     RECT  8.112 40.979 8.616 42.181 ;
     RECT  21.612 41.027 22.704 42.803 ;
     RECT  13.512 41.555 13.704 42.709 ;
     RECT  6.312 41.557 7.8 42.899 ;
     RECT  27.012 41.557 28.032 42.227 ;
     RECT  28.056 41.557 29.4 42.227 ;
     RECT  2.712 41.651 5.1 42.709 ;
     RECT  8.856 42.181 10.32 42.227 ;
     RECT  27.012 42.227 27.384 42.709 ;
     RECT  29.04 42.227 29.4 43.285 ;
     RECT  10.812 42.323 13.2 42.757 ;
     RECT  16.44 42.565 17.712 42.853 ;
     RECT  2.712 42.709 3.936 42.851 ;
     RECT  3.96 42.709 5.1 42.851 ;
     RECT  11.016 42.757 13.2 43.621 ;
     RECT  21.612 42.803 22.896 44.289 ;
     RECT  16.44 42.853 17.664 43.331 ;
     RECT  16.212 43.331 17.664 43.955 ;
     RECT  11.784 43.621 13.2 44.147 ;
     RECT  16.212 43.955 17.712 44.051 ;
     RECT  22.92 44.147 24 44.303 ;
     RECT  21.42 44.289 22.896 44.303 ;
  END
END qfd_landh0d8_116_EW_46x46
END LIBRARY
